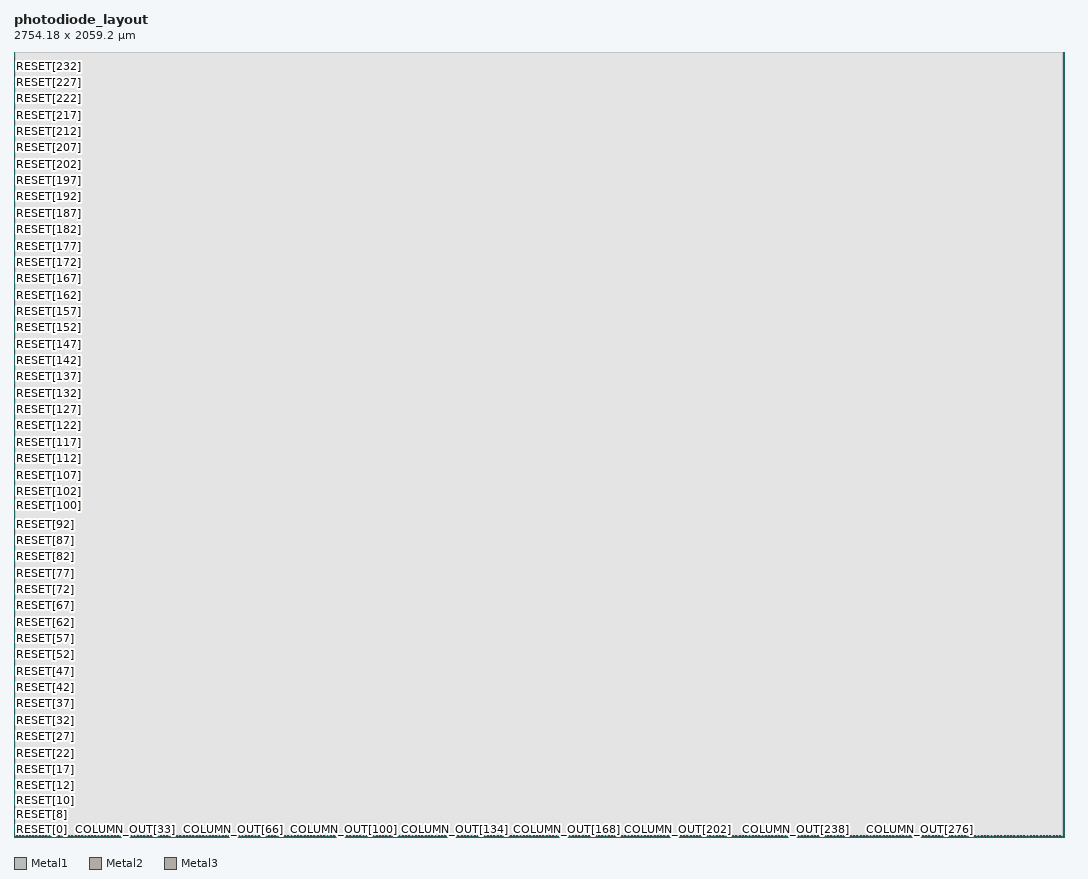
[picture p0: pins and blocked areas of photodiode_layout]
MACRO photodiode_layout
  CLASS BLOCK ;
  ORIGIN 0 0 ;
  FOREIGN photodiode_layout ;
  SIZE 2754.18 BY 2059.2 ;
  SYMMETRY X Y ;

  PIN ROW_SELECT[0]
    DIRECTION INPUT ;
    USE SIGNAL ;
    PORT
      LAYER Metal1 ;
        RECT 0.250 2.730 0.530 2.980 ;
    END
  END ROW_SELECT[0]

  PIN ROW_SELECT[1]
    DIRECTION INPUT ;
    USE SIGNAL ;
    PORT
      LAYER Metal1 ;
        RECT 0.250 11.310 0.530 11.560 ;
    END
  END ROW_SELECT[1]

  PIN ROW_SELECT[2]
    DIRECTION INPUT ;
    USE SIGNAL ;
    PORT
      LAYER Metal1 ;
        RECT 0.250 19.890 0.530 20.140 ;
    END
  END ROW_SELECT[2]

  PIN ROW_SELECT[3]
    DIRECTION INPUT ;
    USE SIGNAL ;
    PORT
      LAYER Metal1 ;
        RECT 0.250 28.470 0.530 28.720 ;
    END
  END ROW_SELECT[3]

  PIN ROW_SELECT[4]
    DIRECTION INPUT ;
    USE SIGNAL ;
    PORT
      LAYER Metal1 ;
        RECT 0.250 37.050 0.530 37.300 ;
    END
  END ROW_SELECT[4]

  PIN ROW_SELECT[5]
    DIRECTION INPUT ;
    USE SIGNAL ;
    PORT
      LAYER Metal1 ;
        RECT 0.250 45.630 0.530 45.880 ;
    END
  END ROW_SELECT[5]

  PIN ROW_SELECT[6]
    DIRECTION INPUT ;
    USE SIGNAL ;
    PORT
      LAYER Metal1 ;
        RECT 0.250 54.210 0.530 54.460 ;
    END
  END ROW_SELECT[6]

  PIN ROW_SELECT[7]
    DIRECTION INPUT ;
    USE SIGNAL ;
    PORT
      LAYER Metal1 ;
        RECT 0.250 62.790 0.530 63.040 ;
    END
  END ROW_SELECT[7]

  PIN ROW_SELECT[8]
    DIRECTION INPUT ;
    USE SIGNAL ;
    PORT
      LAYER Metal1 ;
        RECT 0.250 71.370 0.530 71.620 ;
    END
  END ROW_SELECT[8]

  PIN ROW_SELECT[9]
    DIRECTION INPUT ;
    USE SIGNAL ;
    PORT
      LAYER Metal1 ;
        RECT 0.250 79.950 0.530 80.200 ;
    END
  END ROW_SELECT[9]

  PIN ROW_SELECT[10]
    DIRECTION INPUT ;
    USE SIGNAL ;
    PORT
      LAYER Metal1 ;
        RECT 0.250 88.530 0.530 88.780 ;
    END
  END ROW_SELECT[10]

  PIN ROW_SELECT[11]
    DIRECTION INPUT ;
    USE SIGNAL ;
    PORT
      LAYER Metal1 ;
        RECT 0.250 97.110 0.530 97.360 ;
    END
  END ROW_SELECT[11]

  PIN ROW_SELECT[12]
    DIRECTION INPUT ;
    USE SIGNAL ;
    PORT
      LAYER Metal1 ;
        RECT 0.250 105.690 0.530 105.940 ;
    END
  END ROW_SELECT[12]

  PIN ROW_SELECT[13]
    DIRECTION INPUT ;
    USE SIGNAL ;
    PORT
      LAYER Metal1 ;
        RECT 0.250 114.270 0.530 114.520 ;
    END
  END ROW_SELECT[13]

  PIN ROW_SELECT[14]
    DIRECTION INPUT ;
    USE SIGNAL ;
    PORT
      LAYER Metal1 ;
        RECT 0.250 122.850 0.530 123.100 ;
    END
  END ROW_SELECT[14]

  PIN ROW_SELECT[15]
    DIRECTION INPUT ;
    USE SIGNAL ;
    PORT
      LAYER Metal1 ;
        RECT 0.250 131.430 0.530 131.680 ;
    END
  END ROW_SELECT[15]

  PIN ROW_SELECT[16]
    DIRECTION INPUT ;
    USE SIGNAL ;
    PORT
      LAYER Metal1 ;
        RECT 0.250 140.010 0.530 140.260 ;
    END
  END ROW_SELECT[16]

  PIN ROW_SELECT[17]
    DIRECTION INPUT ;
    USE SIGNAL ;
    PORT
      LAYER Metal1 ;
        RECT 0.250 148.590 0.530 148.840 ;
    END
  END ROW_SELECT[17]

  PIN ROW_SELECT[18]
    DIRECTION INPUT ;
    USE SIGNAL ;
    PORT
      LAYER Metal1 ;
        RECT 0.250 157.170 0.530 157.420 ;
    END
  END ROW_SELECT[18]

  PIN ROW_SELECT[19]
    DIRECTION INPUT ;
    USE SIGNAL ;
    PORT
      LAYER Metal1 ;
        RECT 0.250 165.750 0.530 166.000 ;
    END
  END ROW_SELECT[19]

  PIN ROW_SELECT[20]
    DIRECTION INPUT ;
    USE SIGNAL ;
    PORT
      LAYER Metal1 ;
        RECT 0.250 174.330 0.530 174.580 ;
    END
  END ROW_SELECT[20]

  PIN ROW_SELECT[21]
    DIRECTION INPUT ;
    USE SIGNAL ;
    PORT
      LAYER Metal1 ;
        RECT 0.250 182.910 0.530 183.160 ;
    END
  END ROW_SELECT[21]

  PIN ROW_SELECT[22]
    DIRECTION INPUT ;
    USE SIGNAL ;
    PORT
      LAYER Metal1 ;
        RECT 0.250 191.490 0.530 191.740 ;
    END
  END ROW_SELECT[22]

  PIN ROW_SELECT[23]
    DIRECTION INPUT ;
    USE SIGNAL ;
    PORT
      LAYER Metal1 ;
        RECT 0.250 200.070 0.530 200.320 ;
    END
  END ROW_SELECT[23]

  PIN ROW_SELECT[24]
    DIRECTION INPUT ;
    USE SIGNAL ;
    PORT
      LAYER Metal1 ;
        RECT 0.250 208.650 0.530 208.900 ;
    END
  END ROW_SELECT[24]

  PIN ROW_SELECT[25]
    DIRECTION INPUT ;
    USE SIGNAL ;
    PORT
      LAYER Metal1 ;
        RECT 0.250 217.230 0.530 217.480 ;
    END
  END ROW_SELECT[25]

  PIN ROW_SELECT[26]
    DIRECTION INPUT ;
    USE SIGNAL ;
    PORT
      LAYER Metal1 ;
        RECT 0.250 225.810 0.530 226.060 ;
    END
  END ROW_SELECT[26]

  PIN ROW_SELECT[27]
    DIRECTION INPUT ;
    USE SIGNAL ;
    PORT
      LAYER Metal1 ;
        RECT 0.250 234.390 0.530 234.640 ;
    END
  END ROW_SELECT[27]

  PIN ROW_SELECT[28]
    DIRECTION INPUT ;
    USE SIGNAL ;
    PORT
      LAYER Metal1 ;
        RECT 0.250 242.970 0.530 243.220 ;
    END
  END ROW_SELECT[28]

  PIN ROW_SELECT[29]
    DIRECTION INPUT ;
    USE SIGNAL ;
    PORT
      LAYER Metal1 ;
        RECT 0.250 251.550 0.530 251.800 ;
    END
  END ROW_SELECT[29]

  PIN ROW_SELECT[30]
    DIRECTION INPUT ;
    USE SIGNAL ;
    PORT
      LAYER Metal1 ;
        RECT 0.250 260.130 0.530 260.380 ;
    END
  END ROW_SELECT[30]

  PIN ROW_SELECT[31]
    DIRECTION INPUT ;
    USE SIGNAL ;
    PORT
      LAYER Metal1 ;
        RECT 0.250 268.710 0.530 268.960 ;
    END
  END ROW_SELECT[31]

  PIN ROW_SELECT[32]
    DIRECTION INPUT ;
    USE SIGNAL ;
    PORT
      LAYER Metal1 ;
        RECT 0.250 277.290 0.530 277.540 ;
    END
  END ROW_SELECT[32]

  PIN ROW_SELECT[33]
    DIRECTION INPUT ;
    USE SIGNAL ;
    PORT
      LAYER Metal1 ;
        RECT 0.250 285.870 0.530 286.120 ;
    END
  END ROW_SELECT[33]

  PIN ROW_SELECT[34]
    DIRECTION INPUT ;
    USE SIGNAL ;
    PORT
      LAYER Metal1 ;
        RECT 0.250 294.450 0.530 294.700 ;
    END
  END ROW_SELECT[34]

  PIN ROW_SELECT[35]
    DIRECTION INPUT ;
    USE SIGNAL ;
    PORT
      LAYER Metal1 ;
        RECT 0.250 303.030 0.530 303.280 ;
    END
  END ROW_SELECT[35]

  PIN ROW_SELECT[36]
    DIRECTION INPUT ;
    USE SIGNAL ;
    PORT
      LAYER Metal1 ;
        RECT 0.250 311.610 0.530 311.860 ;
    END
  END ROW_SELECT[36]

  PIN ROW_SELECT[37]
    DIRECTION INPUT ;
    USE SIGNAL ;
    PORT
      LAYER Metal1 ;
        RECT 0.250 320.190 0.530 320.440 ;
    END
  END ROW_SELECT[37]

  PIN ROW_SELECT[38]
    DIRECTION INPUT ;
    USE SIGNAL ;
    PORT
      LAYER Metal1 ;
        RECT 0.250 328.770 0.530 329.020 ;
    END
  END ROW_SELECT[38]

  PIN ROW_SELECT[39]
    DIRECTION INPUT ;
    USE SIGNAL ;
    PORT
      LAYER Metal1 ;
        RECT 0.250 337.350 0.530 337.600 ;
    END
  END ROW_SELECT[39]

  PIN ROW_SELECT[40]
    DIRECTION INPUT ;
    USE SIGNAL ;
    PORT
      LAYER Metal1 ;
        RECT 0.250 345.930 0.530 346.180 ;
    END
  END ROW_SELECT[40]

  PIN ROW_SELECT[41]
    DIRECTION INPUT ;
    USE SIGNAL ;
    PORT
      LAYER Metal1 ;
        RECT 0.250 354.510 0.530 354.760 ;
    END
  END ROW_SELECT[41]

  PIN ROW_SELECT[42]
    DIRECTION INPUT ;
    USE SIGNAL ;
    PORT
      LAYER Metal1 ;
        RECT 0.250 363.090 0.530 363.340 ;
    END
  END ROW_SELECT[42]

  PIN ROW_SELECT[43]
    DIRECTION INPUT ;
    USE SIGNAL ;
    PORT
      LAYER Metal1 ;
        RECT 0.250 371.670 0.530 371.920 ;
    END
  END ROW_SELECT[43]

  PIN ROW_SELECT[44]
    DIRECTION INPUT ;
    USE SIGNAL ;
    PORT
      LAYER Metal1 ;
        RECT 0.250 380.250 0.530 380.500 ;
    END
  END ROW_SELECT[44]

  PIN ROW_SELECT[45]
    DIRECTION INPUT ;
    USE SIGNAL ;
    PORT
      LAYER Metal1 ;
        RECT 0.250 388.830 0.530 389.080 ;
    END
  END ROW_SELECT[45]

  PIN ROW_SELECT[46]
    DIRECTION INPUT ;
    USE SIGNAL ;
    PORT
      LAYER Metal1 ;
        RECT 0.250 397.410 0.530 397.660 ;
    END
  END ROW_SELECT[46]

  PIN ROW_SELECT[47]
    DIRECTION INPUT ;
    USE SIGNAL ;
    PORT
      LAYER Metal1 ;
        RECT 0.250 405.990 0.530 406.240 ;
    END
  END ROW_SELECT[47]

  PIN ROW_SELECT[48]
    DIRECTION INPUT ;
    USE SIGNAL ;
    PORT
      LAYER Metal1 ;
        RECT 0.250 414.570 0.530 414.820 ;
    END
  END ROW_SELECT[48]

  PIN ROW_SELECT[49]
    DIRECTION INPUT ;
    USE SIGNAL ;
    PORT
      LAYER Metal1 ;
        RECT 0.250 423.150 0.530 423.400 ;
    END
  END ROW_SELECT[49]

  PIN ROW_SELECT[50]
    DIRECTION INPUT ;
    USE SIGNAL ;
    PORT
      LAYER Metal1 ;
        RECT 0.250 431.730 0.530 431.980 ;
    END
  END ROW_SELECT[50]

  PIN ROW_SELECT[51]
    DIRECTION INPUT ;
    USE SIGNAL ;
    PORT
      LAYER Metal1 ;
        RECT 0.250 440.310 0.530 440.560 ;
    END
  END ROW_SELECT[51]

  PIN ROW_SELECT[52]
    DIRECTION INPUT ;
    USE SIGNAL ;
    PORT
      LAYER Metal1 ;
        RECT 0.250 448.890 0.530 449.140 ;
    END
  END ROW_SELECT[52]

  PIN ROW_SELECT[53]
    DIRECTION INPUT ;
    USE SIGNAL ;
    PORT
      LAYER Metal1 ;
        RECT 0.250 457.470 0.530 457.720 ;
    END
  END ROW_SELECT[53]

  PIN ROW_SELECT[54]
    DIRECTION INPUT ;
    USE SIGNAL ;
    PORT
      LAYER Metal1 ;
        RECT 0.250 466.050 0.530 466.300 ;
    END
  END ROW_SELECT[54]

  PIN ROW_SELECT[55]
    DIRECTION INPUT ;
    USE SIGNAL ;
    PORT
      LAYER Metal1 ;
        RECT 0.250 474.630 0.530 474.880 ;
    END
  END ROW_SELECT[55]

  PIN ROW_SELECT[56]
    DIRECTION INPUT ;
    USE SIGNAL ;
    PORT
      LAYER Metal1 ;
        RECT 0.250 483.210 0.530 483.460 ;
    END
  END ROW_SELECT[56]

  PIN ROW_SELECT[57]
    DIRECTION INPUT ;
    USE SIGNAL ;
    PORT
      LAYER Metal1 ;
        RECT 0.250 491.790 0.530 492.040 ;
    END
  END ROW_SELECT[57]

  PIN ROW_SELECT[58]
    DIRECTION INPUT ;
    USE SIGNAL ;
    PORT
      LAYER Metal1 ;
        RECT 0.250 500.370 0.530 500.620 ;
    END
  END ROW_SELECT[58]

  PIN ROW_SELECT[59]
    DIRECTION INPUT ;
    USE SIGNAL ;
    PORT
      LAYER Metal1 ;
        RECT 0.250 508.950 0.530 509.200 ;
    END
  END ROW_SELECT[59]

  PIN ROW_SELECT[60]
    DIRECTION INPUT ;
    USE SIGNAL ;
    PORT
      LAYER Metal1 ;
        RECT 0.250 517.530 0.530 517.780 ;
    END
  END ROW_SELECT[60]

  PIN ROW_SELECT[61]
    DIRECTION INPUT ;
    USE SIGNAL ;
    PORT
      LAYER Metal1 ;
        RECT 0.250 526.110 0.530 526.360 ;
    END
  END ROW_SELECT[61]

  PIN ROW_SELECT[62]
    DIRECTION INPUT ;
    USE SIGNAL ;
    PORT
      LAYER Metal1 ;
        RECT 0.250 534.690 0.530 534.940 ;
    END
  END ROW_SELECT[62]

  PIN ROW_SELECT[63]
    DIRECTION INPUT ;
    USE SIGNAL ;
    PORT
      LAYER Metal1 ;
        RECT 0.250 543.270 0.530 543.520 ;
    END
  END ROW_SELECT[63]

  PIN ROW_SELECT[64]
    DIRECTION INPUT ;
    USE SIGNAL ;
    PORT
      LAYER Metal1 ;
        RECT 0.250 551.850 0.530 552.100 ;
    END
  END ROW_SELECT[64]

  PIN ROW_SELECT[65]
    DIRECTION INPUT ;
    USE SIGNAL ;
    PORT
      LAYER Metal1 ;
        RECT 0.250 560.430 0.530 560.680 ;
    END
  END ROW_SELECT[65]

  PIN ROW_SELECT[66]
    DIRECTION INPUT ;
    USE SIGNAL ;
    PORT
      LAYER Metal1 ;
        RECT 0.250 569.010 0.530 569.260 ;
    END
  END ROW_SELECT[66]

  PIN ROW_SELECT[67]
    DIRECTION INPUT ;
    USE SIGNAL ;
    PORT
      LAYER Metal1 ;
        RECT 0.250 577.590 0.530 577.840 ;
    END
  END ROW_SELECT[67]

  PIN ROW_SELECT[68]
    DIRECTION INPUT ;
    USE SIGNAL ;
    PORT
      LAYER Metal1 ;
        RECT 0.250 586.170 0.530 586.420 ;
    END
  END ROW_SELECT[68]

  PIN ROW_SELECT[69]
    DIRECTION INPUT ;
    USE SIGNAL ;
    PORT
      LAYER Metal1 ;
        RECT 0.250 594.750 0.530 595.000 ;
    END
  END ROW_SELECT[69]

  PIN ROW_SELECT[70]
    DIRECTION INPUT ;
    USE SIGNAL ;
    PORT
      LAYER Metal1 ;
        RECT 0.250 603.330 0.530 603.580 ;
    END
  END ROW_SELECT[70]

  PIN ROW_SELECT[71]
    DIRECTION INPUT ;
    USE SIGNAL ;
    PORT
      LAYER Metal1 ;
        RECT 0.250 611.910 0.530 612.160 ;
    END
  END ROW_SELECT[71]

  PIN ROW_SELECT[72]
    DIRECTION INPUT ;
    USE SIGNAL ;
    PORT
      LAYER Metal1 ;
        RECT 0.250 620.490 0.530 620.740 ;
    END
  END ROW_SELECT[72]

  PIN ROW_SELECT[73]
    DIRECTION INPUT ;
    USE SIGNAL ;
    PORT
      LAYER Metal1 ;
        RECT 0.250 629.070 0.530 629.320 ;
    END
  END ROW_SELECT[73]

  PIN ROW_SELECT[74]
    DIRECTION INPUT ;
    USE SIGNAL ;
    PORT
      LAYER Metal1 ;
        RECT 0.250 637.650 0.530 637.900 ;
    END
  END ROW_SELECT[74]

  PIN ROW_SELECT[75]
    DIRECTION INPUT ;
    USE SIGNAL ;
    PORT
      LAYER Metal1 ;
        RECT 0.250 646.230 0.530 646.480 ;
    END
  END ROW_SELECT[75]

  PIN ROW_SELECT[76]
    DIRECTION INPUT ;
    USE SIGNAL ;
    PORT
      LAYER Metal1 ;
        RECT 0.250 654.810 0.530 655.060 ;
    END
  END ROW_SELECT[76]

  PIN ROW_SELECT[77]
    DIRECTION INPUT ;
    USE SIGNAL ;
    PORT
      LAYER Metal1 ;
        RECT 0.250 663.390 0.530 663.640 ;
    END
  END ROW_SELECT[77]

  PIN ROW_SELECT[78]
    DIRECTION INPUT ;
    USE SIGNAL ;
    PORT
      LAYER Metal1 ;
        RECT 0.250 671.970 0.530 672.220 ;
    END
  END ROW_SELECT[78]

  PIN ROW_SELECT[79]
    DIRECTION INPUT ;
    USE SIGNAL ;
    PORT
      LAYER Metal1 ;
        RECT 0.250 680.550 0.530 680.800 ;
    END
  END ROW_SELECT[79]

  PIN ROW_SELECT[80]
    DIRECTION INPUT ;
    USE SIGNAL ;
    PORT
      LAYER Metal1 ;
        RECT 0.250 689.130 0.530 689.380 ;
    END
  END ROW_SELECT[80]

  PIN ROW_SELECT[81]
    DIRECTION INPUT ;
    USE SIGNAL ;
    PORT
      LAYER Metal1 ;
        RECT 0.250 697.710 0.530 697.960 ;
    END
  END ROW_SELECT[81]

  PIN ROW_SELECT[82]
    DIRECTION INPUT ;
    USE SIGNAL ;
    PORT
      LAYER Metal1 ;
        RECT 0.250 706.290 0.530 706.540 ;
    END
  END ROW_SELECT[82]

  PIN ROW_SELECT[83]
    DIRECTION INPUT ;
    USE SIGNAL ;
    PORT
      LAYER Metal1 ;
        RECT 0.250 714.870 0.530 715.120 ;
    END
  END ROW_SELECT[83]

  PIN ROW_SELECT[84]
    DIRECTION INPUT ;
    USE SIGNAL ;
    PORT
      LAYER Metal1 ;
        RECT 0.250 723.450 0.530 723.700 ;
    END
  END ROW_SELECT[84]

  PIN ROW_SELECT[85]
    DIRECTION INPUT ;
    USE SIGNAL ;
    PORT
      LAYER Metal1 ;
        RECT 0.250 732.030 0.530 732.280 ;
    END
  END ROW_SELECT[85]

  PIN ROW_SELECT[86]
    DIRECTION INPUT ;
    USE SIGNAL ;
    PORT
      LAYER Metal1 ;
        RECT 0.250 740.610 0.530 740.860 ;
    END
  END ROW_SELECT[86]

  PIN ROW_SELECT[87]
    DIRECTION INPUT ;
    USE SIGNAL ;
    PORT
      LAYER Metal1 ;
        RECT 0.250 749.190 0.530 749.440 ;
    END
  END ROW_SELECT[87]

  PIN ROW_SELECT[88]
    DIRECTION INPUT ;
    USE SIGNAL ;
    PORT
      LAYER Metal1 ;
        RECT 0.250 757.770 0.530 758.020 ;
    END
  END ROW_SELECT[88]

  PIN ROW_SELECT[89]
    DIRECTION INPUT ;
    USE SIGNAL ;
    PORT
      LAYER Metal1 ;
        RECT 0.250 766.350 0.530 766.600 ;
    END
  END ROW_SELECT[89]

  PIN ROW_SELECT[90]
    DIRECTION INPUT ;
    USE SIGNAL ;
    PORT
      LAYER Metal1 ;
        RECT 0.250 774.930 0.530 775.180 ;
    END
  END ROW_SELECT[90]

  PIN ROW_SELECT[91]
    DIRECTION INPUT ;
    USE SIGNAL ;
    PORT
      LAYER Metal1 ;
        RECT 0.250 783.510 0.530 783.760 ;
    END
  END ROW_SELECT[91]

  PIN ROW_SELECT[92]
    DIRECTION INPUT ;
    USE SIGNAL ;
    PORT
      LAYER Metal1 ;
        RECT 0.250 792.090 0.530 792.340 ;
    END
  END ROW_SELECT[92]

  PIN ROW_SELECT[93]
    DIRECTION INPUT ;
    USE SIGNAL ;
    PORT
      LAYER Metal1 ;
        RECT 0.250 800.670 0.530 800.920 ;
    END
  END ROW_SELECT[93]

  PIN ROW_SELECT[94]
    DIRECTION INPUT ;
    USE SIGNAL ;
    PORT
      LAYER Metal1 ;
        RECT 0.250 809.250 0.530 809.500 ;
    END
  END ROW_SELECT[94]

  PIN ROW_SELECT[95]
    DIRECTION INPUT ;
    USE SIGNAL ;
    PORT
      LAYER Metal1 ;
        RECT 0.250 817.830 0.530 818.080 ;
    END
  END ROW_SELECT[95]

  PIN ROW_SELECT[96]
    DIRECTION INPUT ;
    USE SIGNAL ;
    PORT
      LAYER Metal1 ;
        RECT 0.250 826.410 0.530 826.660 ;
    END
  END ROW_SELECT[96]

  PIN ROW_SELECT[97]
    DIRECTION INPUT ;
    USE SIGNAL ;
    PORT
      LAYER Metal1 ;
        RECT 0.250 834.990 0.530 835.240 ;
    END
  END ROW_SELECT[97]

  PIN ROW_SELECT[98]
    DIRECTION INPUT ;
    USE SIGNAL ;
    PORT
      LAYER Metal1 ;
        RECT 0.250 843.570 0.530 843.820 ;
    END
  END ROW_SELECT[98]

  PIN ROW_SELECT[99]
    DIRECTION INPUT ;
    USE SIGNAL ;
    PORT
      LAYER Metal1 ;
        RECT 0.250 852.150 0.530 852.400 ;
    END
  END ROW_SELECT[99]

  PIN ROW_SELECT[100]
    DIRECTION INPUT ;
    USE SIGNAL ;
    PORT
      LAYER Metal1 ;
        RECT 0.250 860.730 0.530 860.980 ;
    END
  END ROW_SELECT[100]

  PIN ROW_SELECT[101]
    DIRECTION INPUT ;
    USE SIGNAL ;
    PORT
      LAYER Metal1 ;
        RECT 0.250 869.310 0.530 869.560 ;
    END
  END ROW_SELECT[101]

  PIN ROW_SELECT[102]
    DIRECTION INPUT ;
    USE SIGNAL ;
    PORT
      LAYER Metal1 ;
        RECT 0.250 877.890 0.530 878.140 ;
    END
  END ROW_SELECT[102]

  PIN ROW_SELECT[103]
    DIRECTION INPUT ;
    USE SIGNAL ;
    PORT
      LAYER Metal1 ;
        RECT 0.250 886.470 0.530 886.720 ;
    END
  END ROW_SELECT[103]

  PIN ROW_SELECT[104]
    DIRECTION INPUT ;
    USE SIGNAL ;
    PORT
      LAYER Metal1 ;
        RECT 0.250 895.050 0.530 895.300 ;
    END
  END ROW_SELECT[104]

  PIN ROW_SELECT[105]
    DIRECTION INPUT ;
    USE SIGNAL ;
    PORT
      LAYER Metal1 ;
        RECT 0.250 903.630 0.530 903.880 ;
    END
  END ROW_SELECT[105]

  PIN ROW_SELECT[106]
    DIRECTION INPUT ;
    USE SIGNAL ;
    PORT
      LAYER Metal1 ;
        RECT 0.250 912.210 0.530 912.460 ;
    END
  END ROW_SELECT[106]

  PIN ROW_SELECT[107]
    DIRECTION INPUT ;
    USE SIGNAL ;
    PORT
      LAYER Metal1 ;
        RECT 0.250 920.790 0.530 921.040 ;
    END
  END ROW_SELECT[107]

  PIN ROW_SELECT[108]
    DIRECTION INPUT ;
    USE SIGNAL ;
    PORT
      LAYER Metal1 ;
        RECT 0.250 929.370 0.530 929.620 ;
    END
  END ROW_SELECT[108]

  PIN ROW_SELECT[109]
    DIRECTION INPUT ;
    USE SIGNAL ;
    PORT
      LAYER Metal1 ;
        RECT 0.250 937.950 0.530 938.200 ;
    END
  END ROW_SELECT[109]

  PIN ROW_SELECT[110]
    DIRECTION INPUT ;
    USE SIGNAL ;
    PORT
      LAYER Metal1 ;
        RECT 0.250 946.530 0.530 946.780 ;
    END
  END ROW_SELECT[110]

  PIN ROW_SELECT[111]
    DIRECTION INPUT ;
    USE SIGNAL ;
    PORT
      LAYER Metal1 ;
        RECT 0.250 955.110 0.530 955.360 ;
    END
  END ROW_SELECT[111]

  PIN ROW_SELECT[112]
    DIRECTION INPUT ;
    USE SIGNAL ;
    PORT
      LAYER Metal1 ;
        RECT 0.250 963.690 0.530 963.940 ;
    END
  END ROW_SELECT[112]

  PIN ROW_SELECT[113]
    DIRECTION INPUT ;
    USE SIGNAL ;
    PORT
      LAYER Metal1 ;
        RECT 0.250 972.270 0.530 972.520 ;
    END
  END ROW_SELECT[113]

  PIN ROW_SELECT[114]
    DIRECTION INPUT ;
    USE SIGNAL ;
    PORT
      LAYER Metal1 ;
        RECT 0.250 980.850 0.530 981.100 ;
    END
  END ROW_SELECT[114]

  PIN ROW_SELECT[115]
    DIRECTION INPUT ;
    USE SIGNAL ;
    PORT
      LAYER Metal1 ;
        RECT 0.250 989.430 0.530 989.680 ;
    END
  END ROW_SELECT[115]

  PIN ROW_SELECT[116]
    DIRECTION INPUT ;
    USE SIGNAL ;
    PORT
      LAYER Metal1 ;
        RECT 0.250 998.010 0.530 998.260 ;
    END
  END ROW_SELECT[116]

  PIN ROW_SELECT[117]
    DIRECTION INPUT ;
    USE SIGNAL ;
    PORT
      LAYER Metal1 ;
        RECT 0.250 1006.590 0.530 1006.840 ;
    END
  END ROW_SELECT[117]

  PIN ROW_SELECT[118]
    DIRECTION INPUT ;
    USE SIGNAL ;
    PORT
      LAYER Metal1 ;
        RECT 0.250 1015.170 0.530 1015.420 ;
    END
  END ROW_SELECT[118]

  PIN ROW_SELECT[119]
    DIRECTION INPUT ;
    USE SIGNAL ;
    PORT
      LAYER Metal1 ;
        RECT 0.250 1023.750 0.530 1024.000 ;
    END
  END ROW_SELECT[119]

  PIN ROW_SELECT[120]
    DIRECTION INPUT ;
    USE SIGNAL ;
    PORT
      LAYER Metal1 ;
        RECT 0.250 1032.330 0.530 1032.580 ;
    END
  END ROW_SELECT[120]

  PIN ROW_SELECT[121]
    DIRECTION INPUT ;
    USE SIGNAL ;
    PORT
      LAYER Metal1 ;
        RECT 0.250 1040.910 0.530 1041.160 ;
    END
  END ROW_SELECT[121]

  PIN ROW_SELECT[122]
    DIRECTION INPUT ;
    USE SIGNAL ;
    PORT
      LAYER Metal1 ;
        RECT 0.250 1049.490 0.530 1049.740 ;
    END
  END ROW_SELECT[122]

  PIN ROW_SELECT[123]
    DIRECTION INPUT ;
    USE SIGNAL ;
    PORT
      LAYER Metal1 ;
        RECT 0.250 1058.070 0.530 1058.320 ;
    END
  END ROW_SELECT[123]

  PIN ROW_SELECT[124]
    DIRECTION INPUT ;
    USE SIGNAL ;
    PORT
      LAYER Metal1 ;
        RECT 0.250 1066.650 0.530 1066.900 ;
    END
  END ROW_SELECT[124]

  PIN ROW_SELECT[125]
    DIRECTION INPUT ;
    USE SIGNAL ;
    PORT
      LAYER Metal1 ;
        RECT 0.250 1075.230 0.530 1075.480 ;
    END
  END ROW_SELECT[125]

  PIN ROW_SELECT[126]
    DIRECTION INPUT ;
    USE SIGNAL ;
    PORT
      LAYER Metal1 ;
        RECT 0.250 1083.810 0.530 1084.060 ;
    END
  END ROW_SELECT[126]

  PIN ROW_SELECT[127]
    DIRECTION INPUT ;
    USE SIGNAL ;
    PORT
      LAYER Metal1 ;
        RECT 0.250 1092.390 0.530 1092.640 ;
    END
  END ROW_SELECT[127]

  PIN ROW_SELECT[128]
    DIRECTION INPUT ;
    USE SIGNAL ;
    PORT
      LAYER Metal1 ;
        RECT 0.250 1100.970 0.530 1101.220 ;
    END
  END ROW_SELECT[128]

  PIN ROW_SELECT[129]
    DIRECTION INPUT ;
    USE SIGNAL ;
    PORT
      LAYER Metal1 ;
        RECT 0.250 1109.550 0.530 1109.800 ;
    END
  END ROW_SELECT[129]

  PIN ROW_SELECT[130]
    DIRECTION INPUT ;
    USE SIGNAL ;
    PORT
      LAYER Metal1 ;
        RECT 0.250 1118.130 0.530 1118.380 ;
    END
  END ROW_SELECT[130]

  PIN ROW_SELECT[131]
    DIRECTION INPUT ;
    USE SIGNAL ;
    PORT
      LAYER Metal1 ;
        RECT 0.250 1126.710 0.530 1126.960 ;
    END
  END ROW_SELECT[131]

  PIN ROW_SELECT[132]
    DIRECTION INPUT ;
    USE SIGNAL ;
    PORT
      LAYER Metal1 ;
        RECT 0.250 1135.290 0.530 1135.540 ;
    END
  END ROW_SELECT[132]

  PIN ROW_SELECT[133]
    DIRECTION INPUT ;
    USE SIGNAL ;
    PORT
      LAYER Metal1 ;
        RECT 0.250 1143.870 0.530 1144.120 ;
    END
  END ROW_SELECT[133]

  PIN ROW_SELECT[134]
    DIRECTION INPUT ;
    USE SIGNAL ;
    PORT
      LAYER Metal1 ;
        RECT 0.250 1152.450 0.530 1152.700 ;
    END
  END ROW_SELECT[134]

  PIN ROW_SELECT[135]
    DIRECTION INPUT ;
    USE SIGNAL ;
    PORT
      LAYER Metal1 ;
        RECT 0.250 1161.030 0.530 1161.280 ;
    END
  END ROW_SELECT[135]

  PIN ROW_SELECT[136]
    DIRECTION INPUT ;
    USE SIGNAL ;
    PORT
      LAYER Metal1 ;
        RECT 0.250 1169.610 0.530 1169.860 ;
    END
  END ROW_SELECT[136]

  PIN ROW_SELECT[137]
    DIRECTION INPUT ;
    USE SIGNAL ;
    PORT
      LAYER Metal1 ;
        RECT 0.250 1178.190 0.530 1178.440 ;
    END
  END ROW_SELECT[137]

  PIN ROW_SELECT[138]
    DIRECTION INPUT ;
    USE SIGNAL ;
    PORT
      LAYER Metal1 ;
        RECT 0.250 1186.770 0.530 1187.020 ;
    END
  END ROW_SELECT[138]

  PIN ROW_SELECT[139]
    DIRECTION INPUT ;
    USE SIGNAL ;
    PORT
      LAYER Metal1 ;
        RECT 0.250 1195.350 0.530 1195.600 ;
    END
  END ROW_SELECT[139]

  PIN ROW_SELECT[140]
    DIRECTION INPUT ;
    USE SIGNAL ;
    PORT
      LAYER Metal1 ;
        RECT 0.250 1203.930 0.530 1204.180 ;
    END
  END ROW_SELECT[140]

  PIN ROW_SELECT[141]
    DIRECTION INPUT ;
    USE SIGNAL ;
    PORT
      LAYER Metal1 ;
        RECT 0.250 1212.510 0.530 1212.760 ;
    END
  END ROW_SELECT[141]

  PIN ROW_SELECT[142]
    DIRECTION INPUT ;
    USE SIGNAL ;
    PORT
      LAYER Metal1 ;
        RECT 0.250 1221.090 0.530 1221.340 ;
    END
  END ROW_SELECT[142]

  PIN ROW_SELECT[143]
    DIRECTION INPUT ;
    USE SIGNAL ;
    PORT
      LAYER Metal1 ;
        RECT 0.250 1229.670 0.530 1229.920 ;
    END
  END ROW_SELECT[143]

  PIN ROW_SELECT[144]
    DIRECTION INPUT ;
    USE SIGNAL ;
    PORT
      LAYER Metal1 ;
        RECT 0.250 1238.250 0.530 1238.500 ;
    END
  END ROW_SELECT[144]

  PIN ROW_SELECT[145]
    DIRECTION INPUT ;
    USE SIGNAL ;
    PORT
      LAYER Metal1 ;
        RECT 0.250 1246.830 0.530 1247.080 ;
    END
  END ROW_SELECT[145]

  PIN ROW_SELECT[146]
    DIRECTION INPUT ;
    USE SIGNAL ;
    PORT
      LAYER Metal1 ;
        RECT 0.250 1255.410 0.530 1255.660 ;
    END
  END ROW_SELECT[146]

  PIN ROW_SELECT[147]
    DIRECTION INPUT ;
    USE SIGNAL ;
    PORT
      LAYER Metal1 ;
        RECT 0.250 1263.990 0.530 1264.240 ;
    END
  END ROW_SELECT[147]

  PIN ROW_SELECT[148]
    DIRECTION INPUT ;
    USE SIGNAL ;
    PORT
      LAYER Metal1 ;
        RECT 0.250 1272.570 0.530 1272.820 ;
    END
  END ROW_SELECT[148]

  PIN ROW_SELECT[149]
    DIRECTION INPUT ;
    USE SIGNAL ;
    PORT
      LAYER Metal1 ;
        RECT 0.250 1281.150 0.530 1281.400 ;
    END
  END ROW_SELECT[149]

  PIN ROW_SELECT[150]
    DIRECTION INPUT ;
    USE SIGNAL ;
    PORT
      LAYER Metal1 ;
        RECT 0.250 1289.730 0.530 1289.980 ;
    END
  END ROW_SELECT[150]

  PIN ROW_SELECT[151]
    DIRECTION INPUT ;
    USE SIGNAL ;
    PORT
      LAYER Metal1 ;
        RECT 0.250 1298.310 0.530 1298.560 ;
    END
  END ROW_SELECT[151]

  PIN ROW_SELECT[152]
    DIRECTION INPUT ;
    USE SIGNAL ;
    PORT
      LAYER Metal1 ;
        RECT 0.250 1306.890 0.530 1307.140 ;
    END
  END ROW_SELECT[152]

  PIN ROW_SELECT[153]
    DIRECTION INPUT ;
    USE SIGNAL ;
    PORT
      LAYER Metal1 ;
        RECT 0.250 1315.470 0.530 1315.720 ;
    END
  END ROW_SELECT[153]

  PIN ROW_SELECT[154]
    DIRECTION INPUT ;
    USE SIGNAL ;
    PORT
      LAYER Metal1 ;
        RECT 0.250 1324.050 0.530 1324.300 ;
    END
  END ROW_SELECT[154]

  PIN ROW_SELECT[155]
    DIRECTION INPUT ;
    USE SIGNAL ;
    PORT
      LAYER Metal1 ;
        RECT 0.250 1332.630 0.530 1332.880 ;
    END
  END ROW_SELECT[155]

  PIN ROW_SELECT[156]
    DIRECTION INPUT ;
    USE SIGNAL ;
    PORT
      LAYER Metal1 ;
        RECT 0.250 1341.210 0.530 1341.460 ;
    END
  END ROW_SELECT[156]

  PIN ROW_SELECT[157]
    DIRECTION INPUT ;
    USE SIGNAL ;
    PORT
      LAYER Metal1 ;
        RECT 0.250 1349.790 0.530 1350.040 ;
    END
  END ROW_SELECT[157]

  PIN ROW_SELECT[158]
    DIRECTION INPUT ;
    USE SIGNAL ;
    PORT
      LAYER Metal1 ;
        RECT 0.250 1358.370 0.530 1358.620 ;
    END
  END ROW_SELECT[158]

  PIN ROW_SELECT[159]
    DIRECTION INPUT ;
    USE SIGNAL ;
    PORT
      LAYER Metal1 ;
        RECT 0.250 1366.950 0.530 1367.200 ;
    END
  END ROW_SELECT[159]

  PIN ROW_SELECT[160]
    DIRECTION INPUT ;
    USE SIGNAL ;
    PORT
      LAYER Metal1 ;
        RECT 0.250 1375.530 0.530 1375.780 ;
    END
  END ROW_SELECT[160]

  PIN ROW_SELECT[161]
    DIRECTION INPUT ;
    USE SIGNAL ;
    PORT
      LAYER Metal1 ;
        RECT 0.250 1384.110 0.530 1384.360 ;
    END
  END ROW_SELECT[161]

  PIN ROW_SELECT[162]
    DIRECTION INPUT ;
    USE SIGNAL ;
    PORT
      LAYER Metal1 ;
        RECT 0.250 1392.690 0.530 1392.940 ;
    END
  END ROW_SELECT[162]

  PIN ROW_SELECT[163]
    DIRECTION INPUT ;
    USE SIGNAL ;
    PORT
      LAYER Metal1 ;
        RECT 0.250 1401.270 0.530 1401.520 ;
    END
  END ROW_SELECT[163]

  PIN ROW_SELECT[164]
    DIRECTION INPUT ;
    USE SIGNAL ;
    PORT
      LAYER Metal1 ;
        RECT 0.250 1409.850 0.530 1410.100 ;
    END
  END ROW_SELECT[164]

  PIN ROW_SELECT[165]
    DIRECTION INPUT ;
    USE SIGNAL ;
    PORT
      LAYER Metal1 ;
        RECT 0.250 1418.430 0.530 1418.680 ;
    END
  END ROW_SELECT[165]

  PIN ROW_SELECT[166]
    DIRECTION INPUT ;
    USE SIGNAL ;
    PORT
      LAYER Metal1 ;
        RECT 0.250 1427.010 0.530 1427.260 ;
    END
  END ROW_SELECT[166]

  PIN ROW_SELECT[167]
    DIRECTION INPUT ;
    USE SIGNAL ;
    PORT
      LAYER Metal1 ;
        RECT 0.250 1435.590 0.530 1435.840 ;
    END
  END ROW_SELECT[167]

  PIN ROW_SELECT[168]
    DIRECTION INPUT ;
    USE SIGNAL ;
    PORT
      LAYER Metal1 ;
        RECT 0.250 1444.170 0.530 1444.420 ;
    END
  END ROW_SELECT[168]

  PIN ROW_SELECT[169]
    DIRECTION INPUT ;
    USE SIGNAL ;
    PORT
      LAYER Metal1 ;
        RECT 0.250 1452.750 0.530 1453.000 ;
    END
  END ROW_SELECT[169]

  PIN ROW_SELECT[170]
    DIRECTION INPUT ;
    USE SIGNAL ;
    PORT
      LAYER Metal1 ;
        RECT 0.250 1461.330 0.530 1461.580 ;
    END
  END ROW_SELECT[170]

  PIN ROW_SELECT[171]
    DIRECTION INPUT ;
    USE SIGNAL ;
    PORT
      LAYER Metal1 ;
        RECT 0.250 1469.910 0.530 1470.160 ;
    END
  END ROW_SELECT[171]

  PIN ROW_SELECT[172]
    DIRECTION INPUT ;
    USE SIGNAL ;
    PORT
      LAYER Metal1 ;
        RECT 0.250 1478.490 0.530 1478.740 ;
    END
  END ROW_SELECT[172]

  PIN ROW_SELECT[173]
    DIRECTION INPUT ;
    USE SIGNAL ;
    PORT
      LAYER Metal1 ;
        RECT 0.250 1487.070 0.530 1487.320 ;
    END
  END ROW_SELECT[173]

  PIN ROW_SELECT[174]
    DIRECTION INPUT ;
    USE SIGNAL ;
    PORT
      LAYER Metal1 ;
        RECT 0.250 1495.650 0.530 1495.900 ;
    END
  END ROW_SELECT[174]

  PIN ROW_SELECT[175]
    DIRECTION INPUT ;
    USE SIGNAL ;
    PORT
      LAYER Metal1 ;
        RECT 0.250 1504.230 0.530 1504.480 ;
    END
  END ROW_SELECT[175]

  PIN ROW_SELECT[176]
    DIRECTION INPUT ;
    USE SIGNAL ;
    PORT
      LAYER Metal1 ;
        RECT 0.250 1512.810 0.530 1513.060 ;
    END
  END ROW_SELECT[176]

  PIN ROW_SELECT[177]
    DIRECTION INPUT ;
    USE SIGNAL ;
    PORT
      LAYER Metal1 ;
        RECT 0.250 1521.390 0.530 1521.640 ;
    END
  END ROW_SELECT[177]

  PIN ROW_SELECT[178]
    DIRECTION INPUT ;
    USE SIGNAL ;
    PORT
      LAYER Metal1 ;
        RECT 0.250 1529.970 0.530 1530.220 ;
    END
  END ROW_SELECT[178]

  PIN ROW_SELECT[179]
    DIRECTION INPUT ;
    USE SIGNAL ;
    PORT
      LAYER Metal1 ;
        RECT 0.250 1538.550 0.530 1538.800 ;
    END
  END ROW_SELECT[179]

  PIN ROW_SELECT[180]
    DIRECTION INPUT ;
    USE SIGNAL ;
    PORT
      LAYER Metal1 ;
        RECT 0.250 1547.130 0.530 1547.380 ;
    END
  END ROW_SELECT[180]

  PIN ROW_SELECT[181]
    DIRECTION INPUT ;
    USE SIGNAL ;
    PORT
      LAYER Metal1 ;
        RECT 0.250 1555.710 0.530 1555.960 ;
    END
  END ROW_SELECT[181]

  PIN ROW_SELECT[182]
    DIRECTION INPUT ;
    USE SIGNAL ;
    PORT
      LAYER Metal1 ;
        RECT 0.250 1564.290 0.530 1564.540 ;
    END
  END ROW_SELECT[182]

  PIN ROW_SELECT[183]
    DIRECTION INPUT ;
    USE SIGNAL ;
    PORT
      LAYER Metal1 ;
        RECT 0.250 1572.870 0.530 1573.120 ;
    END
  END ROW_SELECT[183]

  PIN ROW_SELECT[184]
    DIRECTION INPUT ;
    USE SIGNAL ;
    PORT
      LAYER Metal1 ;
        RECT 0.250 1581.450 0.530 1581.700 ;
    END
  END ROW_SELECT[184]

  PIN ROW_SELECT[185]
    DIRECTION INPUT ;
    USE SIGNAL ;
    PORT
      LAYER Metal1 ;
        RECT 0.250 1590.030 0.530 1590.280 ;
    END
  END ROW_SELECT[185]

  PIN ROW_SELECT[186]
    DIRECTION INPUT ;
    USE SIGNAL ;
    PORT
      LAYER Metal1 ;
        RECT 0.250 1598.610 0.530 1598.860 ;
    END
  END ROW_SELECT[186]

  PIN ROW_SELECT[187]
    DIRECTION INPUT ;
    USE SIGNAL ;
    PORT
      LAYER Metal1 ;
        RECT 0.250 1607.190 0.530 1607.440 ;
    END
  END ROW_SELECT[187]

  PIN ROW_SELECT[188]
    DIRECTION INPUT ;
    USE SIGNAL ;
    PORT
      LAYER Metal1 ;
        RECT 0.250 1615.770 0.530 1616.020 ;
    END
  END ROW_SELECT[188]

  PIN ROW_SELECT[189]
    DIRECTION INPUT ;
    USE SIGNAL ;
    PORT
      LAYER Metal1 ;
        RECT 0.250 1624.350 0.530 1624.600 ;
    END
  END ROW_SELECT[189]

  PIN ROW_SELECT[190]
    DIRECTION INPUT ;
    USE SIGNAL ;
    PORT
      LAYER Metal1 ;
        RECT 0.250 1632.930 0.530 1633.180 ;
    END
  END ROW_SELECT[190]

  PIN ROW_SELECT[191]
    DIRECTION INPUT ;
    USE SIGNAL ;
    PORT
      LAYER Metal1 ;
        RECT 0.250 1641.510 0.530 1641.760 ;
    END
  END ROW_SELECT[191]

  PIN ROW_SELECT[192]
    DIRECTION INPUT ;
    USE SIGNAL ;
    PORT
      LAYER Metal1 ;
        RECT 0.250 1650.090 0.530 1650.340 ;
    END
  END ROW_SELECT[192]

  PIN ROW_SELECT[193]
    DIRECTION INPUT ;
    USE SIGNAL ;
    PORT
      LAYER Metal1 ;
        RECT 0.250 1658.670 0.530 1658.920 ;
    END
  END ROW_SELECT[193]

  PIN ROW_SELECT[194]
    DIRECTION INPUT ;
    USE SIGNAL ;
    PORT
      LAYER Metal1 ;
        RECT 0.250 1667.250 0.530 1667.500 ;
    END
  END ROW_SELECT[194]

  PIN ROW_SELECT[195]
    DIRECTION INPUT ;
    USE SIGNAL ;
    PORT
      LAYER Metal1 ;
        RECT 0.250 1675.830 0.530 1676.080 ;
    END
  END ROW_SELECT[195]

  PIN ROW_SELECT[196]
    DIRECTION INPUT ;
    USE SIGNAL ;
    PORT
      LAYER Metal1 ;
        RECT 0.250 1684.410 0.530 1684.660 ;
    END
  END ROW_SELECT[196]

  PIN ROW_SELECT[197]
    DIRECTION INPUT ;
    USE SIGNAL ;
    PORT
      LAYER Metal1 ;
        RECT 0.250 1692.990 0.530 1693.240 ;
    END
  END ROW_SELECT[197]

  PIN ROW_SELECT[198]
    DIRECTION INPUT ;
    USE SIGNAL ;
    PORT
      LAYER Metal1 ;
        RECT 0.250 1701.570 0.530 1701.820 ;
    END
  END ROW_SELECT[198]

  PIN ROW_SELECT[199]
    DIRECTION INPUT ;
    USE SIGNAL ;
    PORT
      LAYER Metal1 ;
        RECT 0.250 1710.150 0.530 1710.400 ;
    END
  END ROW_SELECT[199]

  PIN ROW_SELECT[200]
    DIRECTION INPUT ;
    USE SIGNAL ;
    PORT
      LAYER Metal1 ;
        RECT 0.250 1718.730 0.530 1718.980 ;
    END
  END ROW_SELECT[200]

  PIN ROW_SELECT[201]
    DIRECTION INPUT ;
    USE SIGNAL ;
    PORT
      LAYER Metal1 ;
        RECT 0.250 1727.310 0.530 1727.560 ;
    END
  END ROW_SELECT[201]

  PIN ROW_SELECT[202]
    DIRECTION INPUT ;
    USE SIGNAL ;
    PORT
      LAYER Metal1 ;
        RECT 0.250 1735.890 0.530 1736.140 ;
    END
  END ROW_SELECT[202]

  PIN ROW_SELECT[203]
    DIRECTION INPUT ;
    USE SIGNAL ;
    PORT
      LAYER Metal1 ;
        RECT 0.250 1744.470 0.530 1744.720 ;
    END
  END ROW_SELECT[203]

  PIN ROW_SELECT[204]
    DIRECTION INPUT ;
    USE SIGNAL ;
    PORT
      LAYER Metal1 ;
        RECT 0.250 1753.050 0.530 1753.300 ;
    END
  END ROW_SELECT[204]

  PIN ROW_SELECT[205]
    DIRECTION INPUT ;
    USE SIGNAL ;
    PORT
      LAYER Metal1 ;
        RECT 0.250 1761.630 0.530 1761.880 ;
    END
  END ROW_SELECT[205]

  PIN ROW_SELECT[206]
    DIRECTION INPUT ;
    USE SIGNAL ;
    PORT
      LAYER Metal1 ;
        RECT 0.250 1770.210 0.530 1770.460 ;
    END
  END ROW_SELECT[206]

  PIN ROW_SELECT[207]
    DIRECTION INPUT ;
    USE SIGNAL ;
    PORT
      LAYER Metal1 ;
        RECT 0.250 1778.790 0.530 1779.040 ;
    END
  END ROW_SELECT[207]

  PIN ROW_SELECT[208]
    DIRECTION INPUT ;
    USE SIGNAL ;
    PORT
      LAYER Metal1 ;
        RECT 0.250 1787.370 0.530 1787.620 ;
    END
  END ROW_SELECT[208]

  PIN ROW_SELECT[209]
    DIRECTION INPUT ;
    USE SIGNAL ;
    PORT
      LAYER Metal1 ;
        RECT 0.250 1795.950 0.530 1796.200 ;
    END
  END ROW_SELECT[209]

  PIN ROW_SELECT[210]
    DIRECTION INPUT ;
    USE SIGNAL ;
    PORT
      LAYER Metal1 ;
        RECT 0.250 1804.530 0.530 1804.780 ;
    END
  END ROW_SELECT[210]

  PIN ROW_SELECT[211]
    DIRECTION INPUT ;
    USE SIGNAL ;
    PORT
      LAYER Metal1 ;
        RECT 0.250 1813.110 0.530 1813.360 ;
    END
  END ROW_SELECT[211]

  PIN ROW_SELECT[212]
    DIRECTION INPUT ;
    USE SIGNAL ;
    PORT
      LAYER Metal1 ;
        RECT 0.250 1821.690 0.530 1821.940 ;
    END
  END ROW_SELECT[212]

  PIN ROW_SELECT[213]
    DIRECTION INPUT ;
    USE SIGNAL ;
    PORT
      LAYER Metal1 ;
        RECT 0.250 1830.270 0.530 1830.520 ;
    END
  END ROW_SELECT[213]

  PIN ROW_SELECT[214]
    DIRECTION INPUT ;
    USE SIGNAL ;
    PORT
      LAYER Metal1 ;
        RECT 0.250 1838.850 0.530 1839.100 ;
    END
  END ROW_SELECT[214]

  PIN ROW_SELECT[215]
    DIRECTION INPUT ;
    USE SIGNAL ;
    PORT
      LAYER Metal1 ;
        RECT 0.250 1847.430 0.530 1847.680 ;
    END
  END ROW_SELECT[215]

  PIN ROW_SELECT[216]
    DIRECTION INPUT ;
    USE SIGNAL ;
    PORT
      LAYER Metal1 ;
        RECT 0.250 1856.010 0.530 1856.260 ;
    END
  END ROW_SELECT[216]

  PIN ROW_SELECT[217]
    DIRECTION INPUT ;
    USE SIGNAL ;
    PORT
      LAYER Metal1 ;
        RECT 0.250 1864.590 0.530 1864.840 ;
    END
  END ROW_SELECT[217]

  PIN ROW_SELECT[218]
    DIRECTION INPUT ;
    USE SIGNAL ;
    PORT
      LAYER Metal1 ;
        RECT 0.250 1873.170 0.530 1873.420 ;
    END
  END ROW_SELECT[218]

  PIN ROW_SELECT[219]
    DIRECTION INPUT ;
    USE SIGNAL ;
    PORT
      LAYER Metal1 ;
        RECT 0.250 1881.750 0.530 1882.000 ;
    END
  END ROW_SELECT[219]

  PIN ROW_SELECT[220]
    DIRECTION INPUT ;
    USE SIGNAL ;
    PORT
      LAYER Metal1 ;
        RECT 0.250 1890.330 0.530 1890.580 ;
    END
  END ROW_SELECT[220]

  PIN ROW_SELECT[221]
    DIRECTION INPUT ;
    USE SIGNAL ;
    PORT
      LAYER Metal1 ;
        RECT 0.250 1898.910 0.530 1899.160 ;
    END
  END ROW_SELECT[221]

  PIN ROW_SELECT[222]
    DIRECTION INPUT ;
    USE SIGNAL ;
    PORT
      LAYER Metal1 ;
        RECT 0.250 1907.490 0.530 1907.740 ;
    END
  END ROW_SELECT[222]

  PIN ROW_SELECT[223]
    DIRECTION INPUT ;
    USE SIGNAL ;
    PORT
      LAYER Metal1 ;
        RECT 0.250 1916.070 0.530 1916.320 ;
    END
  END ROW_SELECT[223]

  PIN ROW_SELECT[224]
    DIRECTION INPUT ;
    USE SIGNAL ;
    PORT
      LAYER Metal1 ;
        RECT 0.250 1924.650 0.530 1924.900 ;
    END
  END ROW_SELECT[224]

  PIN ROW_SELECT[225]
    DIRECTION INPUT ;
    USE SIGNAL ;
    PORT
      LAYER Metal1 ;
        RECT 0.250 1933.230 0.530 1933.480 ;
    END
  END ROW_SELECT[225]

  PIN ROW_SELECT[226]
    DIRECTION INPUT ;
    USE SIGNAL ;
    PORT
      LAYER Metal1 ;
        RECT 0.250 1941.810 0.530 1942.060 ;
    END
  END ROW_SELECT[226]

  PIN ROW_SELECT[227]
    DIRECTION INPUT ;
    USE SIGNAL ;
    PORT
      LAYER Metal1 ;
        RECT 0.250 1950.390 0.530 1950.640 ;
    END
  END ROW_SELECT[227]

  PIN ROW_SELECT[228]
    DIRECTION INPUT ;
    USE SIGNAL ;
    PORT
      LAYER Metal1 ;
        RECT 0.250 1958.970 0.530 1959.220 ;
    END
  END ROW_SELECT[228]

  PIN ROW_SELECT[229]
    DIRECTION INPUT ;
    USE SIGNAL ;
    PORT
      LAYER Metal1 ;
        RECT 0.250 1967.550 0.530 1967.800 ;
    END
  END ROW_SELECT[229]

  PIN ROW_SELECT[230]
    DIRECTION INPUT ;
    USE SIGNAL ;
    PORT
      LAYER Metal1 ;
        RECT 0.250 1976.130 0.530 1976.380 ;
    END
  END ROW_SELECT[230]

  PIN ROW_SELECT[231]
    DIRECTION INPUT ;
    USE SIGNAL ;
    PORT
      LAYER Metal1 ;
        RECT 0.250 1984.710 0.530 1984.960 ;
    END
  END ROW_SELECT[231]

  PIN ROW_SELECT[232]
    DIRECTION INPUT ;
    USE SIGNAL ;
    PORT
      LAYER Metal1 ;
        RECT 0.250 1993.290 0.530 1993.540 ;
    END
  END ROW_SELECT[232]

  PIN ROW_SELECT[233]
    DIRECTION INPUT ;
    USE SIGNAL ;
    PORT
      LAYER Metal1 ;
        RECT 0.250 2001.870 0.530 2002.120 ;
    END
  END ROW_SELECT[233]

  PIN ROW_SELECT[234]
    DIRECTION INPUT ;
    USE SIGNAL ;
    PORT
      LAYER Metal1 ;
        RECT 0.250 2010.450 0.530 2010.700 ;
    END
  END ROW_SELECT[234]

  PIN ROW_SELECT[235]
    DIRECTION INPUT ;
    USE SIGNAL ;
    PORT
      LAYER Metal1 ;
        RECT 0.250 2019.030 0.530 2019.280 ;
    END
  END ROW_SELECT[235]

  PIN ROW_SELECT[236]
    DIRECTION INPUT ;
    USE SIGNAL ;
    PORT
      LAYER Metal1 ;
        RECT 0.250 2027.610 0.530 2027.860 ;
    END
  END ROW_SELECT[236]

  PIN ROW_SELECT[237]
    DIRECTION INPUT ;
    USE SIGNAL ;
    PORT
      LAYER Metal1 ;
        RECT 0.250 2036.190 0.530 2036.440 ;
    END
  END ROW_SELECT[237]

  PIN ROW_SELECT[238]
    DIRECTION INPUT ;
    USE SIGNAL ;
    PORT
      LAYER Metal1 ;
        RECT 0.250 2044.770 0.530 2045.020 ;
    END
  END ROW_SELECT[238]

  PIN ROW_SELECT[239]
    DIRECTION INPUT ;
    USE SIGNAL ;
    PORT
      LAYER Metal1 ;
        RECT 0.250 2053.350 0.530 2053.600 ;
    END
  END ROW_SELECT[239]

  PIN RESET[0]
    DIRECTION INPUT ;
    USE SIGNAL ;
    PORT
      LAYER Metal1 ;
        RECT 0.250 10.450 0.530 10.700 ;
    END
  END RESET[0]

  PIN RESET[1]
    DIRECTION INPUT ;
    USE SIGNAL ;
    PORT
      LAYER Metal1 ;
        RECT 0.250 19.030 0.530 19.280 ;
    END
  END RESET[1]

  PIN RESET[2]
    DIRECTION INPUT ;
    USE SIGNAL ;
    PORT
      LAYER Metal1 ;
        RECT 0.250 27.610 0.530 27.860 ;
    END
  END RESET[2]

  PIN RESET[3]
    DIRECTION INPUT ;
    USE SIGNAL ;
    PORT
      LAYER Metal1 ;
        RECT 0.250 36.190 0.530 36.440 ;
    END
  END RESET[3]

  PIN RESET[4]
    DIRECTION INPUT ;
    USE SIGNAL ;
    PORT
      LAYER Metal1 ;
        RECT 0.250 44.770 0.530 45.020 ;
    END
  END RESET[4]

  PIN RESET[5]
    DIRECTION INPUT ;
    USE SIGNAL ;
    PORT
      LAYER Metal1 ;
        RECT 0.250 53.350 0.530 53.600 ;
    END
  END RESET[5]

  PIN RESET[6]
    DIRECTION INPUT ;
    USE SIGNAL ;
    PORT
      LAYER Metal1 ;
        RECT 0.250 61.930 0.530 62.180 ;
    END
  END RESET[6]

  PIN RESET[7]
    DIRECTION INPUT ;
    USE SIGNAL ;
    PORT
      LAYER Metal1 ;
        RECT 0.250 70.510 0.530 70.760 ;
    END
  END RESET[7]

  PIN RESET[8]
    DIRECTION INPUT ;
    USE SIGNAL ;
    PORT
      LAYER Metal1 ;
        RECT 0.250 79.090 0.530 79.340 ;
    END
  END RESET[8]

  PIN RESET[9]
    DIRECTION INPUT ;
    USE SIGNAL ;
    PORT
      LAYER Metal1 ;
        RECT 0.250 87.670 0.530 87.920 ;
    END
  END RESET[9]

  PIN RESET[10]
    DIRECTION INPUT ;
    USE SIGNAL ;
    PORT
      LAYER Metal1 ;
        RECT 0.250 96.250 0.530 96.500 ;
    END
  END RESET[10]

  PIN RESET[11]
    DIRECTION INPUT ;
    USE SIGNAL ;
    PORT
      LAYER Metal1 ;
        RECT 0.250 104.830 0.530 105.080 ;
    END
  END RESET[11]

  PIN RESET[12]
    DIRECTION INPUT ;
    USE SIGNAL ;
    PORT
      LAYER Metal1 ;
        RECT 0.250 113.410 0.530 113.660 ;
    END
  END RESET[12]

  PIN RESET[13]
    DIRECTION INPUT ;
    USE SIGNAL ;
    PORT
      LAYER Metal1 ;
        RECT 0.250 121.990 0.530 122.240 ;
    END
  END RESET[13]

  PIN RESET[14]
    DIRECTION INPUT ;
    USE SIGNAL ;
    PORT
      LAYER Metal1 ;
        RECT 0.250 130.570 0.530 130.820 ;
    END
  END RESET[14]

  PIN RESET[15]
    DIRECTION INPUT ;
    USE SIGNAL ;
    PORT
      LAYER Metal1 ;
        RECT 0.250 139.150 0.530 139.400 ;
    END
  END RESET[15]

  PIN RESET[16]
    DIRECTION INPUT ;
    USE SIGNAL ;
    PORT
      LAYER Metal1 ;
        RECT 0.250 147.730 0.530 147.980 ;
    END
  END RESET[16]

  PIN RESET[17]
    DIRECTION INPUT ;
    USE SIGNAL ;
    PORT
      LAYER Metal1 ;
        RECT 0.250 156.310 0.530 156.560 ;
    END
  END RESET[17]

  PIN RESET[18]
    DIRECTION INPUT ;
    USE SIGNAL ;
    PORT
      LAYER Metal1 ;
        RECT 0.250 164.890 0.530 165.140 ;
    END
  END RESET[18]

  PIN RESET[19]
    DIRECTION INPUT ;
    USE SIGNAL ;
    PORT
      LAYER Metal1 ;
        RECT 0.250 173.470 0.530 173.720 ;
    END
  END RESET[19]

  PIN RESET[20]
    DIRECTION INPUT ;
    USE SIGNAL ;
    PORT
      LAYER Metal1 ;
        RECT 0.250 182.050 0.530 182.300 ;
    END
  END RESET[20]

  PIN RESET[21]
    DIRECTION INPUT ;
    USE SIGNAL ;
    PORT
      LAYER Metal1 ;
        RECT 0.250 190.630 0.530 190.880 ;
    END
  END RESET[21]

  PIN RESET[22]
    DIRECTION INPUT ;
    USE SIGNAL ;
    PORT
      LAYER Metal1 ;
        RECT 0.250 199.210 0.530 199.460 ;
    END
  END RESET[22]

  PIN RESET[23]
    DIRECTION INPUT ;
    USE SIGNAL ;
    PORT
      LAYER Metal1 ;
        RECT 0.250 207.790 0.530 208.040 ;
    END
  END RESET[23]

  PIN RESET[24]
    DIRECTION INPUT ;
    USE SIGNAL ;
    PORT
      LAYER Metal1 ;
        RECT 0.250 216.370 0.530 216.620 ;
    END
  END RESET[24]

  PIN RESET[25]
    DIRECTION INPUT ;
    USE SIGNAL ;
    PORT
      LAYER Metal1 ;
        RECT 0.250 224.950 0.530 225.200 ;
    END
  END RESET[25]

  PIN RESET[26]
    DIRECTION INPUT ;
    USE SIGNAL ;
    PORT
      LAYER Metal1 ;
        RECT 0.250 233.530 0.530 233.780 ;
    END
  END RESET[26]

  PIN RESET[27]
    DIRECTION INPUT ;
    USE SIGNAL ;
    PORT
      LAYER Metal1 ;
        RECT 0.250 242.110 0.530 242.360 ;
    END
  END RESET[27]

  PIN RESET[28]
    DIRECTION INPUT ;
    USE SIGNAL ;
    PORT
      LAYER Metal1 ;
        RECT 0.250 250.690 0.530 250.940 ;
    END
  END RESET[28]

  PIN RESET[29]
    DIRECTION INPUT ;
    USE SIGNAL ;
    PORT
      LAYER Metal1 ;
        RECT 0.250 259.270 0.530 259.520 ;
    END
  END RESET[29]

  PIN RESET[30]
    DIRECTION INPUT ;
    USE SIGNAL ;
    PORT
      LAYER Metal1 ;
        RECT 0.250 267.850 0.530 268.100 ;
    END
  END RESET[30]

  PIN RESET[31]
    DIRECTION INPUT ;
    USE SIGNAL ;
    PORT
      LAYER Metal1 ;
        RECT 0.250 276.430 0.530 276.680 ;
    END
  END RESET[31]

  PIN RESET[32]
    DIRECTION INPUT ;
    USE SIGNAL ;
    PORT
      LAYER Metal1 ;
        RECT 0.250 285.010 0.530 285.260 ;
    END
  END RESET[32]

  PIN RESET[33]
    DIRECTION INPUT ;
    USE SIGNAL ;
    PORT
      LAYER Metal1 ;
        RECT 0.250 293.590 0.530 293.840 ;
    END
  END RESET[33]

  PIN RESET[34]
    DIRECTION INPUT ;
    USE SIGNAL ;
    PORT
      LAYER Metal1 ;
        RECT 0.250 302.170 0.530 302.420 ;
    END
  END RESET[34]

  PIN RESET[35]
    DIRECTION INPUT ;
    USE SIGNAL ;
    PORT
      LAYER Metal1 ;
        RECT 0.250 310.750 0.530 311.000 ;
    END
  END RESET[35]

  PIN RESET[36]
    DIRECTION INPUT ;
    USE SIGNAL ;
    PORT
      LAYER Metal1 ;
        RECT 0.250 319.330 0.530 319.580 ;
    END
  END RESET[36]

  PIN RESET[37]
    DIRECTION INPUT ;
    USE SIGNAL ;
    PORT
      LAYER Metal1 ;
        RECT 0.250 327.910 0.530 328.160 ;
    END
  END RESET[37]

  PIN RESET[38]
    DIRECTION INPUT ;
    USE SIGNAL ;
    PORT
      LAYER Metal1 ;
        RECT 0.250 336.490 0.530 336.740 ;
    END
  END RESET[38]

  PIN RESET[39]
    DIRECTION INPUT ;
    USE SIGNAL ;
    PORT
      LAYER Metal1 ;
        RECT 0.250 345.070 0.530 345.320 ;
    END
  END RESET[39]

  PIN RESET[40]
    DIRECTION INPUT ;
    USE SIGNAL ;
    PORT
      LAYER Metal1 ;
        RECT 0.250 353.650 0.530 353.900 ;
    END
  END RESET[40]

  PIN RESET[41]
    DIRECTION INPUT ;
    USE SIGNAL ;
    PORT
      LAYER Metal1 ;
        RECT 0.250 362.230 0.530 362.480 ;
    END
  END RESET[41]

  PIN RESET[42]
    DIRECTION INPUT ;
    USE SIGNAL ;
    PORT
      LAYER Metal1 ;
        RECT 0.250 370.810 0.530 371.060 ;
    END
  END RESET[42]

  PIN RESET[43]
    DIRECTION INPUT ;
    USE SIGNAL ;
    PORT
      LAYER Metal1 ;
        RECT 0.250 379.390 0.530 379.640 ;
    END
  END RESET[43]

  PIN RESET[44]
    DIRECTION INPUT ;
    USE SIGNAL ;
    PORT
      LAYER Metal1 ;
        RECT 0.250 387.970 0.530 388.220 ;
    END
  END RESET[44]

  PIN RESET[45]
    DIRECTION INPUT ;
    USE SIGNAL ;
    PORT
      LAYER Metal1 ;
        RECT 0.250 396.550 0.530 396.800 ;
    END
  END RESET[45]

  PIN RESET[46]
    DIRECTION INPUT ;
    USE SIGNAL ;
    PORT
      LAYER Metal1 ;
        RECT 0.250 405.130 0.530 405.380 ;
    END
  END RESET[46]

  PIN RESET[47]
    DIRECTION INPUT ;
    USE SIGNAL ;
    PORT
      LAYER Metal1 ;
        RECT 0.250 413.710 0.530 413.960 ;
    END
  END RESET[47]

  PIN RESET[48]
    DIRECTION INPUT ;
    USE SIGNAL ;
    PORT
      LAYER Metal1 ;
        RECT 0.250 422.290 0.530 422.540 ;
    END
  END RESET[48]

  PIN RESET[49]
    DIRECTION INPUT ;
    USE SIGNAL ;
    PORT
      LAYER Metal1 ;
        RECT 0.250 430.870 0.530 431.120 ;
    END
  END RESET[49]

  PIN RESET[50]
    DIRECTION INPUT ;
    USE SIGNAL ;
    PORT
      LAYER Metal1 ;
        RECT 0.250 439.450 0.530 439.700 ;
    END
  END RESET[50]

  PIN RESET[51]
    DIRECTION INPUT ;
    USE SIGNAL ;
    PORT
      LAYER Metal1 ;
        RECT 0.250 448.030 0.530 448.280 ;
    END
  END RESET[51]

  PIN RESET[52]
    DIRECTION INPUT ;
    USE SIGNAL ;
    PORT
      LAYER Metal1 ;
        RECT 0.250 456.610 0.530 456.860 ;
    END
  END RESET[52]

  PIN RESET[53]
    DIRECTION INPUT ;
    USE SIGNAL ;
    PORT
      LAYER Metal1 ;
        RECT 0.250 465.190 0.530 465.440 ;
    END
  END RESET[53]

  PIN RESET[54]
    DIRECTION INPUT ;
    USE SIGNAL ;
    PORT
      LAYER Metal1 ;
        RECT 0.250 473.770 0.530 474.020 ;
    END
  END RESET[54]

  PIN RESET[55]
    DIRECTION INPUT ;
    USE SIGNAL ;
    PORT
      LAYER Metal1 ;
        RECT 0.250 482.350 0.530 482.600 ;
    END
  END RESET[55]

  PIN RESET[56]
    DIRECTION INPUT ;
    USE SIGNAL ;
    PORT
      LAYER Metal1 ;
        RECT 0.250 490.930 0.530 491.180 ;
    END
  END RESET[56]

  PIN RESET[57]
    DIRECTION INPUT ;
    USE SIGNAL ;
    PORT
      LAYER Metal1 ;
        RECT 0.250 499.510 0.530 499.760 ;
    END
  END RESET[57]

  PIN RESET[58]
    DIRECTION INPUT ;
    USE SIGNAL ;
    PORT
      LAYER Metal1 ;
        RECT 0.250 508.090 0.530 508.340 ;
    END
  END RESET[58]

  PIN RESET[59]
    DIRECTION INPUT ;
    USE SIGNAL ;
    PORT
      LAYER Metal1 ;
        RECT 0.250 516.670 0.530 516.920 ;
    END
  END RESET[59]

  PIN RESET[60]
    DIRECTION INPUT ;
    USE SIGNAL ;
    PORT
      LAYER Metal1 ;
        RECT 0.250 525.250 0.530 525.500 ;
    END
  END RESET[60]

  PIN RESET[61]
    DIRECTION INPUT ;
    USE SIGNAL ;
    PORT
      LAYER Metal1 ;
        RECT 0.250 533.830 0.530 534.080 ;
    END
  END RESET[61]

  PIN RESET[62]
    DIRECTION INPUT ;
    USE SIGNAL ;
    PORT
      LAYER Metal1 ;
        RECT 0.250 542.410 0.530 542.660 ;
    END
  END RESET[62]

  PIN RESET[63]
    DIRECTION INPUT ;
    USE SIGNAL ;
    PORT
      LAYER Metal1 ;
        RECT 0.250 550.990 0.530 551.240 ;
    END
  END RESET[63]

  PIN RESET[64]
    DIRECTION INPUT ;
    USE SIGNAL ;
    PORT
      LAYER Metal1 ;
        RECT 0.250 559.570 0.530 559.820 ;
    END
  END RESET[64]

  PIN RESET[65]
    DIRECTION INPUT ;
    USE SIGNAL ;
    PORT
      LAYER Metal1 ;
        RECT 0.250 568.150 0.530 568.400 ;
    END
  END RESET[65]

  PIN RESET[66]
    DIRECTION INPUT ;
    USE SIGNAL ;
    PORT
      LAYER Metal1 ;
        RECT 0.250 576.730 0.530 576.980 ;
    END
  END RESET[66]

  PIN RESET[67]
    DIRECTION INPUT ;
    USE SIGNAL ;
    PORT
      LAYER Metal1 ;
        RECT 0.250 585.310 0.530 585.560 ;
    END
  END RESET[67]

  PIN RESET[68]
    DIRECTION INPUT ;
    USE SIGNAL ;
    PORT
      LAYER Metal1 ;
        RECT 0.250 593.890 0.530 594.140 ;
    END
  END RESET[68]

  PIN RESET[69]
    DIRECTION INPUT ;
    USE SIGNAL ;
    PORT
      LAYER Metal1 ;
        RECT 0.250 602.470 0.530 602.720 ;
    END
  END RESET[69]

  PIN RESET[70]
    DIRECTION INPUT ;
    USE SIGNAL ;
    PORT
      LAYER Metal1 ;
        RECT 0.250 611.050 0.530 611.300 ;
    END
  END RESET[70]

  PIN RESET[71]
    DIRECTION INPUT ;
    USE SIGNAL ;
    PORT
      LAYER Metal1 ;
        RECT 0.250 619.630 0.530 619.880 ;
    END
  END RESET[71]

  PIN RESET[72]
    DIRECTION INPUT ;
    USE SIGNAL ;
    PORT
      LAYER Metal1 ;
        RECT 0.250 628.210 0.530 628.460 ;
    END
  END RESET[72]

  PIN RESET[73]
    DIRECTION INPUT ;
    USE SIGNAL ;
    PORT
      LAYER Metal1 ;
        RECT 0.250 636.790 0.530 637.040 ;
    END
  END RESET[73]

  PIN RESET[74]
    DIRECTION INPUT ;
    USE SIGNAL ;
    PORT
      LAYER Metal1 ;
        RECT 0.250 645.370 0.530 645.620 ;
    END
  END RESET[74]

  PIN RESET[75]
    DIRECTION INPUT ;
    USE SIGNAL ;
    PORT
      LAYER Metal1 ;
        RECT 0.250 653.950 0.530 654.200 ;
    END
  END RESET[75]

  PIN RESET[76]
    DIRECTION INPUT ;
    USE SIGNAL ;
    PORT
      LAYER Metal1 ;
        RECT 0.250 662.530 0.530 662.780 ;
    END
  END RESET[76]

  PIN RESET[77]
    DIRECTION INPUT ;
    USE SIGNAL ;
    PORT
      LAYER Metal1 ;
        RECT 0.250 671.110 0.530 671.360 ;
    END
  END RESET[77]

  PIN RESET[78]
    DIRECTION INPUT ;
    USE SIGNAL ;
    PORT
      LAYER Metal1 ;
        RECT 0.250 679.690 0.530 679.940 ;
    END
  END RESET[78]

  PIN RESET[79]
    DIRECTION INPUT ;
    USE SIGNAL ;
    PORT
      LAYER Metal1 ;
        RECT 0.250 688.270 0.530 688.520 ;
    END
  END RESET[79]

  PIN RESET[80]
    DIRECTION INPUT ;
    USE SIGNAL ;
    PORT
      LAYER Metal1 ;
        RECT 0.250 696.850 0.530 697.100 ;
    END
  END RESET[80]

  PIN RESET[81]
    DIRECTION INPUT ;
    USE SIGNAL ;
    PORT
      LAYER Metal1 ;
        RECT 0.250 705.430 0.530 705.680 ;
    END
  END RESET[81]

  PIN RESET[82]
    DIRECTION INPUT ;
    USE SIGNAL ;
    PORT
      LAYER Metal1 ;
        RECT 0.250 714.010 0.530 714.260 ;
    END
  END RESET[82]

  PIN RESET[83]
    DIRECTION INPUT ;
    USE SIGNAL ;
    PORT
      LAYER Metal1 ;
        RECT 0.250 722.590 0.530 722.840 ;
    END
  END RESET[83]

  PIN RESET[84]
    DIRECTION INPUT ;
    USE SIGNAL ;
    PORT
      LAYER Metal1 ;
        RECT 0.250 731.170 0.530 731.420 ;
    END
  END RESET[84]

  PIN RESET[85]
    DIRECTION INPUT ;
    USE SIGNAL ;
    PORT
      LAYER Metal1 ;
        RECT 0.250 739.750 0.530 740.000 ;
    END
  END RESET[85]

  PIN RESET[86]
    DIRECTION INPUT ;
    USE SIGNAL ;
    PORT
      LAYER Metal1 ;
        RECT 0.250 748.330 0.530 748.580 ;
    END
  END RESET[86]

  PIN RESET[87]
    DIRECTION INPUT ;
    USE SIGNAL ;
    PORT
      LAYER Metal1 ;
        RECT 0.250 756.910 0.530 757.160 ;
    END
  END RESET[87]

  PIN RESET[88]
    DIRECTION INPUT ;
    USE SIGNAL ;
    PORT
      LAYER Metal1 ;
        RECT 0.250 765.490 0.530 765.740 ;
    END
  END RESET[88]

  PIN RESET[89]
    DIRECTION INPUT ;
    USE SIGNAL ;
    PORT
      LAYER Metal1 ;
        RECT 0.250 774.070 0.530 774.320 ;
    END
  END RESET[89]

  PIN RESET[90]
    DIRECTION INPUT ;
    USE SIGNAL ;
    PORT
      LAYER Metal1 ;
        RECT 0.250 782.650 0.530 782.900 ;
    END
  END RESET[90]

  PIN RESET[91]
    DIRECTION INPUT ;
    USE SIGNAL ;
    PORT
      LAYER Metal1 ;
        RECT 0.250 791.230 0.530 791.480 ;
    END
  END RESET[91]

  PIN RESET[92]
    DIRECTION INPUT ;
    USE SIGNAL ;
    PORT
      LAYER Metal1 ;
        RECT 0.250 799.810 0.530 800.060 ;
    END
  END RESET[92]

  PIN RESET[93]
    DIRECTION INPUT ;
    USE SIGNAL ;
    PORT
      LAYER Metal1 ;
        RECT 0.250 808.390 0.530 808.640 ;
    END
  END RESET[93]

  PIN RESET[94]
    DIRECTION INPUT ;
    USE SIGNAL ;
    PORT
      LAYER Metal1 ;
        RECT 0.250 816.970 0.530 817.220 ;
    END
  END RESET[94]

  PIN RESET[95]
    DIRECTION INPUT ;
    USE SIGNAL ;
    PORT
      LAYER Metal1 ;
        RECT 0.250 825.550 0.530 825.800 ;
    END
  END RESET[95]

  PIN RESET[96]
    DIRECTION INPUT ;
    USE SIGNAL ;
    PORT
      LAYER Metal1 ;
        RECT 0.250 834.130 0.530 834.380 ;
    END
  END RESET[96]

  PIN RESET[97]
    DIRECTION INPUT ;
    USE SIGNAL ;
    PORT
      LAYER Metal1 ;
        RECT 0.250 842.710 0.530 842.960 ;
    END
  END RESET[97]

  PIN RESET[98]
    DIRECTION INPUT ;
    USE SIGNAL ;
    PORT
      LAYER Metal1 ;
        RECT 0.250 851.290 0.530 851.540 ;
    END
  END RESET[98]

  PIN RESET[99]
    DIRECTION INPUT ;
    USE SIGNAL ;
    PORT
      LAYER Metal1 ;
        RECT 0.250 859.870 0.530 860.120 ;
    END
  END RESET[99]

  PIN RESET[100]
    DIRECTION INPUT ;
    USE SIGNAL ;
    PORT
      LAYER Metal1 ;
        RECT 0.250 868.450 0.530 868.700 ;
    END
  END RESET[100]

  PIN RESET[101]
    DIRECTION INPUT ;
    USE SIGNAL ;
    PORT
      LAYER Metal1 ;
        RECT 0.250 877.030 0.530 877.280 ;
    END
  END RESET[101]

  PIN RESET[102]
    DIRECTION INPUT ;
    USE SIGNAL ;
    PORT
      LAYER Metal1 ;
        RECT 0.250 885.610 0.530 885.860 ;
    END
  END RESET[102]

  PIN RESET[103]
    DIRECTION INPUT ;
    USE SIGNAL ;
    PORT
      LAYER Metal1 ;
        RECT 0.250 894.190 0.530 894.440 ;
    END
  END RESET[103]

  PIN RESET[104]
    DIRECTION INPUT ;
    USE SIGNAL ;
    PORT
      LAYER Metal1 ;
        RECT 0.250 902.770 0.530 903.020 ;
    END
  END RESET[104]

  PIN RESET[105]
    DIRECTION INPUT ;
    USE SIGNAL ;
    PORT
      LAYER Metal1 ;
        RECT 0.250 911.350 0.530 911.600 ;
    END
  END RESET[105]

  PIN RESET[106]
    DIRECTION INPUT ;
    USE SIGNAL ;
    PORT
      LAYER Metal1 ;
        RECT 0.250 919.930 0.530 920.180 ;
    END
  END RESET[106]

  PIN RESET[107]
    DIRECTION INPUT ;
    USE SIGNAL ;
    PORT
      LAYER Metal1 ;
        RECT 0.250 928.510 0.530 928.760 ;
    END
  END RESET[107]

  PIN RESET[108]
    DIRECTION INPUT ;
    USE SIGNAL ;
    PORT
      LAYER Metal1 ;
        RECT 0.250 937.090 0.530 937.340 ;
    END
  END RESET[108]

  PIN RESET[109]
    DIRECTION INPUT ;
    USE SIGNAL ;
    PORT
      LAYER Metal1 ;
        RECT 0.250 945.670 0.530 945.920 ;
    END
  END RESET[109]

  PIN RESET[110]
    DIRECTION INPUT ;
    USE SIGNAL ;
    PORT
      LAYER Metal1 ;
        RECT 0.250 954.250 0.530 954.500 ;
    END
  END RESET[110]

  PIN RESET[111]
    DIRECTION INPUT ;
    USE SIGNAL ;
    PORT
      LAYER Metal1 ;
        RECT 0.250 962.830 0.530 963.080 ;
    END
  END RESET[111]

  PIN RESET[112]
    DIRECTION INPUT ;
    USE SIGNAL ;
    PORT
      LAYER Metal1 ;
        RECT 0.250 971.410 0.530 971.660 ;
    END
  END RESET[112]

  PIN RESET[113]
    DIRECTION INPUT ;
    USE SIGNAL ;
    PORT
      LAYER Metal1 ;
        RECT 0.250 979.990 0.530 980.240 ;
    END
  END RESET[113]

  PIN RESET[114]
    DIRECTION INPUT ;
    USE SIGNAL ;
    PORT
      LAYER Metal1 ;
        RECT 0.250 988.570 0.530 988.820 ;
    END
  END RESET[114]

  PIN RESET[115]
    DIRECTION INPUT ;
    USE SIGNAL ;
    PORT
      LAYER Metal1 ;
        RECT 0.250 997.150 0.530 997.400 ;
    END
  END RESET[115]

  PIN RESET[116]
    DIRECTION INPUT ;
    USE SIGNAL ;
    PORT
      LAYER Metal1 ;
        RECT 0.250 1005.730 0.530 1005.980 ;
    END
  END RESET[116]

  PIN RESET[117]
    DIRECTION INPUT ;
    USE SIGNAL ;
    PORT
      LAYER Metal1 ;
        RECT 0.250 1014.310 0.530 1014.560 ;
    END
  END RESET[117]

  PIN RESET[118]
    DIRECTION INPUT ;
    USE SIGNAL ;
    PORT
      LAYER Metal1 ;
        RECT 0.250 1022.890 0.530 1023.140 ;
    END
  END RESET[118]

  PIN RESET[119]
    DIRECTION INPUT ;
    USE SIGNAL ;
    PORT
      LAYER Metal1 ;
        RECT 0.250 1031.470 0.530 1031.720 ;
    END
  END RESET[119]

  PIN RESET[120]
    DIRECTION INPUT ;
    USE SIGNAL ;
    PORT
      LAYER Metal1 ;
        RECT 0.250 1040.050 0.530 1040.300 ;
    END
  END RESET[120]

  PIN RESET[121]
    DIRECTION INPUT ;
    USE SIGNAL ;
    PORT
      LAYER Metal1 ;
        RECT 0.250 1048.630 0.530 1048.880 ;
    END
  END RESET[121]

  PIN RESET[122]
    DIRECTION INPUT ;
    USE SIGNAL ;
    PORT
      LAYER Metal1 ;
        RECT 0.250 1057.210 0.530 1057.460 ;
    END
  END RESET[122]

  PIN RESET[123]
    DIRECTION INPUT ;
    USE SIGNAL ;
    PORT
      LAYER Metal1 ;
        RECT 0.250 1065.790 0.530 1066.040 ;
    END
  END RESET[123]

  PIN RESET[124]
    DIRECTION INPUT ;
    USE SIGNAL ;
    PORT
      LAYER Metal1 ;
        RECT 0.250 1074.370 0.530 1074.620 ;
    END
  END RESET[124]

  PIN RESET[125]
    DIRECTION INPUT ;
    USE SIGNAL ;
    PORT
      LAYER Metal1 ;
        RECT 0.250 1082.950 0.530 1083.200 ;
    END
  END RESET[125]

  PIN RESET[126]
    DIRECTION INPUT ;
    USE SIGNAL ;
    PORT
      LAYER Metal1 ;
        RECT 0.250 1091.530 0.530 1091.780 ;
    END
  END RESET[126]

  PIN RESET[127]
    DIRECTION INPUT ;
    USE SIGNAL ;
    PORT
      LAYER Metal1 ;
        RECT 0.250 1100.110 0.530 1100.360 ;
    END
  END RESET[127]

  PIN RESET[128]
    DIRECTION INPUT ;
    USE SIGNAL ;
    PORT
      LAYER Metal1 ;
        RECT 0.250 1108.690 0.530 1108.940 ;
    END
  END RESET[128]

  PIN RESET[129]
    DIRECTION INPUT ;
    USE SIGNAL ;
    PORT
      LAYER Metal1 ;
        RECT 0.250 1117.270 0.530 1117.520 ;
    END
  END RESET[129]

  PIN RESET[130]
    DIRECTION INPUT ;
    USE SIGNAL ;
    PORT
      LAYER Metal1 ;
        RECT 0.250 1125.850 0.530 1126.100 ;
    END
  END RESET[130]

  PIN RESET[131]
    DIRECTION INPUT ;
    USE SIGNAL ;
    PORT
      LAYER Metal1 ;
        RECT 0.250 1134.430 0.530 1134.680 ;
    END
  END RESET[131]

  PIN RESET[132]
    DIRECTION INPUT ;
    USE SIGNAL ;
    PORT
      LAYER Metal1 ;
        RECT 0.250 1143.010 0.530 1143.260 ;
    END
  END RESET[132]

  PIN RESET[133]
    DIRECTION INPUT ;
    USE SIGNAL ;
    PORT
      LAYER Metal1 ;
        RECT 0.250 1151.590 0.530 1151.840 ;
    END
  END RESET[133]

  PIN RESET[134]
    DIRECTION INPUT ;
    USE SIGNAL ;
    PORT
      LAYER Metal1 ;
        RECT 0.250 1160.170 0.530 1160.420 ;
    END
  END RESET[134]

  PIN RESET[135]
    DIRECTION INPUT ;
    USE SIGNAL ;
    PORT
      LAYER Metal1 ;
        RECT 0.250 1168.750 0.530 1169.000 ;
    END
  END RESET[135]

  PIN RESET[136]
    DIRECTION INPUT ;
    USE SIGNAL ;
    PORT
      LAYER Metal1 ;
        RECT 0.250 1177.330 0.530 1177.580 ;
    END
  END RESET[136]

  PIN RESET[137]
    DIRECTION INPUT ;
    USE SIGNAL ;
    PORT
      LAYER Metal1 ;
        RECT 0.250 1185.910 0.530 1186.160 ;
    END
  END RESET[137]

  PIN RESET[138]
    DIRECTION INPUT ;
    USE SIGNAL ;
    PORT
      LAYER Metal1 ;
        RECT 0.250 1194.490 0.530 1194.740 ;
    END
  END RESET[138]

  PIN RESET[139]
    DIRECTION INPUT ;
    USE SIGNAL ;
    PORT
      LAYER Metal1 ;
        RECT 0.250 1203.070 0.530 1203.320 ;
    END
  END RESET[139]

  PIN RESET[140]
    DIRECTION INPUT ;
    USE SIGNAL ;
    PORT
      LAYER Metal1 ;
        RECT 0.250 1211.650 0.530 1211.900 ;
    END
  END RESET[140]

  PIN RESET[141]
    DIRECTION INPUT ;
    USE SIGNAL ;
    PORT
      LAYER Metal1 ;
        RECT 0.250 1220.230 0.530 1220.480 ;
    END
  END RESET[141]

  PIN RESET[142]
    DIRECTION INPUT ;
    USE SIGNAL ;
    PORT
      LAYER Metal1 ;
        RECT 0.250 1228.810 0.530 1229.060 ;
    END
  END RESET[142]

  PIN RESET[143]
    DIRECTION INPUT ;
    USE SIGNAL ;
    PORT
      LAYER Metal1 ;
        RECT 0.250 1237.390 0.530 1237.640 ;
    END
  END RESET[143]

  PIN RESET[144]
    DIRECTION INPUT ;
    USE SIGNAL ;
    PORT
      LAYER Metal1 ;
        RECT 0.250 1245.970 0.530 1246.220 ;
    END
  END RESET[144]

  PIN RESET[145]
    DIRECTION INPUT ;
    USE SIGNAL ;
    PORT
      LAYER Metal1 ;
        RECT 0.250 1254.550 0.530 1254.800 ;
    END
  END RESET[145]

  PIN RESET[146]
    DIRECTION INPUT ;
    USE SIGNAL ;
    PORT
      LAYER Metal1 ;
        RECT 0.250 1263.130 0.530 1263.380 ;
    END
  END RESET[146]

  PIN RESET[147]
    DIRECTION INPUT ;
    USE SIGNAL ;
    PORT
      LAYER Metal1 ;
        RECT 0.250 1271.710 0.530 1271.960 ;
    END
  END RESET[147]

  PIN RESET[148]
    DIRECTION INPUT ;
    USE SIGNAL ;
    PORT
      LAYER Metal1 ;
        RECT 0.250 1280.290 0.530 1280.540 ;
    END
  END RESET[148]

  PIN RESET[149]
    DIRECTION INPUT ;
    USE SIGNAL ;
    PORT
      LAYER Metal1 ;
        RECT 0.250 1288.870 0.530 1289.120 ;
    END
  END RESET[149]

  PIN RESET[150]
    DIRECTION INPUT ;
    USE SIGNAL ;
    PORT
      LAYER Metal1 ;
        RECT 0.250 1297.450 0.530 1297.700 ;
    END
  END RESET[150]

  PIN RESET[151]
    DIRECTION INPUT ;
    USE SIGNAL ;
    PORT
      LAYER Metal1 ;
        RECT 0.250 1306.030 0.530 1306.280 ;
    END
  END RESET[151]

  PIN RESET[152]
    DIRECTION INPUT ;
    USE SIGNAL ;
    PORT
      LAYER Metal1 ;
        RECT 0.250 1314.610 0.530 1314.860 ;
    END
  END RESET[152]

  PIN RESET[153]
    DIRECTION INPUT ;
    USE SIGNAL ;
    PORT
      LAYER Metal1 ;
        RECT 0.250 1323.190 0.530 1323.440 ;
    END
  END RESET[153]

  PIN RESET[154]
    DIRECTION INPUT ;
    USE SIGNAL ;
    PORT
      LAYER Metal1 ;
        RECT 0.250 1331.770 0.530 1332.020 ;
    END
  END RESET[154]

  PIN RESET[155]
    DIRECTION INPUT ;
    USE SIGNAL ;
    PORT
      LAYER Metal1 ;
        RECT 0.250 1340.350 0.530 1340.600 ;
    END
  END RESET[155]

  PIN RESET[156]
    DIRECTION INPUT ;
    USE SIGNAL ;
    PORT
      LAYER Metal1 ;
        RECT 0.250 1348.930 0.530 1349.180 ;
    END
  END RESET[156]

  PIN RESET[157]
    DIRECTION INPUT ;
    USE SIGNAL ;
    PORT
      LAYER Metal1 ;
        RECT 0.250 1357.510 0.530 1357.760 ;
    END
  END RESET[157]

  PIN RESET[158]
    DIRECTION INPUT ;
    USE SIGNAL ;
    PORT
      LAYER Metal1 ;
        RECT 0.250 1366.090 0.530 1366.340 ;
    END
  END RESET[158]

  PIN RESET[159]
    DIRECTION INPUT ;
    USE SIGNAL ;
    PORT
      LAYER Metal1 ;
        RECT 0.250 1374.670 0.530 1374.920 ;
    END
  END RESET[159]

  PIN RESET[160]
    DIRECTION INPUT ;
    USE SIGNAL ;
    PORT
      LAYER Metal1 ;
        RECT 0.250 1383.250 0.530 1383.500 ;
    END
  END RESET[160]

  PIN RESET[161]
    DIRECTION INPUT ;
    USE SIGNAL ;
    PORT
      LAYER Metal1 ;
        RECT 0.250 1391.830 0.530 1392.080 ;
    END
  END RESET[161]

  PIN RESET[162]
    DIRECTION INPUT ;
    USE SIGNAL ;
    PORT
      LAYER Metal1 ;
        RECT 0.250 1400.410 0.530 1400.660 ;
    END
  END RESET[162]

  PIN RESET[163]
    DIRECTION INPUT ;
    USE SIGNAL ;
    PORT
      LAYER Metal1 ;
        RECT 0.250 1408.990 0.530 1409.240 ;
    END
  END RESET[163]

  PIN RESET[164]
    DIRECTION INPUT ;
    USE SIGNAL ;
    PORT
      LAYER Metal1 ;
        RECT 0.250 1417.570 0.530 1417.820 ;
    END
  END RESET[164]

  PIN RESET[165]
    DIRECTION INPUT ;
    USE SIGNAL ;
    PORT
      LAYER Metal1 ;
        RECT 0.250 1426.150 0.530 1426.400 ;
    END
  END RESET[165]

  PIN RESET[166]
    DIRECTION INPUT ;
    USE SIGNAL ;
    PORT
      LAYER Metal1 ;
        RECT 0.250 1434.730 0.530 1434.980 ;
    END
  END RESET[166]

  PIN RESET[167]
    DIRECTION INPUT ;
    USE SIGNAL ;
    PORT
      LAYER Metal1 ;
        RECT 0.250 1443.310 0.530 1443.560 ;
    END
  END RESET[167]

  PIN RESET[168]
    DIRECTION INPUT ;
    USE SIGNAL ;
    PORT
      LAYER Metal1 ;
        RECT 0.250 1451.890 0.530 1452.140 ;
    END
  END RESET[168]

  PIN RESET[169]
    DIRECTION INPUT ;
    USE SIGNAL ;
    PORT
      LAYER Metal1 ;
        RECT 0.250 1460.470 0.530 1460.720 ;
    END
  END RESET[169]

  PIN RESET[170]
    DIRECTION INPUT ;
    USE SIGNAL ;
    PORT
      LAYER Metal1 ;
        RECT 0.250 1469.050 0.530 1469.300 ;
    END
  END RESET[170]

  PIN RESET[171]
    DIRECTION INPUT ;
    USE SIGNAL ;
    PORT
      LAYER Metal1 ;
        RECT 0.250 1477.630 0.530 1477.880 ;
    END
  END RESET[171]

  PIN RESET[172]
    DIRECTION INPUT ;
    USE SIGNAL ;
    PORT
      LAYER Metal1 ;
        RECT 0.250 1486.210 0.530 1486.460 ;
    END
  END RESET[172]

  PIN RESET[173]
    DIRECTION INPUT ;
    USE SIGNAL ;
    PORT
      LAYER Metal1 ;
        RECT 0.250 1494.790 0.530 1495.040 ;
    END
  END RESET[173]

  PIN RESET[174]
    DIRECTION INPUT ;
    USE SIGNAL ;
    PORT
      LAYER Metal1 ;
        RECT 0.250 1503.370 0.530 1503.620 ;
    END
  END RESET[174]

  PIN RESET[175]
    DIRECTION INPUT ;
    USE SIGNAL ;
    PORT
      LAYER Metal1 ;
        RECT 0.250 1511.950 0.530 1512.200 ;
    END
  END RESET[175]

  PIN RESET[176]
    DIRECTION INPUT ;
    USE SIGNAL ;
    PORT
      LAYER Metal1 ;
        RECT 0.250 1520.530 0.530 1520.780 ;
    END
  END RESET[176]

  PIN RESET[177]
    DIRECTION INPUT ;
    USE SIGNAL ;
    PORT
      LAYER Metal1 ;
        RECT 0.250 1529.110 0.530 1529.360 ;
    END
  END RESET[177]

  PIN RESET[178]
    DIRECTION INPUT ;
    USE SIGNAL ;
    PORT
      LAYER Metal1 ;
        RECT 0.250 1537.690 0.530 1537.940 ;
    END
  END RESET[178]

  PIN RESET[179]
    DIRECTION INPUT ;
    USE SIGNAL ;
    PORT
      LAYER Metal1 ;
        RECT 0.250 1546.270 0.530 1546.520 ;
    END
  END RESET[179]

  PIN RESET[180]
    DIRECTION INPUT ;
    USE SIGNAL ;
    PORT
      LAYER Metal1 ;
        RECT 0.250 1554.850 0.530 1555.100 ;
    END
  END RESET[180]

  PIN RESET[181]
    DIRECTION INPUT ;
    USE SIGNAL ;
    PORT
      LAYER Metal1 ;
        RECT 0.250 1563.430 0.530 1563.680 ;
    END
  END RESET[181]

  PIN RESET[182]
    DIRECTION INPUT ;
    USE SIGNAL ;
    PORT
      LAYER Metal1 ;
        RECT 0.250 1572.010 0.530 1572.260 ;
    END
  END RESET[182]

  PIN RESET[183]
    DIRECTION INPUT ;
    USE SIGNAL ;
    PORT
      LAYER Metal1 ;
        RECT 0.250 1580.590 0.530 1580.840 ;
    END
  END RESET[183]

  PIN RESET[184]
    DIRECTION INPUT ;
    USE SIGNAL ;
    PORT
      LAYER Metal1 ;
        RECT 0.250 1589.170 0.530 1589.420 ;
    END
  END RESET[184]

  PIN RESET[185]
    DIRECTION INPUT ;
    USE SIGNAL ;
    PORT
      LAYER Metal1 ;
        RECT 0.250 1597.750 0.530 1598.000 ;
    END
  END RESET[185]

  PIN RESET[186]
    DIRECTION INPUT ;
    USE SIGNAL ;
    PORT
      LAYER Metal1 ;
        RECT 0.250 1606.330 0.530 1606.580 ;
    END
  END RESET[186]

  PIN RESET[187]
    DIRECTION INPUT ;
    USE SIGNAL ;
    PORT
      LAYER Metal1 ;
        RECT 0.250 1614.910 0.530 1615.160 ;
    END
  END RESET[187]

  PIN RESET[188]
    DIRECTION INPUT ;
    USE SIGNAL ;
    PORT
      LAYER Metal1 ;
        RECT 0.250 1623.490 0.530 1623.740 ;
    END
  END RESET[188]

  PIN RESET[189]
    DIRECTION INPUT ;
    USE SIGNAL ;
    PORT
      LAYER Metal1 ;
        RECT 0.250 1632.070 0.530 1632.320 ;
    END
  END RESET[189]

  PIN RESET[190]
    DIRECTION INPUT ;
    USE SIGNAL ;
    PORT
      LAYER Metal1 ;
        RECT 0.250 1640.650 0.530 1640.900 ;
    END
  END RESET[190]

  PIN RESET[191]
    DIRECTION INPUT ;
    USE SIGNAL ;
    PORT
      LAYER Metal1 ;
        RECT 0.250 1649.230 0.530 1649.480 ;
    END
  END RESET[191]

  PIN RESET[192]
    DIRECTION INPUT ;
    USE SIGNAL ;
    PORT
      LAYER Metal1 ;
        RECT 0.250 1657.810 0.530 1658.060 ;
    END
  END RESET[192]

  PIN RESET[193]
    DIRECTION INPUT ;
    USE SIGNAL ;
    PORT
      LAYER Metal1 ;
        RECT 0.250 1666.390 0.530 1666.640 ;
    END
  END RESET[193]

  PIN RESET[194]
    DIRECTION INPUT ;
    USE SIGNAL ;
    PORT
      LAYER Metal1 ;
        RECT 0.250 1674.970 0.530 1675.220 ;
    END
  END RESET[194]

  PIN RESET[195]
    DIRECTION INPUT ;
    USE SIGNAL ;
    PORT
      LAYER Metal1 ;
        RECT 0.250 1683.550 0.530 1683.800 ;
    END
  END RESET[195]

  PIN RESET[196]
    DIRECTION INPUT ;
    USE SIGNAL ;
    PORT
      LAYER Metal1 ;
        RECT 0.250 1692.130 0.530 1692.380 ;
    END
  END RESET[196]

  PIN RESET[197]
    DIRECTION INPUT ;
    USE SIGNAL ;
    PORT
      LAYER Metal1 ;
        RECT 0.250 1700.710 0.530 1700.960 ;
    END
  END RESET[197]

  PIN RESET[198]
    DIRECTION INPUT ;
    USE SIGNAL ;
    PORT
      LAYER Metal1 ;
        RECT 0.250 1709.290 0.530 1709.540 ;
    END
  END RESET[198]

  PIN RESET[199]
    DIRECTION INPUT ;
    USE SIGNAL ;
    PORT
      LAYER Metal1 ;
        RECT 0.250 1717.870 0.530 1718.120 ;
    END
  END RESET[199]

  PIN RESET[200]
    DIRECTION INPUT ;
    USE SIGNAL ;
    PORT
      LAYER Metal1 ;
        RECT 0.250 1726.450 0.530 1726.700 ;
    END
  END RESET[200]

  PIN RESET[201]
    DIRECTION INPUT ;
    USE SIGNAL ;
    PORT
      LAYER Metal1 ;
        RECT 0.250 1735.030 0.530 1735.280 ;
    END
  END RESET[201]

  PIN RESET[202]
    DIRECTION INPUT ;
    USE SIGNAL ;
    PORT
      LAYER Metal1 ;
        RECT 0.250 1743.610 0.530 1743.860 ;
    END
  END RESET[202]

  PIN RESET[203]
    DIRECTION INPUT ;
    USE SIGNAL ;
    PORT
      LAYER Metal1 ;
        RECT 0.250 1752.190 0.530 1752.440 ;
    END
  END RESET[203]

  PIN RESET[204]
    DIRECTION INPUT ;
    USE SIGNAL ;
    PORT
      LAYER Metal1 ;
        RECT 0.250 1760.770 0.530 1761.020 ;
    END
  END RESET[204]

  PIN RESET[205]
    DIRECTION INPUT ;
    USE SIGNAL ;
    PORT
      LAYER Metal1 ;
        RECT 0.250 1769.350 0.530 1769.600 ;
    END
  END RESET[205]

  PIN RESET[206]
    DIRECTION INPUT ;
    USE SIGNAL ;
    PORT
      LAYER Metal1 ;
        RECT 0.250 1777.930 0.530 1778.180 ;
    END
  END RESET[206]

  PIN RESET[207]
    DIRECTION INPUT ;
    USE SIGNAL ;
    PORT
      LAYER Metal1 ;
        RECT 0.250 1786.510 0.530 1786.760 ;
    END
  END RESET[207]

  PIN RESET[208]
    DIRECTION INPUT ;
    USE SIGNAL ;
    PORT
      LAYER Metal1 ;
        RECT 0.250 1795.090 0.530 1795.340 ;
    END
  END RESET[208]

  PIN RESET[209]
    DIRECTION INPUT ;
    USE SIGNAL ;
    PORT
      LAYER Metal1 ;
        RECT 0.250 1803.670 0.530 1803.920 ;
    END
  END RESET[209]

  PIN RESET[210]
    DIRECTION INPUT ;
    USE SIGNAL ;
    PORT
      LAYER Metal1 ;
        RECT 0.250 1812.250 0.530 1812.500 ;
    END
  END RESET[210]

  PIN RESET[211]
    DIRECTION INPUT ;
    USE SIGNAL ;
    PORT
      LAYER Metal1 ;
        RECT 0.250 1820.830 0.530 1821.080 ;
    END
  END RESET[211]

  PIN RESET[212]
    DIRECTION INPUT ;
    USE SIGNAL ;
    PORT
      LAYER Metal1 ;
        RECT 0.250 1829.410 0.530 1829.660 ;
    END
  END RESET[212]

  PIN RESET[213]
    DIRECTION INPUT ;
    USE SIGNAL ;
    PORT
      LAYER Metal1 ;
        RECT 0.250 1837.990 0.530 1838.240 ;
    END
  END RESET[213]

  PIN RESET[214]
    DIRECTION INPUT ;
    USE SIGNAL ;
    PORT
      LAYER Metal1 ;
        RECT 0.250 1846.570 0.530 1846.820 ;
    END
  END RESET[214]

  PIN RESET[215]
    DIRECTION INPUT ;
    USE SIGNAL ;
    PORT
      LAYER Metal1 ;
        RECT 0.250 1855.150 0.530 1855.400 ;
    END
  END RESET[215]

  PIN RESET[216]
    DIRECTION INPUT ;
    USE SIGNAL ;
    PORT
      LAYER Metal1 ;
        RECT 0.250 1863.730 0.530 1863.980 ;
    END
  END RESET[216]

  PIN RESET[217]
    DIRECTION INPUT ;
    USE SIGNAL ;
    PORT
      LAYER Metal1 ;
        RECT 0.250 1872.310 0.530 1872.560 ;
    END
  END RESET[217]

  PIN RESET[218]
    DIRECTION INPUT ;
    USE SIGNAL ;
    PORT
      LAYER Metal1 ;
        RECT 0.250 1880.890 0.530 1881.140 ;
    END
  END RESET[218]

  PIN RESET[219]
    DIRECTION INPUT ;
    USE SIGNAL ;
    PORT
      LAYER Metal1 ;
        RECT 0.250 1889.470 0.530 1889.720 ;
    END
  END RESET[219]

  PIN RESET[220]
    DIRECTION INPUT ;
    USE SIGNAL ;
    PORT
      LAYER Metal1 ;
        RECT 0.250 1898.050 0.530 1898.300 ;
    END
  END RESET[220]

  PIN RESET[221]
    DIRECTION INPUT ;
    USE SIGNAL ;
    PORT
      LAYER Metal1 ;
        RECT 0.250 1906.630 0.530 1906.880 ;
    END
  END RESET[221]

  PIN RESET[222]
    DIRECTION INPUT ;
    USE SIGNAL ;
    PORT
      LAYER Metal1 ;
        RECT 0.250 1915.210 0.530 1915.460 ;
    END
  END RESET[222]

  PIN RESET[223]
    DIRECTION INPUT ;
    USE SIGNAL ;
    PORT
      LAYER Metal1 ;
        RECT 0.250 1923.790 0.530 1924.040 ;
    END
  END RESET[223]

  PIN RESET[224]
    DIRECTION INPUT ;
    USE SIGNAL ;
    PORT
      LAYER Metal1 ;
        RECT 0.250 1932.370 0.530 1932.620 ;
    END
  END RESET[224]

  PIN RESET[225]
    DIRECTION INPUT ;
    USE SIGNAL ;
    PORT
      LAYER Metal1 ;
        RECT 0.250 1940.950 0.530 1941.200 ;
    END
  END RESET[225]

  PIN RESET[226]
    DIRECTION INPUT ;
    USE SIGNAL ;
    PORT
      LAYER Metal1 ;
        RECT 0.250 1949.530 0.530 1949.780 ;
    END
  END RESET[226]

  PIN RESET[227]
    DIRECTION INPUT ;
    USE SIGNAL ;
    PORT
      LAYER Metal1 ;
        RECT 0.250 1958.110 0.530 1958.360 ;
    END
  END RESET[227]

  PIN RESET[228]
    DIRECTION INPUT ;
    USE SIGNAL ;
    PORT
      LAYER Metal1 ;
        RECT 0.250 1966.690 0.530 1966.940 ;
    END
  END RESET[228]

  PIN RESET[229]
    DIRECTION INPUT ;
    USE SIGNAL ;
    PORT
      LAYER Metal1 ;
        RECT 0.250 1975.270 0.530 1975.520 ;
    END
  END RESET[229]

  PIN RESET[230]
    DIRECTION INPUT ;
    USE SIGNAL ;
    PORT
      LAYER Metal1 ;
        RECT 0.250 1983.850 0.530 1984.100 ;
    END
  END RESET[230]

  PIN RESET[231]
    DIRECTION INPUT ;
    USE SIGNAL ;
    PORT
      LAYER Metal1 ;
        RECT 0.250 1992.430 0.530 1992.680 ;
    END
  END RESET[231]

  PIN RESET[232]
    DIRECTION INPUT ;
    USE SIGNAL ;
    PORT
      LAYER Metal1 ;
        RECT 0.250 2001.010 0.530 2001.260 ;
    END
  END RESET[232]

  PIN RESET[233]
    DIRECTION INPUT ;
    USE SIGNAL ;
    PORT
      LAYER Metal1 ;
        RECT 0.250 2009.590 0.530 2009.840 ;
    END
  END RESET[233]

  PIN RESET[234]
    DIRECTION INPUT ;
    USE SIGNAL ;
    PORT
      LAYER Metal1 ;
        RECT 0.250 2018.170 0.530 2018.420 ;
    END
  END RESET[234]

  PIN RESET[235]
    DIRECTION INPUT ;
    USE SIGNAL ;
    PORT
      LAYER Metal1 ;
        RECT 0.250 2026.750 0.530 2027.000 ;
    END
  END RESET[235]

  PIN RESET[236]
    DIRECTION INPUT ;
    USE SIGNAL ;
    PORT
      LAYER Metal1 ;
        RECT 0.250 2035.330 0.530 2035.580 ;
    END
  END RESET[236]

  PIN RESET[237]
    DIRECTION INPUT ;
    USE SIGNAL ;
    PORT
      LAYER Metal1 ;
        RECT 0.250 2043.910 0.530 2044.160 ;
    END
  END RESET[237]

  PIN RESET[238]
    DIRECTION INPUT ;
    USE SIGNAL ;
    PORT
      LAYER Metal1 ;
        RECT 0.250 2052.490 0.530 2052.740 ;
    END
  END RESET[238]

  PIN RESET[239]
    DIRECTION INPUT ;
    USE SIGNAL ;
    PORT
      LAYER Metal1 ;
        RECT 0.250 2061.070 0.530 2061.320 ;
    END
  END RESET[239]

  PIN COLUMN_OUT[0]
    DIRECTION OUTPUT ;
    USE SIGNAL ;
    PORT
      LAYER Metal2 ;
        RECT 8.095 2.425 8.375 2.705 ;
    END
  END COLUMN_OUT[0]

  PIN COLUMN_OUT[1]
    DIRECTION OUTPUT ;
    USE SIGNAL ;
    PORT
      LAYER Metal2 ;
        RECT 16.675 2.425 16.955 2.705 ;
    END
  END COLUMN_OUT[1]

  PIN COLUMN_OUT[2]
    DIRECTION OUTPUT ;
    USE SIGNAL ;
    PORT
      LAYER Metal2 ;
        RECT 25.255 2.425 25.535 2.705 ;
    END
  END COLUMN_OUT[2]

  PIN COLUMN_OUT[3]
    DIRECTION OUTPUT ;
    USE SIGNAL ;
    PORT
      LAYER Metal2 ;
        RECT 33.835 2.425 34.115 2.705 ;
    END
  END COLUMN_OUT[3]

  PIN COLUMN_OUT[4]
    DIRECTION OUTPUT ;
    USE SIGNAL ;
    PORT
      LAYER Metal2 ;
        RECT 42.415 2.425 42.695 2.705 ;
    END
  END COLUMN_OUT[4]

  PIN COLUMN_OUT[5]
    DIRECTION OUTPUT ;
    USE SIGNAL ;
    PORT
      LAYER Metal2 ;
        RECT 50.995 2.425 51.275 2.705 ;
    END
  END COLUMN_OUT[5]

  PIN COLUMN_OUT[6]
    DIRECTION OUTPUT ;
    USE SIGNAL ;
    PORT
      LAYER Metal2 ;
        RECT 59.575 2.425 59.855 2.705 ;
    END
  END COLUMN_OUT[6]

  PIN COLUMN_OUT[7]
    DIRECTION OUTPUT ;
    USE SIGNAL ;
    PORT
      LAYER Metal2 ;
        RECT 68.155 2.425 68.435 2.705 ;
    END
  END COLUMN_OUT[7]

  PIN COLUMN_OUT[8]
    DIRECTION OUTPUT ;
    USE SIGNAL ;
    PORT
      LAYER Metal2 ;
        RECT 76.735 2.425 77.015 2.705 ;
    END
  END COLUMN_OUT[8]

  PIN COLUMN_OUT[9]
    DIRECTION OUTPUT ;
    USE SIGNAL ;
    PORT
      LAYER Metal2 ;
        RECT 85.315 2.425 85.595 2.705 ;
    END
  END COLUMN_OUT[9]

  PIN COLUMN_OUT[10]
    DIRECTION OUTPUT ;
    USE SIGNAL ;
    PORT
      LAYER Metal2 ;
        RECT 93.895 2.425 94.175 2.705 ;
    END
  END COLUMN_OUT[10]

  PIN COLUMN_OUT[11]
    DIRECTION OUTPUT ;
    USE SIGNAL ;
    PORT
      LAYER Metal2 ;
        RECT 102.475 2.425 102.755 2.705 ;
    END
  END COLUMN_OUT[11]

  PIN COLUMN_OUT[12]
    DIRECTION OUTPUT ;
    USE SIGNAL ;
    PORT
      LAYER Metal2 ;
        RECT 111.055 2.425 111.335 2.705 ;
    END
  END COLUMN_OUT[12]

  PIN COLUMN_OUT[13]
    DIRECTION OUTPUT ;
    USE SIGNAL ;
    PORT
      LAYER Metal2 ;
        RECT 119.635 2.425 119.915 2.705 ;
    END
  END COLUMN_OUT[13]

  PIN COLUMN_OUT[14]
    DIRECTION OUTPUT ;
    USE SIGNAL ;
    PORT
      LAYER Metal2 ;
        RECT 128.215 2.425 128.495 2.705 ;
    END
  END COLUMN_OUT[14]

  PIN COLUMN_OUT[15]
    DIRECTION OUTPUT ;
    USE SIGNAL ;
    PORT
      LAYER Metal2 ;
        RECT 136.795 2.425 137.075 2.705 ;
    END
  END COLUMN_OUT[15]

  PIN COLUMN_OUT[16]
    DIRECTION OUTPUT ;
    USE SIGNAL ;
    PORT
      LAYER Metal2 ;
        RECT 145.375 2.425 145.655 2.705 ;
    END
  END COLUMN_OUT[16]

  PIN COLUMN_OUT[17]
    DIRECTION OUTPUT ;
    USE SIGNAL ;
    PORT
      LAYER Metal2 ;
        RECT 153.955 2.425 154.235 2.705 ;
    END
  END COLUMN_OUT[17]

  PIN COLUMN_OUT[18]
    DIRECTION OUTPUT ;
    USE SIGNAL ;
    PORT
      LAYER Metal2 ;
        RECT 162.535 2.425 162.815 2.705 ;
    END
  END COLUMN_OUT[18]

  PIN COLUMN_OUT[19]
    DIRECTION OUTPUT ;
    USE SIGNAL ;
    PORT
      LAYER Metal2 ;
        RECT 171.115 2.425 171.395 2.705 ;
    END
  END COLUMN_OUT[19]

  PIN COLUMN_OUT[20]
    DIRECTION OUTPUT ;
    USE SIGNAL ;
    PORT
      LAYER Metal2 ;
        RECT 179.695 2.425 179.975 2.705 ;
    END
  END COLUMN_OUT[20]

  PIN COLUMN_OUT[21]
    DIRECTION OUTPUT ;
    USE SIGNAL ;
    PORT
      LAYER Metal2 ;
        RECT 188.275 2.425 188.555 2.705 ;
    END
  END COLUMN_OUT[21]

  PIN COLUMN_OUT[22]
    DIRECTION OUTPUT ;
    USE SIGNAL ;
    PORT
      LAYER Metal2 ;
        RECT 196.855 2.425 197.135 2.705 ;
    END
  END COLUMN_OUT[22]

  PIN COLUMN_OUT[23]
    DIRECTION OUTPUT ;
    USE SIGNAL ;
    PORT
      LAYER Metal2 ;
        RECT 205.435 2.425 205.715 2.705 ;
    END
  END COLUMN_OUT[23]

  PIN COLUMN_OUT[24]
    DIRECTION OUTPUT ;
    USE SIGNAL ;
    PORT
      LAYER Metal2 ;
        RECT 214.015 2.425 214.295 2.705 ;
    END
  END COLUMN_OUT[24]

  PIN COLUMN_OUT[25]
    DIRECTION OUTPUT ;
    USE SIGNAL ;
    PORT
      LAYER Metal2 ;
        RECT 222.595 2.425 222.875 2.705 ;
    END
  END COLUMN_OUT[25]

  PIN COLUMN_OUT[26]
    DIRECTION OUTPUT ;
    USE SIGNAL ;
    PORT
      LAYER Metal2 ;
        RECT 231.175 2.425 231.455 2.705 ;
    END
  END COLUMN_OUT[26]

  PIN COLUMN_OUT[27]
    DIRECTION OUTPUT ;
    USE SIGNAL ;
    PORT
      LAYER Metal2 ;
        RECT 239.755 2.425 240.035 2.705 ;
    END
  END COLUMN_OUT[27]

  PIN COLUMN_OUT[28]
    DIRECTION OUTPUT ;
    USE SIGNAL ;
    PORT
      LAYER Metal2 ;
        RECT 248.335 2.425 248.615 2.705 ;
    END
  END COLUMN_OUT[28]

  PIN COLUMN_OUT[29]
    DIRECTION OUTPUT ;
    USE SIGNAL ;
    PORT
      LAYER Metal2 ;
        RECT 256.915 2.425 257.195 2.705 ;
    END
  END COLUMN_OUT[29]

  PIN COLUMN_OUT[30]
    DIRECTION OUTPUT ;
    USE SIGNAL ;
    PORT
      LAYER Metal2 ;
        RECT 265.495 2.425 265.775 2.705 ;
    END
  END COLUMN_OUT[30]

  PIN COLUMN_OUT[31]
    DIRECTION OUTPUT ;
    USE SIGNAL ;
    PORT
      LAYER Metal2 ;
        RECT 274.075 2.425 274.355 2.705 ;
    END
  END COLUMN_OUT[31]

  PIN COLUMN_OUT[32]
    DIRECTION OUTPUT ;
    USE SIGNAL ;
    PORT
      LAYER Metal2 ;
        RECT 282.655 2.425 282.935 2.705 ;
    END
  END COLUMN_OUT[32]

  PIN COLUMN_OUT[33]
    DIRECTION OUTPUT ;
    USE SIGNAL ;
    PORT
      LAYER Metal2 ;
        RECT 291.235 2.425 291.515 2.705 ;
    END
  END COLUMN_OUT[33]

  PIN COLUMN_OUT[34]
    DIRECTION OUTPUT ;
    USE SIGNAL ;
    PORT
      LAYER Metal2 ;
        RECT 299.815 2.425 300.095 2.705 ;
    END
  END COLUMN_OUT[34]

  PIN COLUMN_OUT[35]
    DIRECTION OUTPUT ;
    USE SIGNAL ;
    PORT
      LAYER Metal2 ;
        RECT 308.395 2.425 308.675 2.705 ;
    END
  END COLUMN_OUT[35]

  PIN COLUMN_OUT[36]
    DIRECTION OUTPUT ;
    USE SIGNAL ;
    PORT
      LAYER Metal2 ;
        RECT 316.975 2.425 317.255 2.705 ;
    END
  END COLUMN_OUT[36]

  PIN COLUMN_OUT[37]
    DIRECTION OUTPUT ;
    USE SIGNAL ;
    PORT
      LAYER Metal2 ;
        RECT 325.555 2.425 325.835 2.705 ;
    END
  END COLUMN_OUT[37]

  PIN COLUMN_OUT[38]
    DIRECTION OUTPUT ;
    USE SIGNAL ;
    PORT
      LAYER Metal2 ;
        RECT 334.135 2.425 334.415 2.705 ;
    END
  END COLUMN_OUT[38]

  PIN COLUMN_OUT[39]
    DIRECTION OUTPUT ;
    USE SIGNAL ;
    PORT
      LAYER Metal2 ;
        RECT 342.715 2.425 342.995 2.705 ;
    END
  END COLUMN_OUT[39]

  PIN COLUMN_OUT[40]
    DIRECTION OUTPUT ;
    USE SIGNAL ;
    PORT
      LAYER Metal2 ;
        RECT 351.295 2.425 351.575 2.705 ;
    END
  END COLUMN_OUT[40]

  PIN COLUMN_OUT[41]
    DIRECTION OUTPUT ;
    USE SIGNAL ;
    PORT
      LAYER Metal2 ;
        RECT 359.875 2.425 360.155 2.705 ;
    END
  END COLUMN_OUT[41]

  PIN COLUMN_OUT[42]
    DIRECTION OUTPUT ;
    USE SIGNAL ;
    PORT
      LAYER Metal2 ;
        RECT 368.455 2.425 368.735 2.705 ;
    END
  END COLUMN_OUT[42]

  PIN COLUMN_OUT[43]
    DIRECTION OUTPUT ;
    USE SIGNAL ;
    PORT
      LAYER Metal2 ;
        RECT 377.035 2.425 377.315 2.705 ;
    END
  END COLUMN_OUT[43]

  PIN COLUMN_OUT[44]
    DIRECTION OUTPUT ;
    USE SIGNAL ;
    PORT
      LAYER Metal2 ;
        RECT 385.615 2.425 385.895 2.705 ;
    END
  END COLUMN_OUT[44]

  PIN COLUMN_OUT[45]
    DIRECTION OUTPUT ;
    USE SIGNAL ;
    PORT
      LAYER Metal2 ;
        RECT 394.195 2.425 394.475 2.705 ;
    END
  END COLUMN_OUT[45]

  PIN COLUMN_OUT[46]
    DIRECTION OUTPUT ;
    USE SIGNAL ;
    PORT
      LAYER Metal2 ;
        RECT 402.775 2.425 403.055 2.705 ;
    END
  END COLUMN_OUT[46]

  PIN COLUMN_OUT[47]
    DIRECTION OUTPUT ;
    USE SIGNAL ;
    PORT
      LAYER Metal2 ;
        RECT 411.355 2.425 411.635 2.705 ;
    END
  END COLUMN_OUT[47]

  PIN COLUMN_OUT[48]
    DIRECTION OUTPUT ;
    USE SIGNAL ;
    PORT
      LAYER Metal2 ;
        RECT 419.935 2.425 420.215 2.705 ;
    END
  END COLUMN_OUT[48]

  PIN COLUMN_OUT[49]
    DIRECTION OUTPUT ;
    USE SIGNAL ;
    PORT
      LAYER Metal2 ;
        RECT 428.515 2.425 428.795 2.705 ;
    END
  END COLUMN_OUT[49]

  PIN COLUMN_OUT[50]
    DIRECTION OUTPUT ;
    USE SIGNAL ;
    PORT
      LAYER Metal2 ;
        RECT 437.095 2.425 437.375 2.705 ;
    END
  END COLUMN_OUT[50]

  PIN COLUMN_OUT[51]
    DIRECTION OUTPUT ;
    USE SIGNAL ;
    PORT
      LAYER Metal2 ;
        RECT 445.675 2.425 445.955 2.705 ;
    END
  END COLUMN_OUT[51]

  PIN COLUMN_OUT[52]
    DIRECTION OUTPUT ;
    USE SIGNAL ;
    PORT
      LAYER Metal2 ;
        RECT 454.255 2.425 454.535 2.705 ;
    END
  END COLUMN_OUT[52]

  PIN COLUMN_OUT[53]
    DIRECTION OUTPUT ;
    USE SIGNAL ;
    PORT
      LAYER Metal2 ;
        RECT 462.835 2.425 463.115 2.705 ;
    END
  END COLUMN_OUT[53]

  PIN COLUMN_OUT[54]
    DIRECTION OUTPUT ;
    USE SIGNAL ;
    PORT
      LAYER Metal2 ;
        RECT 471.415 2.425 471.695 2.705 ;
    END
  END COLUMN_OUT[54]

  PIN COLUMN_OUT[55]
    DIRECTION OUTPUT ;
    USE SIGNAL ;
    PORT
      LAYER Metal2 ;
        RECT 479.995 2.425 480.275 2.705 ;
    END
  END COLUMN_OUT[55]

  PIN COLUMN_OUT[56]
    DIRECTION OUTPUT ;
    USE SIGNAL ;
    PORT
      LAYER Metal2 ;
        RECT 488.575 2.425 488.855 2.705 ;
    END
  END COLUMN_OUT[56]

  PIN COLUMN_OUT[57]
    DIRECTION OUTPUT ;
    USE SIGNAL ;
    PORT
      LAYER Metal2 ;
        RECT 497.155 2.425 497.435 2.705 ;
    END
  END COLUMN_OUT[57]

  PIN COLUMN_OUT[58]
    DIRECTION OUTPUT ;
    USE SIGNAL ;
    PORT
      LAYER Metal2 ;
        RECT 505.735 2.425 506.015 2.705 ;
    END
  END COLUMN_OUT[58]

  PIN COLUMN_OUT[59]
    DIRECTION OUTPUT ;
    USE SIGNAL ;
    PORT
      LAYER Metal2 ;
        RECT 514.315 2.425 514.595 2.705 ;
    END
  END COLUMN_OUT[59]

  PIN COLUMN_OUT[60]
    DIRECTION OUTPUT ;
    USE SIGNAL ;
    PORT
      LAYER Metal2 ;
        RECT 522.895 2.425 523.175 2.705 ;
    END
  END COLUMN_OUT[60]

  PIN COLUMN_OUT[61]
    DIRECTION OUTPUT ;
    USE SIGNAL ;
    PORT
      LAYER Metal2 ;
        RECT 531.475 2.425 531.755 2.705 ;
    END
  END COLUMN_OUT[61]

  PIN COLUMN_OUT[62]
    DIRECTION OUTPUT ;
    USE SIGNAL ;
    PORT
      LAYER Metal2 ;
        RECT 540.055 2.425 540.335 2.705 ;
    END
  END COLUMN_OUT[62]

  PIN COLUMN_OUT[63]
    DIRECTION OUTPUT ;
    USE SIGNAL ;
    PORT
      LAYER Metal2 ;
        RECT 548.635 2.425 548.915 2.705 ;
    END
  END COLUMN_OUT[63]

  PIN COLUMN_OUT[64]
    DIRECTION OUTPUT ;
    USE SIGNAL ;
    PORT
      LAYER Metal2 ;
        RECT 557.215 2.425 557.495 2.705 ;
    END
  END COLUMN_OUT[64]

  PIN COLUMN_OUT[65]
    DIRECTION OUTPUT ;
    USE SIGNAL ;
    PORT
      LAYER Metal2 ;
        RECT 565.795 2.425 566.075 2.705 ;
    END
  END COLUMN_OUT[65]

  PIN COLUMN_OUT[66]
    DIRECTION OUTPUT ;
    USE SIGNAL ;
    PORT
      LAYER Metal2 ;
        RECT 574.375 2.425 574.655 2.705 ;
    END
  END COLUMN_OUT[66]

  PIN COLUMN_OUT[67]
    DIRECTION OUTPUT ;
    USE SIGNAL ;
    PORT
      LAYER Metal2 ;
        RECT 582.955 2.425 583.235 2.705 ;
    END
  END COLUMN_OUT[67]

  PIN COLUMN_OUT[68]
    DIRECTION OUTPUT ;
    USE SIGNAL ;
    PORT
      LAYER Metal2 ;
        RECT 591.535 2.425 591.815 2.705 ;
    END
  END COLUMN_OUT[68]

  PIN COLUMN_OUT[69]
    DIRECTION OUTPUT ;
    USE SIGNAL ;
    PORT
      LAYER Metal2 ;
        RECT 600.115 2.425 600.395 2.705 ;
    END
  END COLUMN_OUT[69]

  PIN COLUMN_OUT[70]
    DIRECTION OUTPUT ;
    USE SIGNAL ;
    PORT
      LAYER Metal2 ;
        RECT 608.695 2.425 608.975 2.705 ;
    END
  END COLUMN_OUT[70]

  PIN COLUMN_OUT[71]
    DIRECTION OUTPUT ;
    USE SIGNAL ;
    PORT
      LAYER Metal2 ;
        RECT 617.275 2.425 617.555 2.705 ;
    END
  END COLUMN_OUT[71]

  PIN COLUMN_OUT[72]
    DIRECTION OUTPUT ;
    USE SIGNAL ;
    PORT
      LAYER Metal2 ;
        RECT 625.855 2.425 626.135 2.705 ;
    END
  END COLUMN_OUT[72]

  PIN COLUMN_OUT[73]
    DIRECTION OUTPUT ;
    USE SIGNAL ;
    PORT
      LAYER Metal2 ;
        RECT 634.435 2.425 634.715 2.705 ;
    END
  END COLUMN_OUT[73]

  PIN COLUMN_OUT[74]
    DIRECTION OUTPUT ;
    USE SIGNAL ;
    PORT
      LAYER Metal2 ;
        RECT 643.015 2.425 643.295 2.705 ;
    END
  END COLUMN_OUT[74]

  PIN COLUMN_OUT[75]
    DIRECTION OUTPUT ;
    USE SIGNAL ;
    PORT
      LAYER Metal2 ;
        RECT 651.595 2.425 651.875 2.705 ;
    END
  END COLUMN_OUT[75]

  PIN COLUMN_OUT[76]
    DIRECTION OUTPUT ;
    USE SIGNAL ;
    PORT
      LAYER Metal2 ;
        RECT 660.175 2.425 660.455 2.705 ;
    END
  END COLUMN_OUT[76]

  PIN COLUMN_OUT[77]
    DIRECTION OUTPUT ;
    USE SIGNAL ;
    PORT
      LAYER Metal2 ;
        RECT 668.755 2.425 669.035 2.705 ;
    END
  END COLUMN_OUT[77]

  PIN COLUMN_OUT[78]
    DIRECTION OUTPUT ;
    USE SIGNAL ;
    PORT
      LAYER Metal2 ;
        RECT 677.335 2.425 677.615 2.705 ;
    END
  END COLUMN_OUT[78]

  PIN COLUMN_OUT[79]
    DIRECTION OUTPUT ;
    USE SIGNAL ;
    PORT
      LAYER Metal2 ;
        RECT 685.915 2.425 686.195 2.705 ;
    END
  END COLUMN_OUT[79]

  PIN COLUMN_OUT[80]
    DIRECTION OUTPUT ;
    USE SIGNAL ;
    PORT
      LAYER Metal2 ;
        RECT 694.495 2.425 694.775 2.705 ;
    END
  END COLUMN_OUT[80]

  PIN COLUMN_OUT[81]
    DIRECTION OUTPUT ;
    USE SIGNAL ;
    PORT
      LAYER Metal2 ;
        RECT 703.075 2.425 703.355 2.705 ;
    END
  END COLUMN_OUT[81]

  PIN COLUMN_OUT[82]
    DIRECTION OUTPUT ;
    USE SIGNAL ;
    PORT
      LAYER Metal2 ;
        RECT 711.655 2.425 711.935 2.705 ;
    END
  END COLUMN_OUT[82]

  PIN COLUMN_OUT[83]
    DIRECTION OUTPUT ;
    USE SIGNAL ;
    PORT
      LAYER Metal2 ;
        RECT 720.235 2.425 720.515 2.705 ;
    END
  END COLUMN_OUT[83]

  PIN COLUMN_OUT[84]
    DIRECTION OUTPUT ;
    USE SIGNAL ;
    PORT
      LAYER Metal2 ;
        RECT 728.815 2.425 729.095 2.705 ;
    END
  END COLUMN_OUT[84]

  PIN COLUMN_OUT[85]
    DIRECTION OUTPUT ;
    USE SIGNAL ;
    PORT
      LAYER Metal2 ;
        RECT 737.395 2.425 737.675 2.705 ;
    END
  END COLUMN_OUT[85]

  PIN COLUMN_OUT[86]
    DIRECTION OUTPUT ;
    USE SIGNAL ;
    PORT
      LAYER Metal2 ;
        RECT 745.975 2.425 746.255 2.705 ;
    END
  END COLUMN_OUT[86]

  PIN COLUMN_OUT[87]
    DIRECTION OUTPUT ;
    USE SIGNAL ;
    PORT
      LAYER Metal2 ;
        RECT 754.555 2.425 754.835 2.705 ;
    END
  END COLUMN_OUT[87]

  PIN COLUMN_OUT[88]
    DIRECTION OUTPUT ;
    USE SIGNAL ;
    PORT
      LAYER Metal2 ;
        RECT 763.135 2.425 763.415 2.705 ;
    END
  END COLUMN_OUT[88]

  PIN COLUMN_OUT[89]
    DIRECTION OUTPUT ;
    USE SIGNAL ;
    PORT
      LAYER Metal2 ;
        RECT 771.715 2.425 771.995 2.705 ;
    END
  END COLUMN_OUT[89]

  PIN COLUMN_OUT[90]
    DIRECTION OUTPUT ;
    USE SIGNAL ;
    PORT
      LAYER Metal2 ;
        RECT 780.295 2.425 780.575 2.705 ;
    END
  END COLUMN_OUT[90]

  PIN COLUMN_OUT[91]
    DIRECTION OUTPUT ;
    USE SIGNAL ;
    PORT
      LAYER Metal2 ;
        RECT 788.875 2.425 789.155 2.705 ;
    END
  END COLUMN_OUT[91]

  PIN COLUMN_OUT[92]
    DIRECTION OUTPUT ;
    USE SIGNAL ;
    PORT
      LAYER Metal2 ;
        RECT 797.455 2.425 797.735 2.705 ;
    END
  END COLUMN_OUT[92]

  PIN COLUMN_OUT[93]
    DIRECTION OUTPUT ;
    USE SIGNAL ;
    PORT
      LAYER Metal2 ;
        RECT 806.035 2.425 806.315 2.705 ;
    END
  END COLUMN_OUT[93]

  PIN COLUMN_OUT[94]
    DIRECTION OUTPUT ;
    USE SIGNAL ;
    PORT
      LAYER Metal2 ;
        RECT 814.615 2.425 814.895 2.705 ;
    END
  END COLUMN_OUT[94]

  PIN COLUMN_OUT[95]
    DIRECTION OUTPUT ;
    USE SIGNAL ;
    PORT
      LAYER Metal2 ;
        RECT 823.195 2.425 823.475 2.705 ;
    END
  END COLUMN_OUT[95]

  PIN COLUMN_OUT[96]
    DIRECTION OUTPUT ;
    USE SIGNAL ;
    PORT
      LAYER Metal2 ;
        RECT 831.775 2.425 832.055 2.705 ;
    END
  END COLUMN_OUT[96]

  PIN COLUMN_OUT[97]
    DIRECTION OUTPUT ;
    USE SIGNAL ;
    PORT
      LAYER Metal2 ;
        RECT 840.355 2.425 840.635 2.705 ;
    END
  END COLUMN_OUT[97]

  PIN COLUMN_OUT[98]
    DIRECTION OUTPUT ;
    USE SIGNAL ;
    PORT
      LAYER Metal2 ;
        RECT 848.935 2.425 849.215 2.705 ;
    END
  END COLUMN_OUT[98]

  PIN COLUMN_OUT[99]
    DIRECTION OUTPUT ;
    USE SIGNAL ;
    PORT
      LAYER Metal2 ;
        RECT 857.515 2.425 857.795 2.705 ;
    END
  END COLUMN_OUT[99]

  PIN COLUMN_OUT[100]
    DIRECTION OUTPUT ;
    USE SIGNAL ;
    PORT
      LAYER Metal2 ;
        RECT 866.095 2.425 866.375 2.705 ;
    END
  END COLUMN_OUT[100]

  PIN COLUMN_OUT[101]
    DIRECTION OUTPUT ;
    USE SIGNAL ;
    PORT
      LAYER Metal2 ;
        RECT 874.675 2.425 874.955 2.705 ;
    END
  END COLUMN_OUT[101]

  PIN COLUMN_OUT[102]
    DIRECTION OUTPUT ;
    USE SIGNAL ;
    PORT
      LAYER Metal2 ;
        RECT 883.255 2.425 883.535 2.705 ;
    END
  END COLUMN_OUT[102]

  PIN COLUMN_OUT[103]
    DIRECTION OUTPUT ;
    USE SIGNAL ;
    PORT
      LAYER Metal2 ;
        RECT 891.835 2.425 892.115 2.705 ;
    END
  END COLUMN_OUT[103]

  PIN COLUMN_OUT[104]
    DIRECTION OUTPUT ;
    USE SIGNAL ;
    PORT
      LAYER Metal2 ;
        RECT 900.415 2.425 900.695 2.705 ;
    END
  END COLUMN_OUT[104]

  PIN COLUMN_OUT[105]
    DIRECTION OUTPUT ;
    USE SIGNAL ;
    PORT
      LAYER Metal2 ;
        RECT 908.995 2.425 909.275 2.705 ;
    END
  END COLUMN_OUT[105]

  PIN COLUMN_OUT[106]
    DIRECTION OUTPUT ;
    USE SIGNAL ;
    PORT
      LAYER Metal2 ;
        RECT 917.575 2.425 917.855 2.705 ;
    END
  END COLUMN_OUT[106]

  PIN COLUMN_OUT[107]
    DIRECTION OUTPUT ;
    USE SIGNAL ;
    PORT
      LAYER Metal2 ;
        RECT 926.155 2.425 926.435 2.705 ;
    END
  END COLUMN_OUT[107]

  PIN COLUMN_OUT[108]
    DIRECTION OUTPUT ;
    USE SIGNAL ;
    PORT
      LAYER Metal2 ;
        RECT 934.735 2.425 935.015 2.705 ;
    END
  END COLUMN_OUT[108]

  PIN COLUMN_OUT[109]
    DIRECTION OUTPUT ;
    USE SIGNAL ;
    PORT
      LAYER Metal2 ;
        RECT 943.315 2.425 943.595 2.705 ;
    END
  END COLUMN_OUT[109]

  PIN COLUMN_OUT[110]
    DIRECTION OUTPUT ;
    USE SIGNAL ;
    PORT
      LAYER Metal2 ;
        RECT 951.895 2.425 952.175 2.705 ;
    END
  END COLUMN_OUT[110]

  PIN COLUMN_OUT[111]
    DIRECTION OUTPUT ;
    USE SIGNAL ;
    PORT
      LAYER Metal2 ;
        RECT 960.475 2.425 960.755 2.705 ;
    END
  END COLUMN_OUT[111]

  PIN COLUMN_OUT[112]
    DIRECTION OUTPUT ;
    USE SIGNAL ;
    PORT
      LAYER Metal2 ;
        RECT 969.055 2.425 969.335 2.705 ;
    END
  END COLUMN_OUT[112]

  PIN COLUMN_OUT[113]
    DIRECTION OUTPUT ;
    USE SIGNAL ;
    PORT
      LAYER Metal2 ;
        RECT 977.635 2.425 977.915 2.705 ;
    END
  END COLUMN_OUT[113]

  PIN COLUMN_OUT[114]
    DIRECTION OUTPUT ;
    USE SIGNAL ;
    PORT
      LAYER Metal2 ;
        RECT 986.215 2.425 986.495 2.705 ;
    END
  END COLUMN_OUT[114]

  PIN COLUMN_OUT[115]
    DIRECTION OUTPUT ;
    USE SIGNAL ;
    PORT
      LAYER Metal2 ;
        RECT 994.795 2.425 995.075 2.705 ;
    END
  END COLUMN_OUT[115]

  PIN COLUMN_OUT[116]
    DIRECTION OUTPUT ;
    USE SIGNAL ;
    PORT
      LAYER Metal2 ;
        RECT 1003.375 2.425 1003.655 2.705 ;
    END
  END COLUMN_OUT[116]

  PIN COLUMN_OUT[117]
    DIRECTION OUTPUT ;
    USE SIGNAL ;
    PORT
      LAYER Metal2 ;
        RECT 1011.955 2.425 1012.235 2.705 ;
    END
  END COLUMN_OUT[117]

  PIN COLUMN_OUT[118]
    DIRECTION OUTPUT ;
    USE SIGNAL ;
    PORT
      LAYER Metal2 ;
        RECT 1020.535 2.425 1020.815 2.705 ;
    END
  END COLUMN_OUT[118]

  PIN COLUMN_OUT[119]
    DIRECTION OUTPUT ;
    USE SIGNAL ;
    PORT
      LAYER Metal2 ;
        RECT 1029.115 2.425 1029.395 2.705 ;
    END
  END COLUMN_OUT[119]

  PIN COLUMN_OUT[120]
    DIRECTION OUTPUT ;
    USE SIGNAL ;
    PORT
      LAYER Metal2 ;
        RECT 1037.695 2.425 1037.975 2.705 ;
    END
  END COLUMN_OUT[120]

  PIN COLUMN_OUT[121]
    DIRECTION OUTPUT ;
    USE SIGNAL ;
    PORT
      LAYER Metal2 ;
        RECT 1046.275 2.425 1046.555 2.705 ;
    END
  END COLUMN_OUT[121]

  PIN COLUMN_OUT[122]
    DIRECTION OUTPUT ;
    USE SIGNAL ;
    PORT
      LAYER Metal2 ;
        RECT 1054.855 2.425 1055.135 2.705 ;
    END
  END COLUMN_OUT[122]

  PIN COLUMN_OUT[123]
    DIRECTION OUTPUT ;
    USE SIGNAL ;
    PORT
      LAYER Metal2 ;
        RECT 1063.435 2.425 1063.715 2.705 ;
    END
  END COLUMN_OUT[123]

  PIN COLUMN_OUT[124]
    DIRECTION OUTPUT ;
    USE SIGNAL ;
    PORT
      LAYER Metal2 ;
        RECT 1072.015 2.425 1072.295 2.705 ;
    END
  END COLUMN_OUT[124]

  PIN COLUMN_OUT[125]
    DIRECTION OUTPUT ;
    USE SIGNAL ;
    PORT
      LAYER Metal2 ;
        RECT 1080.595 2.425 1080.875 2.705 ;
    END
  END COLUMN_OUT[125]

  PIN COLUMN_OUT[126]
    DIRECTION OUTPUT ;
    USE SIGNAL ;
    PORT
      LAYER Metal2 ;
        RECT 1089.175 2.425 1089.455 2.705 ;
    END
  END COLUMN_OUT[126]

  PIN COLUMN_OUT[127]
    DIRECTION OUTPUT ;
    USE SIGNAL ;
    PORT
      LAYER Metal2 ;
        RECT 1097.755 2.425 1098.035 2.705 ;
    END
  END COLUMN_OUT[127]

  PIN COLUMN_OUT[128]
    DIRECTION OUTPUT ;
    USE SIGNAL ;
    PORT
      LAYER Metal2 ;
        RECT 1106.335 2.425 1106.615 2.705 ;
    END
  END COLUMN_OUT[128]

  PIN COLUMN_OUT[129]
    DIRECTION OUTPUT ;
    USE SIGNAL ;
    PORT
      LAYER Metal2 ;
        RECT 1114.915 2.425 1115.195 2.705 ;
    END
  END COLUMN_OUT[129]

  PIN COLUMN_OUT[130]
    DIRECTION OUTPUT ;
    USE SIGNAL ;
    PORT
      LAYER Metal2 ;
        RECT 1123.495 2.425 1123.775 2.705 ;
    END
  END COLUMN_OUT[130]

  PIN COLUMN_OUT[131]
    DIRECTION OUTPUT ;
    USE SIGNAL ;
    PORT
      LAYER Metal2 ;
        RECT 1132.075 2.425 1132.355 2.705 ;
    END
  END COLUMN_OUT[131]

  PIN COLUMN_OUT[132]
    DIRECTION OUTPUT ;
    USE SIGNAL ;
    PORT
      LAYER Metal2 ;
        RECT 1140.655 2.425 1140.935 2.705 ;
    END
  END COLUMN_OUT[132]

  PIN COLUMN_OUT[133]
    DIRECTION OUTPUT ;
    USE SIGNAL ;
    PORT
      LAYER Metal2 ;
        RECT 1149.235 2.425 1149.515 2.705 ;
    END
  END COLUMN_OUT[133]

  PIN COLUMN_OUT[134]
    DIRECTION OUTPUT ;
    USE SIGNAL ;
    PORT
      LAYER Metal2 ;
        RECT 1157.815 2.425 1158.095 2.705 ;
    END
  END COLUMN_OUT[134]

  PIN COLUMN_OUT[135]
    DIRECTION OUTPUT ;
    USE SIGNAL ;
    PORT
      LAYER Metal2 ;
        RECT 1166.395 2.425 1166.675 2.705 ;
    END
  END COLUMN_OUT[135]

  PIN COLUMN_OUT[136]
    DIRECTION OUTPUT ;
    USE SIGNAL ;
    PORT
      LAYER Metal2 ;
        RECT 1174.975 2.425 1175.255 2.705 ;
    END
  END COLUMN_OUT[136]

  PIN COLUMN_OUT[137]
    DIRECTION OUTPUT ;
    USE SIGNAL ;
    PORT
      LAYER Metal2 ;
        RECT 1183.555 2.425 1183.835 2.705 ;
    END
  END COLUMN_OUT[137]

  PIN COLUMN_OUT[138]
    DIRECTION OUTPUT ;
    USE SIGNAL ;
    PORT
      LAYER Metal2 ;
        RECT 1192.135 2.425 1192.415 2.705 ;
    END
  END COLUMN_OUT[138]

  PIN COLUMN_OUT[139]
    DIRECTION OUTPUT ;
    USE SIGNAL ;
    PORT
      LAYER Metal2 ;
        RECT 1200.715 2.425 1200.995 2.705 ;
    END
  END COLUMN_OUT[139]

  PIN COLUMN_OUT[140]
    DIRECTION OUTPUT ;
    USE SIGNAL ;
    PORT
      LAYER Metal2 ;
        RECT 1209.295 2.425 1209.575 2.705 ;
    END
  END COLUMN_OUT[140]

  PIN COLUMN_OUT[141]
    DIRECTION OUTPUT ;
    USE SIGNAL ;
    PORT
      LAYER Metal2 ;
        RECT 1217.875 2.425 1218.155 2.705 ;
    END
  END COLUMN_OUT[141]

  PIN COLUMN_OUT[142]
    DIRECTION OUTPUT ;
    USE SIGNAL ;
    PORT
      LAYER Metal2 ;
        RECT 1226.455 2.425 1226.735 2.705 ;
    END
  END COLUMN_OUT[142]

  PIN COLUMN_OUT[143]
    DIRECTION OUTPUT ;
    USE SIGNAL ;
    PORT
      LAYER Metal2 ;
        RECT 1235.035 2.425 1235.315 2.705 ;
    END
  END COLUMN_OUT[143]

  PIN COLUMN_OUT[144]
    DIRECTION OUTPUT ;
    USE SIGNAL ;
    PORT
      LAYER Metal2 ;
        RECT 1243.615 2.425 1243.895 2.705 ;
    END
  END COLUMN_OUT[144]

  PIN COLUMN_OUT[145]
    DIRECTION OUTPUT ;
    USE SIGNAL ;
    PORT
      LAYER Metal2 ;
        RECT 1252.195 2.425 1252.475 2.705 ;
    END
  END COLUMN_OUT[145]

  PIN COLUMN_OUT[146]
    DIRECTION OUTPUT ;
    USE SIGNAL ;
    PORT
      LAYER Metal2 ;
        RECT 1260.775 2.425 1261.055 2.705 ;
    END
  END COLUMN_OUT[146]

  PIN COLUMN_OUT[147]
    DIRECTION OUTPUT ;
    USE SIGNAL ;
    PORT
      LAYER Metal2 ;
        RECT 1269.355 2.425 1269.635 2.705 ;
    END
  END COLUMN_OUT[147]

  PIN COLUMN_OUT[148]
    DIRECTION OUTPUT ;
    USE SIGNAL ;
    PORT
      LAYER Metal2 ;
        RECT 1277.935 2.425 1278.215 2.705 ;
    END
  END COLUMN_OUT[148]

  PIN COLUMN_OUT[149]
    DIRECTION OUTPUT ;
    USE SIGNAL ;
    PORT
      LAYER Metal2 ;
        RECT 1286.515 2.425 1286.795 2.705 ;
    END
  END COLUMN_OUT[149]

  PIN COLUMN_OUT[150]
    DIRECTION OUTPUT ;
    USE SIGNAL ;
    PORT
      LAYER Metal2 ;
        RECT 1295.095 2.425 1295.375 2.705 ;
    END
  END COLUMN_OUT[150]

  PIN COLUMN_OUT[151]
    DIRECTION OUTPUT ;
    USE SIGNAL ;
    PORT
      LAYER Metal2 ;
        RECT 1303.675 2.425 1303.955 2.705 ;
    END
  END COLUMN_OUT[151]

  PIN COLUMN_OUT[152]
    DIRECTION OUTPUT ;
    USE SIGNAL ;
    PORT
      LAYER Metal2 ;
        RECT 1312.255 2.425 1312.535 2.705 ;
    END
  END COLUMN_OUT[152]

  PIN COLUMN_OUT[153]
    DIRECTION OUTPUT ;
    USE SIGNAL ;
    PORT
      LAYER Metal2 ;
        RECT 1320.835 2.425 1321.115 2.705 ;
    END
  END COLUMN_OUT[153]

  PIN COLUMN_OUT[154]
    DIRECTION OUTPUT ;
    USE SIGNAL ;
    PORT
      LAYER Metal2 ;
        RECT 1329.415 2.425 1329.695 2.705 ;
    END
  END COLUMN_OUT[154]

  PIN COLUMN_OUT[155]
    DIRECTION OUTPUT ;
    USE SIGNAL ;
    PORT
      LAYER Metal2 ;
        RECT 1337.995 2.425 1338.275 2.705 ;
    END
  END COLUMN_OUT[155]

  PIN COLUMN_OUT[156]
    DIRECTION OUTPUT ;
    USE SIGNAL ;
    PORT
      LAYER Metal2 ;
        RECT 1346.575 2.425 1346.855 2.705 ;
    END
  END COLUMN_OUT[156]

  PIN COLUMN_OUT[157]
    DIRECTION OUTPUT ;
    USE SIGNAL ;
    PORT
      LAYER Metal2 ;
        RECT 1355.155 2.425 1355.435 2.705 ;
    END
  END COLUMN_OUT[157]

  PIN COLUMN_OUT[158]
    DIRECTION OUTPUT ;
    USE SIGNAL ;
    PORT
      LAYER Metal2 ;
        RECT 1363.735 2.425 1364.015 2.705 ;
    END
  END COLUMN_OUT[158]

  PIN COLUMN_OUT[159]
    DIRECTION OUTPUT ;
    USE SIGNAL ;
    PORT
      LAYER Metal2 ;
        RECT 1372.315 2.425 1372.595 2.705 ;
    END
  END COLUMN_OUT[159]

  PIN COLUMN_OUT[160]
    DIRECTION OUTPUT ;
    USE SIGNAL ;
    PORT
      LAYER Metal2 ;
        RECT 1380.895 2.425 1381.175 2.705 ;
    END
  END COLUMN_OUT[160]

  PIN COLUMN_OUT[161]
    DIRECTION OUTPUT ;
    USE SIGNAL ;
    PORT
      LAYER Metal2 ;
        RECT 1389.475 2.425 1389.755 2.705 ;
    END
  END COLUMN_OUT[161]

  PIN COLUMN_OUT[162]
    DIRECTION OUTPUT ;
    USE SIGNAL ;
    PORT
      LAYER Metal2 ;
        RECT 1398.055 2.425 1398.335 2.705 ;
    END
  END COLUMN_OUT[162]

  PIN COLUMN_OUT[163]
    DIRECTION OUTPUT ;
    USE SIGNAL ;
    PORT
      LAYER Metal2 ;
        RECT 1406.635 2.425 1406.915 2.705 ;
    END
  END COLUMN_OUT[163]

  PIN COLUMN_OUT[164]
    DIRECTION OUTPUT ;
    USE SIGNAL ;
    PORT
      LAYER Metal2 ;
        RECT 1415.215 2.425 1415.495 2.705 ;
    END
  END COLUMN_OUT[164]

  PIN COLUMN_OUT[165]
    DIRECTION OUTPUT ;
    USE SIGNAL ;
    PORT
      LAYER Metal2 ;
        RECT 1423.795 2.425 1424.075 2.705 ;
    END
  END COLUMN_OUT[165]

  PIN COLUMN_OUT[166]
    DIRECTION OUTPUT ;
    USE SIGNAL ;
    PORT
      LAYER Metal2 ;
        RECT 1432.375 2.425 1432.655 2.705 ;
    END
  END COLUMN_OUT[166]

  PIN COLUMN_OUT[167]
    DIRECTION OUTPUT ;
    USE SIGNAL ;
    PORT
      LAYER Metal2 ;
        RECT 1440.955 2.425 1441.235 2.705 ;
    END
  END COLUMN_OUT[167]

  PIN COLUMN_OUT[168]
    DIRECTION OUTPUT ;
    USE SIGNAL ;
    PORT
      LAYER Metal2 ;
        RECT 1449.535 2.425 1449.815 2.705 ;
    END
  END COLUMN_OUT[168]

  PIN COLUMN_OUT[169]
    DIRECTION OUTPUT ;
    USE SIGNAL ;
    PORT
      LAYER Metal2 ;
        RECT 1458.115 2.425 1458.395 2.705 ;
    END
  END COLUMN_OUT[169]

  PIN COLUMN_OUT[170]
    DIRECTION OUTPUT ;
    USE SIGNAL ;
    PORT
      LAYER Metal2 ;
        RECT 1466.695 2.425 1466.975 2.705 ;
    END
  END COLUMN_OUT[170]

  PIN COLUMN_OUT[171]
    DIRECTION OUTPUT ;
    USE SIGNAL ;
    PORT
      LAYER Metal2 ;
        RECT 1475.275 2.425 1475.555 2.705 ;
    END
  END COLUMN_OUT[171]

  PIN COLUMN_OUT[172]
    DIRECTION OUTPUT ;
    USE SIGNAL ;
    PORT
      LAYER Metal2 ;
        RECT 1483.855 2.425 1484.135 2.705 ;
    END
  END COLUMN_OUT[172]

  PIN COLUMN_OUT[173]
    DIRECTION OUTPUT ;
    USE SIGNAL ;
    PORT
      LAYER Metal2 ;
        RECT 1492.435 2.425 1492.715 2.705 ;
    END
  END COLUMN_OUT[173]

  PIN COLUMN_OUT[174]
    DIRECTION OUTPUT ;
    USE SIGNAL ;
    PORT
      LAYER Metal2 ;
        RECT 1501.015 2.425 1501.295 2.705 ;
    END
  END COLUMN_OUT[174]

  PIN COLUMN_OUT[175]
    DIRECTION OUTPUT ;
    USE SIGNAL ;
    PORT
      LAYER Metal2 ;
        RECT 1509.595 2.425 1509.875 2.705 ;
    END
  END COLUMN_OUT[175]

  PIN COLUMN_OUT[176]
    DIRECTION OUTPUT ;
    USE SIGNAL ;
    PORT
      LAYER Metal2 ;
        RECT 1518.175 2.425 1518.455 2.705 ;
    END
  END COLUMN_OUT[176]

  PIN COLUMN_OUT[177]
    DIRECTION OUTPUT ;
    USE SIGNAL ;
    PORT
      LAYER Metal2 ;
        RECT 1526.755 2.425 1527.035 2.705 ;
    END
  END COLUMN_OUT[177]

  PIN COLUMN_OUT[178]
    DIRECTION OUTPUT ;
    USE SIGNAL ;
    PORT
      LAYER Metal2 ;
        RECT 1535.335 2.425 1535.615 2.705 ;
    END
  END COLUMN_OUT[178]

  PIN COLUMN_OUT[179]
    DIRECTION OUTPUT ;
    USE SIGNAL ;
    PORT
      LAYER Metal2 ;
        RECT 1543.915 2.425 1544.195 2.705 ;
    END
  END COLUMN_OUT[179]

  PIN COLUMN_OUT[180]
    DIRECTION OUTPUT ;
    USE SIGNAL ;
    PORT
      LAYER Metal2 ;
        RECT 1552.495 2.425 1552.775 2.705 ;
    END
  END COLUMN_OUT[180]

  PIN COLUMN_OUT[181]
    DIRECTION OUTPUT ;
    USE SIGNAL ;
    PORT
      LAYER Metal2 ;
        RECT 1561.075 2.425 1561.355 2.705 ;
    END
  END COLUMN_OUT[181]

  PIN COLUMN_OUT[182]
    DIRECTION OUTPUT ;
    USE SIGNAL ;
    PORT
      LAYER Metal2 ;
        RECT 1569.655 2.425 1569.935 2.705 ;
    END
  END COLUMN_OUT[182]

  PIN COLUMN_OUT[183]
    DIRECTION OUTPUT ;
    USE SIGNAL ;
    PORT
      LAYER Metal2 ;
        RECT 1578.235 2.425 1578.515 2.705 ;
    END
  END COLUMN_OUT[183]

  PIN COLUMN_OUT[184]
    DIRECTION OUTPUT ;
    USE SIGNAL ;
    PORT
      LAYER Metal2 ;
        RECT 1586.815 2.425 1587.095 2.705 ;
    END
  END COLUMN_OUT[184]

  PIN COLUMN_OUT[185]
    DIRECTION OUTPUT ;
    USE SIGNAL ;
    PORT
      LAYER Metal2 ;
        RECT 1595.395 2.425 1595.675 2.705 ;
    END
  END COLUMN_OUT[185]

  PIN COLUMN_OUT[186]
    DIRECTION OUTPUT ;
    USE SIGNAL ;
    PORT
      LAYER Metal2 ;
        RECT 1603.975 2.425 1604.255 2.705 ;
    END
  END COLUMN_OUT[186]

  PIN COLUMN_OUT[187]
    DIRECTION OUTPUT ;
    USE SIGNAL ;
    PORT
      LAYER Metal2 ;
        RECT 1612.555 2.425 1612.835 2.705 ;
    END
  END COLUMN_OUT[187]

  PIN COLUMN_OUT[188]
    DIRECTION OUTPUT ;
    USE SIGNAL ;
    PORT
      LAYER Metal2 ;
        RECT 1621.135 2.425 1621.415 2.705 ;
    END
  END COLUMN_OUT[188]

  PIN COLUMN_OUT[189]
    DIRECTION OUTPUT ;
    USE SIGNAL ;
    PORT
      LAYER Metal2 ;
        RECT 1629.715 2.425 1629.995 2.705 ;
    END
  END COLUMN_OUT[189]

  PIN COLUMN_OUT[190]
    DIRECTION OUTPUT ;
    USE SIGNAL ;
    PORT
      LAYER Metal2 ;
        RECT 1638.295 2.425 1638.575 2.705 ;
    END
  END COLUMN_OUT[190]

  PIN COLUMN_OUT[191]
    DIRECTION OUTPUT ;
    USE SIGNAL ;
    PORT
      LAYER Metal2 ;
        RECT 1646.875 2.425 1647.155 2.705 ;
    END
  END COLUMN_OUT[191]

  PIN COLUMN_OUT[192]
    DIRECTION OUTPUT ;
    USE SIGNAL ;
    PORT
      LAYER Metal2 ;
        RECT 1655.455 2.425 1655.735 2.705 ;
    END
  END COLUMN_OUT[192]

  PIN COLUMN_OUT[193]
    DIRECTION OUTPUT ;
    USE SIGNAL ;
    PORT
      LAYER Metal2 ;
        RECT 1664.035 2.425 1664.315 2.705 ;
    END
  END COLUMN_OUT[193]

  PIN COLUMN_OUT[194]
    DIRECTION OUTPUT ;
    USE SIGNAL ;
    PORT
      LAYER Metal2 ;
        RECT 1672.615 2.425 1672.895 2.705 ;
    END
  END COLUMN_OUT[194]

  PIN COLUMN_OUT[195]
    DIRECTION OUTPUT ;
    USE SIGNAL ;
    PORT
      LAYER Metal2 ;
        RECT 1681.195 2.425 1681.475 2.705 ;
    END
  END COLUMN_OUT[195]

  PIN COLUMN_OUT[196]
    DIRECTION OUTPUT ;
    USE SIGNAL ;
    PORT
      LAYER Metal2 ;
        RECT 1689.775 2.425 1690.055 2.705 ;
    END
  END COLUMN_OUT[196]

  PIN COLUMN_OUT[197]
    DIRECTION OUTPUT ;
    USE SIGNAL ;
    PORT
      LAYER Metal2 ;
        RECT 1698.355 2.425 1698.635 2.705 ;
    END
  END COLUMN_OUT[197]

  PIN COLUMN_OUT[198]
    DIRECTION OUTPUT ;
    USE SIGNAL ;
    PORT
      LAYER Metal2 ;
        RECT 1706.935 2.425 1707.215 2.705 ;
    END
  END COLUMN_OUT[198]

  PIN COLUMN_OUT[199]
    DIRECTION OUTPUT ;
    USE SIGNAL ;
    PORT
      LAYER Metal2 ;
        RECT 1715.515 2.425 1715.795 2.705 ;
    END
  END COLUMN_OUT[199]

  PIN COLUMN_OUT[200]
    DIRECTION OUTPUT ;
    USE SIGNAL ;
    PORT
      LAYER Metal2 ;
        RECT 1724.095 2.425 1724.375 2.705 ;
    END
  END COLUMN_OUT[200]

  PIN COLUMN_OUT[201]
    DIRECTION OUTPUT ;
    USE SIGNAL ;
    PORT
      LAYER Metal2 ;
        RECT 1732.675 2.425 1732.955 2.705 ;
    END
  END COLUMN_OUT[201]

  PIN COLUMN_OUT[202]
    DIRECTION OUTPUT ;
    USE SIGNAL ;
    PORT
      LAYER Metal2 ;
        RECT 1741.255 2.425 1741.535 2.705 ;
    END
  END COLUMN_OUT[202]

  PIN COLUMN_OUT[203]
    DIRECTION OUTPUT ;
    USE SIGNAL ;
    PORT
      LAYER Metal2 ;
        RECT 1749.835 2.425 1750.115 2.705 ;
    END
  END COLUMN_OUT[203]

  PIN COLUMN_OUT[204]
    DIRECTION OUTPUT ;
    USE SIGNAL ;
    PORT
      LAYER Metal2 ;
        RECT 1758.415 2.425 1758.695 2.705 ;
    END
  END COLUMN_OUT[204]

  PIN COLUMN_OUT[205]
    DIRECTION OUTPUT ;
    USE SIGNAL ;
    PORT
      LAYER Metal2 ;
        RECT 1766.995 2.425 1767.275 2.705 ;
    END
  END COLUMN_OUT[205]

  PIN COLUMN_OUT[206]
    DIRECTION OUTPUT ;
    USE SIGNAL ;
    PORT
      LAYER Metal2 ;
        RECT 1775.575 2.425 1775.855 2.705 ;
    END
  END COLUMN_OUT[206]

  PIN COLUMN_OUT[207]
    DIRECTION OUTPUT ;
    USE SIGNAL ;
    PORT
      LAYER Metal2 ;
        RECT 1784.155 2.425 1784.435 2.705 ;
    END
  END COLUMN_OUT[207]

  PIN COLUMN_OUT[208]
    DIRECTION OUTPUT ;
    USE SIGNAL ;
    PORT
      LAYER Metal2 ;
        RECT 1792.735 2.425 1793.015 2.705 ;
    END
  END COLUMN_OUT[208]

  PIN COLUMN_OUT[209]
    DIRECTION OUTPUT ;
    USE SIGNAL ;
    PORT
      LAYER Metal2 ;
        RECT 1801.315 2.425 1801.595 2.705 ;
    END
  END COLUMN_OUT[209]

  PIN COLUMN_OUT[210]
    DIRECTION OUTPUT ;
    USE SIGNAL ;
    PORT
      LAYER Metal2 ;
        RECT 1809.895 2.425 1810.175 2.705 ;
    END
  END COLUMN_OUT[210]

  PIN COLUMN_OUT[211]
    DIRECTION OUTPUT ;
    USE SIGNAL ;
    PORT
      LAYER Metal2 ;
        RECT 1818.475 2.425 1818.755 2.705 ;
    END
  END COLUMN_OUT[211]

  PIN COLUMN_OUT[212]
    DIRECTION OUTPUT ;
    USE SIGNAL ;
    PORT
      LAYER Metal2 ;
        RECT 1827.055 2.425 1827.335 2.705 ;
    END
  END COLUMN_OUT[212]

  PIN COLUMN_OUT[213]
    DIRECTION OUTPUT ;
    USE SIGNAL ;
    PORT
      LAYER Metal2 ;
        RECT 1835.635 2.425 1835.915 2.705 ;
    END
  END COLUMN_OUT[213]

  PIN COLUMN_OUT[214]
    DIRECTION OUTPUT ;
    USE SIGNAL ;
    PORT
      LAYER Metal2 ;
        RECT 1844.215 2.425 1844.495 2.705 ;
    END
  END COLUMN_OUT[214]

  PIN COLUMN_OUT[215]
    DIRECTION OUTPUT ;
    USE SIGNAL ;
    PORT
      LAYER Metal2 ;
        RECT 1852.795 2.425 1853.075 2.705 ;
    END
  END COLUMN_OUT[215]

  PIN COLUMN_OUT[216]
    DIRECTION OUTPUT ;
    USE SIGNAL ;
    PORT
      LAYER Metal2 ;
        RECT 1861.375 2.425 1861.655 2.705 ;
    END
  END COLUMN_OUT[216]

  PIN COLUMN_OUT[217]
    DIRECTION OUTPUT ;
    USE SIGNAL ;
    PORT
      LAYER Metal2 ;
        RECT 1869.955 2.425 1870.235 2.705 ;
    END
  END COLUMN_OUT[217]

  PIN COLUMN_OUT[218]
    DIRECTION OUTPUT ;
    USE SIGNAL ;
    PORT
      LAYER Metal2 ;
        RECT 1878.535 2.425 1878.815 2.705 ;
    END
  END COLUMN_OUT[218]

  PIN COLUMN_OUT[219]
    DIRECTION OUTPUT ;
    USE SIGNAL ;
    PORT
      LAYER Metal2 ;
        RECT 1887.115 2.425 1887.395 2.705 ;
    END
  END COLUMN_OUT[219]

  PIN COLUMN_OUT[220]
    DIRECTION OUTPUT ;
    USE SIGNAL ;
    PORT
      LAYER Metal2 ;
        RECT 1895.695 2.425 1895.975 2.705 ;
    END
  END COLUMN_OUT[220]

  PIN COLUMN_OUT[221]
    DIRECTION OUTPUT ;
    USE SIGNAL ;
    PORT
      LAYER Metal2 ;
        RECT 1904.275 2.425 1904.555 2.705 ;
    END
  END COLUMN_OUT[221]

  PIN COLUMN_OUT[222]
    DIRECTION OUTPUT ;
    USE SIGNAL ;
    PORT
      LAYER Metal2 ;
        RECT 1912.855 2.425 1913.135 2.705 ;
    END
  END COLUMN_OUT[222]

  PIN COLUMN_OUT[223]
    DIRECTION OUTPUT ;
    USE SIGNAL ;
    PORT
      LAYER Metal2 ;
        RECT 1921.435 2.425 1921.715 2.705 ;
    END
  END COLUMN_OUT[223]

  PIN COLUMN_OUT[224]
    DIRECTION OUTPUT ;
    USE SIGNAL ;
    PORT
      LAYER Metal2 ;
        RECT 1930.015 2.425 1930.295 2.705 ;
    END
  END COLUMN_OUT[224]

  PIN COLUMN_OUT[225]
    DIRECTION OUTPUT ;
    USE SIGNAL ;
    PORT
      LAYER Metal2 ;
        RECT 1938.595 2.425 1938.875 2.705 ;
    END
  END COLUMN_OUT[225]

  PIN COLUMN_OUT[226]
    DIRECTION OUTPUT ;
    USE SIGNAL ;
    PORT
      LAYER Metal2 ;
        RECT 1947.175 2.425 1947.455 2.705 ;
    END
  END COLUMN_OUT[226]

  PIN COLUMN_OUT[227]
    DIRECTION OUTPUT ;
    USE SIGNAL ;
    PORT
      LAYER Metal2 ;
        RECT 1955.755 2.425 1956.035 2.705 ;
    END
  END COLUMN_OUT[227]

  PIN COLUMN_OUT[228]
    DIRECTION OUTPUT ;
    USE SIGNAL ;
    PORT
      LAYER Metal2 ;
        RECT 1964.335 2.425 1964.615 2.705 ;
    END
  END COLUMN_OUT[228]

  PIN COLUMN_OUT[229]
    DIRECTION OUTPUT ;
    USE SIGNAL ;
    PORT
      LAYER Metal2 ;
        RECT 1972.915 2.425 1973.195 2.705 ;
    END
  END COLUMN_OUT[229]

  PIN COLUMN_OUT[230]
    DIRECTION OUTPUT ;
    USE SIGNAL ;
    PORT
      LAYER Metal2 ;
        RECT 1981.495 2.425 1981.775 2.705 ;
    END
  END COLUMN_OUT[230]

  PIN COLUMN_OUT[231]
    DIRECTION OUTPUT ;
    USE SIGNAL ;
    PORT
      LAYER Metal2 ;
        RECT 1990.075 2.425 1990.355 2.705 ;
    END
  END COLUMN_OUT[231]

  PIN COLUMN_OUT[232]
    DIRECTION OUTPUT ;
    USE SIGNAL ;
    PORT
      LAYER Metal2 ;
        RECT 1998.655 2.425 1998.935 2.705 ;
    END
  END COLUMN_OUT[232]

  PIN COLUMN_OUT[233]
    DIRECTION OUTPUT ;
    USE SIGNAL ;
    PORT
      LAYER Metal2 ;
        RECT 2007.235 2.425 2007.515 2.705 ;
    END
  END COLUMN_OUT[233]

  PIN COLUMN_OUT[234]
    DIRECTION OUTPUT ;
    USE SIGNAL ;
    PORT
      LAYER Metal2 ;
        RECT 2015.815 2.425 2016.095 2.705 ;
    END
  END COLUMN_OUT[234]

  PIN COLUMN_OUT[235]
    DIRECTION OUTPUT ;
    USE SIGNAL ;
    PORT
      LAYER Metal2 ;
        RECT 2024.395 2.425 2024.675 2.705 ;
    END
  END COLUMN_OUT[235]

  PIN COLUMN_OUT[236]
    DIRECTION OUTPUT ;
    USE SIGNAL ;
    PORT
      LAYER Metal2 ;
        RECT 2032.975 2.425 2033.255 2.705 ;
    END
  END COLUMN_OUT[236]

  PIN COLUMN_OUT[237]
    DIRECTION OUTPUT ;
    USE SIGNAL ;
    PORT
      LAYER Metal2 ;
        RECT 2041.555 2.425 2041.835 2.705 ;
    END
  END COLUMN_OUT[237]

  PIN COLUMN_OUT[238]
    DIRECTION OUTPUT ;
    USE SIGNAL ;
    PORT
      LAYER Metal2 ;
        RECT 2050.135 2.425 2050.415 2.705 ;
    END
  END COLUMN_OUT[238]

  PIN COLUMN_OUT[239]
    DIRECTION OUTPUT ;
    USE SIGNAL ;
    PORT
      LAYER Metal2 ;
        RECT 2058.715 2.425 2058.995 2.705 ;
    END
  END COLUMN_OUT[239]

  PIN COLUMN_OUT[240]
    DIRECTION OUTPUT ;
    USE SIGNAL ;
    PORT
      LAYER Metal2 ;
        RECT 2067.295 2.425 2067.575 2.705 ;
    END
  END COLUMN_OUT[240]

  PIN COLUMN_OUT[241]
    DIRECTION OUTPUT ;
    USE SIGNAL ;
    PORT
      LAYER Metal2 ;
        RECT 2075.875 2.425 2076.155 2.705 ;
    END
  END COLUMN_OUT[241]

  PIN COLUMN_OUT[242]
    DIRECTION OUTPUT ;
    USE SIGNAL ;
    PORT
      LAYER Metal2 ;
        RECT 2084.455 2.425 2084.735 2.705 ;
    END
  END COLUMN_OUT[242]

  PIN COLUMN_OUT[243]
    DIRECTION OUTPUT ;
    USE SIGNAL ;
    PORT
      LAYER Metal2 ;
        RECT 2093.035 2.425 2093.315 2.705 ;
    END
  END COLUMN_OUT[243]

  PIN COLUMN_OUT[244]
    DIRECTION OUTPUT ;
    USE SIGNAL ;
    PORT
      LAYER Metal2 ;
        RECT 2101.615 2.425 2101.895 2.705 ;
    END
  END COLUMN_OUT[244]

  PIN COLUMN_OUT[245]
    DIRECTION OUTPUT ;
    USE SIGNAL ;
    PORT
      LAYER Metal2 ;
        RECT 2110.195 2.425 2110.475 2.705 ;
    END
  END COLUMN_OUT[245]

  PIN COLUMN_OUT[246]
    DIRECTION OUTPUT ;
    USE SIGNAL ;
    PORT
      LAYER Metal2 ;
        RECT 2118.775 2.425 2119.055 2.705 ;
    END
  END COLUMN_OUT[246]

  PIN COLUMN_OUT[247]
    DIRECTION OUTPUT ;
    USE SIGNAL ;
    PORT
      LAYER Metal2 ;
        RECT 2127.355 2.425 2127.635 2.705 ;
    END
  END COLUMN_OUT[247]

  PIN COLUMN_OUT[248]
    DIRECTION OUTPUT ;
    USE SIGNAL ;
    PORT
      LAYER Metal2 ;
        RECT 2135.935 2.425 2136.215 2.705 ;
    END
  END COLUMN_OUT[248]

  PIN COLUMN_OUT[249]
    DIRECTION OUTPUT ;
    USE SIGNAL ;
    PORT
      LAYER Metal2 ;
        RECT 2144.515 2.425 2144.795 2.705 ;
    END
  END COLUMN_OUT[249]

  PIN COLUMN_OUT[250]
    DIRECTION OUTPUT ;
    USE SIGNAL ;
    PORT
      LAYER Metal2 ;
        RECT 2153.095 2.425 2153.375 2.705 ;
    END
  END COLUMN_OUT[250]

  PIN COLUMN_OUT[251]
    DIRECTION OUTPUT ;
    USE SIGNAL ;
    PORT
      LAYER Metal2 ;
        RECT 2161.675 2.425 2161.955 2.705 ;
    END
  END COLUMN_OUT[251]

  PIN COLUMN_OUT[252]
    DIRECTION OUTPUT ;
    USE SIGNAL ;
    PORT
      LAYER Metal2 ;
        RECT 2170.255 2.425 2170.535 2.705 ;
    END
  END COLUMN_OUT[252]

  PIN COLUMN_OUT[253]
    DIRECTION OUTPUT ;
    USE SIGNAL ;
    PORT
      LAYER Metal2 ;
        RECT 2178.835 2.425 2179.115 2.705 ;
    END
  END COLUMN_OUT[253]

  PIN COLUMN_OUT[254]
    DIRECTION OUTPUT ;
    USE SIGNAL ;
    PORT
      LAYER Metal2 ;
        RECT 2187.415 2.425 2187.695 2.705 ;
    END
  END COLUMN_OUT[254]

  PIN COLUMN_OUT[255]
    DIRECTION OUTPUT ;
    USE SIGNAL ;
    PORT
      LAYER Metal2 ;
        RECT 2195.995 2.425 2196.275 2.705 ;
    END
  END COLUMN_OUT[255]

  PIN COLUMN_OUT[256]
    DIRECTION OUTPUT ;
    USE SIGNAL ;
    PORT
      LAYER Metal2 ;
        RECT 2204.575 2.425 2204.855 2.705 ;
    END
  END COLUMN_OUT[256]

  PIN COLUMN_OUT[257]
    DIRECTION OUTPUT ;
    USE SIGNAL ;
    PORT
      LAYER Metal2 ;
        RECT 2213.155 2.425 2213.435 2.705 ;
    END
  END COLUMN_OUT[257]

  PIN COLUMN_OUT[258]
    DIRECTION OUTPUT ;
    USE SIGNAL ;
    PORT
      LAYER Metal2 ;
        RECT 2221.735 2.425 2222.015 2.705 ;
    END
  END COLUMN_OUT[258]

  PIN COLUMN_OUT[259]
    DIRECTION OUTPUT ;
    USE SIGNAL ;
    PORT
      LAYER Metal2 ;
        RECT 2230.315 2.425 2230.595 2.705 ;
    END
  END COLUMN_OUT[259]

  PIN COLUMN_OUT[260]
    DIRECTION OUTPUT ;
    USE SIGNAL ;
    PORT
      LAYER Metal2 ;
        RECT 2238.895 2.425 2239.175 2.705 ;
    END
  END COLUMN_OUT[260]

  PIN COLUMN_OUT[261]
    DIRECTION OUTPUT ;
    USE SIGNAL ;
    PORT
      LAYER Metal2 ;
        RECT 2247.475 2.425 2247.755 2.705 ;
    END
  END COLUMN_OUT[261]

  PIN COLUMN_OUT[262]
    DIRECTION OUTPUT ;
    USE SIGNAL ;
    PORT
      LAYER Metal2 ;
        RECT 2256.055 2.425 2256.335 2.705 ;
    END
  END COLUMN_OUT[262]

  PIN COLUMN_OUT[263]
    DIRECTION OUTPUT ;
    USE SIGNAL ;
    PORT
      LAYER Metal2 ;
        RECT 2264.635 2.425 2264.915 2.705 ;
    END
  END COLUMN_OUT[263]

  PIN COLUMN_OUT[264]
    DIRECTION OUTPUT ;
    USE SIGNAL ;
    PORT
      LAYER Metal2 ;
        RECT 2273.215 2.425 2273.495 2.705 ;
    END
  END COLUMN_OUT[264]

  PIN COLUMN_OUT[265]
    DIRECTION OUTPUT ;
    USE SIGNAL ;
    PORT
      LAYER Metal2 ;
        RECT 2281.795 2.425 2282.075 2.705 ;
    END
  END COLUMN_OUT[265]

  PIN COLUMN_OUT[266]
    DIRECTION OUTPUT ;
    USE SIGNAL ;
    PORT
      LAYER Metal2 ;
        RECT 2290.375 2.425 2290.655 2.705 ;
    END
  END COLUMN_OUT[266]

  PIN COLUMN_OUT[267]
    DIRECTION OUTPUT ;
    USE SIGNAL ;
    PORT
      LAYER Metal2 ;
        RECT 2298.955 2.425 2299.235 2.705 ;
    END
  END COLUMN_OUT[267]

  PIN COLUMN_OUT[268]
    DIRECTION OUTPUT ;
    USE SIGNAL ;
    PORT
      LAYER Metal2 ;
        RECT 2307.535 2.425 2307.815 2.705 ;
    END
  END COLUMN_OUT[268]

  PIN COLUMN_OUT[269]
    DIRECTION OUTPUT ;
    USE SIGNAL ;
    PORT
      LAYER Metal2 ;
        RECT 2316.115 2.425 2316.395 2.705 ;
    END
  END COLUMN_OUT[269]

  PIN COLUMN_OUT[270]
    DIRECTION OUTPUT ;
    USE SIGNAL ;
    PORT
      LAYER Metal2 ;
        RECT 2324.695 2.425 2324.975 2.705 ;
    END
  END COLUMN_OUT[270]

  PIN COLUMN_OUT[271]
    DIRECTION OUTPUT ;
    USE SIGNAL ;
    PORT
      LAYER Metal2 ;
        RECT 2333.275 2.425 2333.555 2.705 ;
    END
  END COLUMN_OUT[271]

  PIN COLUMN_OUT[272]
    DIRECTION OUTPUT ;
    USE SIGNAL ;
    PORT
      LAYER Metal2 ;
        RECT 2341.855 2.425 2342.135 2.705 ;
    END
  END COLUMN_OUT[272]

  PIN COLUMN_OUT[273]
    DIRECTION OUTPUT ;
    USE SIGNAL ;
    PORT
      LAYER Metal2 ;
        RECT 2350.435 2.425 2350.715 2.705 ;
    END
  END COLUMN_OUT[273]

  PIN COLUMN_OUT[274]
    DIRECTION OUTPUT ;
    USE SIGNAL ;
    PORT
      LAYER Metal2 ;
        RECT 2359.015 2.425 2359.295 2.705 ;
    END
  END COLUMN_OUT[274]

  PIN COLUMN_OUT[275]
    DIRECTION OUTPUT ;
    USE SIGNAL ;
    PORT
      LAYER Metal2 ;
        RECT 2367.595 2.425 2367.875 2.705 ;
    END
  END COLUMN_OUT[275]

  PIN COLUMN_OUT[276]
    DIRECTION OUTPUT ;
    USE SIGNAL ;
    PORT
      LAYER Metal2 ;
        RECT 2376.175 2.425 2376.455 2.705 ;
    END
  END COLUMN_OUT[276]

  PIN COLUMN_OUT[277]
    DIRECTION OUTPUT ;
    USE SIGNAL ;
    PORT
      LAYER Metal2 ;
        RECT 2384.755 2.425 2385.035 2.705 ;
    END
  END COLUMN_OUT[277]

  PIN COLUMN_OUT[278]
    DIRECTION OUTPUT ;
    USE SIGNAL ;
    PORT
      LAYER Metal2 ;
        RECT 2393.335 2.425 2393.615 2.705 ;
    END
  END COLUMN_OUT[278]

  PIN COLUMN_OUT[279]
    DIRECTION OUTPUT ;
    USE SIGNAL ;
    PORT
      LAYER Metal2 ;
        RECT 2401.915 2.425 2402.195 2.705 ;
    END
  END COLUMN_OUT[279]

  PIN COLUMN_OUT[280]
    DIRECTION OUTPUT ;
    USE SIGNAL ;
    PORT
      LAYER Metal2 ;
        RECT 2410.495 2.425 2410.775 2.705 ;
    END
  END COLUMN_OUT[280]

  PIN COLUMN_OUT[281]
    DIRECTION OUTPUT ;
    USE SIGNAL ;
    PORT
      LAYER Metal2 ;
        RECT 2419.075 2.425 2419.355 2.705 ;
    END
  END COLUMN_OUT[281]

  PIN COLUMN_OUT[282]
    DIRECTION OUTPUT ;
    USE SIGNAL ;
    PORT
      LAYER Metal2 ;
        RECT 2427.655 2.425 2427.935 2.705 ;
    END
  END COLUMN_OUT[282]

  PIN COLUMN_OUT[283]
    DIRECTION OUTPUT ;
    USE SIGNAL ;
    PORT
      LAYER Metal2 ;
        RECT 2436.235 2.425 2436.515 2.705 ;
    END
  END COLUMN_OUT[283]

  PIN COLUMN_OUT[284]
    DIRECTION OUTPUT ;
    USE SIGNAL ;
    PORT
      LAYER Metal2 ;
        RECT 2444.815 2.425 2445.095 2.705 ;
    END
  END COLUMN_OUT[284]

  PIN COLUMN_OUT[285]
    DIRECTION OUTPUT ;
    USE SIGNAL ;
    PORT
      LAYER Metal2 ;
        RECT 2453.395 2.425 2453.675 2.705 ;
    END
  END COLUMN_OUT[285]

  PIN COLUMN_OUT[286]
    DIRECTION OUTPUT ;
    USE SIGNAL ;
    PORT
      LAYER Metal2 ;
        RECT 2461.975 2.425 2462.255 2.705 ;
    END
  END COLUMN_OUT[286]

  PIN COLUMN_OUT[287]
    DIRECTION OUTPUT ;
    USE SIGNAL ;
    PORT
      LAYER Metal2 ;
        RECT 2470.555 2.425 2470.835 2.705 ;
    END
  END COLUMN_OUT[287]

  PIN COLUMN_OUT[288]
    DIRECTION OUTPUT ;
    USE SIGNAL ;
    PORT
      LAYER Metal2 ;
        RECT 2479.135 2.425 2479.415 2.705 ;
    END
  END COLUMN_OUT[288]

  PIN COLUMN_OUT[289]
    DIRECTION OUTPUT ;
    USE SIGNAL ;
    PORT
      LAYER Metal2 ;
        RECT 2487.715 2.425 2487.995 2.705 ;
    END
  END COLUMN_OUT[289]

  PIN COLUMN_OUT[290]
    DIRECTION OUTPUT ;
    USE SIGNAL ;
    PORT
      LAYER Metal2 ;
        RECT 2496.295 2.425 2496.575 2.705 ;
    END
  END COLUMN_OUT[290]

  PIN COLUMN_OUT[291]
    DIRECTION OUTPUT ;
    USE SIGNAL ;
    PORT
      LAYER Metal2 ;
        RECT 2504.875 2.425 2505.155 2.705 ;
    END
  END COLUMN_OUT[291]

  PIN COLUMN_OUT[292]
    DIRECTION OUTPUT ;
    USE SIGNAL ;
    PORT
      LAYER Metal2 ;
        RECT 2513.455 2.425 2513.735 2.705 ;
    END
  END COLUMN_OUT[292]

  PIN COLUMN_OUT[293]
    DIRECTION OUTPUT ;
    USE SIGNAL ;
    PORT
      LAYER Metal2 ;
        RECT 2522.035 2.425 2522.315 2.705 ;
    END
  END COLUMN_OUT[293]

  PIN COLUMN_OUT[294]
    DIRECTION OUTPUT ;
    USE SIGNAL ;
    PORT
      LAYER Metal2 ;
        RECT 2530.615 2.425 2530.895 2.705 ;
    END
  END COLUMN_OUT[294]

  PIN COLUMN_OUT[295]
    DIRECTION OUTPUT ;
    USE SIGNAL ;
    PORT
      LAYER Metal2 ;
        RECT 2539.195 2.425 2539.475 2.705 ;
    END
  END COLUMN_OUT[295]

  PIN COLUMN_OUT[296]
    DIRECTION OUTPUT ;
    USE SIGNAL ;
    PORT
      LAYER Metal2 ;
        RECT 2547.775 2.425 2548.055 2.705 ;
    END
  END COLUMN_OUT[296]

  PIN COLUMN_OUT[297]
    DIRECTION OUTPUT ;
    USE SIGNAL ;
    PORT
      LAYER Metal2 ;
        RECT 2556.355 2.425 2556.635 2.705 ;
    END
  END COLUMN_OUT[297]

  PIN COLUMN_OUT[298]
    DIRECTION OUTPUT ;
    USE SIGNAL ;
    PORT
      LAYER Metal2 ;
        RECT 2564.935 2.425 2565.215 2.705 ;
    END
  END COLUMN_OUT[298]

  PIN COLUMN_OUT[299]
    DIRECTION OUTPUT ;
    USE SIGNAL ;
    PORT
      LAYER Metal2 ;
        RECT 2573.515 2.425 2573.795 2.705 ;
    END
  END COLUMN_OUT[299]

  PIN COLUMN_OUT[300]
    DIRECTION OUTPUT ;
    USE SIGNAL ;
    PORT
      LAYER Metal2 ;
        RECT 2582.095 2.425 2582.375 2.705 ;
    END
  END COLUMN_OUT[300]

  PIN COLUMN_OUT[301]
    DIRECTION OUTPUT ;
    USE SIGNAL ;
    PORT
      LAYER Metal2 ;
        RECT 2590.675 2.425 2590.955 2.705 ;
    END
  END COLUMN_OUT[301]

  PIN COLUMN_OUT[302]
    DIRECTION OUTPUT ;
    USE SIGNAL ;
    PORT
      LAYER Metal2 ;
        RECT 2599.255 2.425 2599.535 2.705 ;
    END
  END COLUMN_OUT[302]

  PIN COLUMN_OUT[303]
    DIRECTION OUTPUT ;
    USE SIGNAL ;
    PORT
      LAYER Metal2 ;
        RECT 2607.835 2.425 2608.115 2.705 ;
    END
  END COLUMN_OUT[303]

  PIN COLUMN_OUT[304]
    DIRECTION OUTPUT ;
    USE SIGNAL ;
    PORT
      LAYER Metal2 ;
        RECT 2616.415 2.425 2616.695 2.705 ;
    END
  END COLUMN_OUT[304]

  PIN COLUMN_OUT[305]
    DIRECTION OUTPUT ;
    USE SIGNAL ;
    PORT
      LAYER Metal2 ;
        RECT 2624.995 2.425 2625.275 2.705 ;
    END
  END COLUMN_OUT[305]

  PIN COLUMN_OUT[306]
    DIRECTION OUTPUT ;
    USE SIGNAL ;
    PORT
      LAYER Metal2 ;
        RECT 2633.575 2.425 2633.855 2.705 ;
    END
  END COLUMN_OUT[306]

  PIN COLUMN_OUT[307]
    DIRECTION OUTPUT ;
    USE SIGNAL ;
    PORT
      LAYER Metal2 ;
        RECT 2642.155 2.425 2642.435 2.705 ;
    END
  END COLUMN_OUT[307]

  PIN COLUMN_OUT[308]
    DIRECTION OUTPUT ;
    USE SIGNAL ;
    PORT
      LAYER Metal2 ;
        RECT 2650.735 2.425 2651.015 2.705 ;
    END
  END COLUMN_OUT[308]

  PIN COLUMN_OUT[309]
    DIRECTION OUTPUT ;
    USE SIGNAL ;
    PORT
      LAYER Metal2 ;
        RECT 2659.315 2.425 2659.595 2.705 ;
    END
  END COLUMN_OUT[309]

  PIN COLUMN_OUT[310]
    DIRECTION OUTPUT ;
    USE SIGNAL ;
    PORT
      LAYER Metal2 ;
        RECT 2667.895 2.425 2668.175 2.705 ;
    END
  END COLUMN_OUT[310]

  PIN COLUMN_OUT[311]
    DIRECTION OUTPUT ;
    USE SIGNAL ;
    PORT
      LAYER Metal2 ;
        RECT 2676.475 2.425 2676.755 2.705 ;
    END
  END COLUMN_OUT[311]

  PIN COLUMN_OUT[312]
    DIRECTION OUTPUT ;
    USE SIGNAL ;
    PORT
      LAYER Metal2 ;
        RECT 2685.055 2.425 2685.335 2.705 ;
    END
  END COLUMN_OUT[312]

  PIN COLUMN_OUT[313]
    DIRECTION OUTPUT ;
    USE SIGNAL ;
    PORT
      LAYER Metal2 ;
        RECT 2693.635 2.425 2693.915 2.705 ;
    END
  END COLUMN_OUT[313]

  PIN COLUMN_OUT[314]
    DIRECTION OUTPUT ;
    USE SIGNAL ;
    PORT
      LAYER Metal2 ;
        RECT 2702.215 2.425 2702.495 2.705 ;
    END
  END COLUMN_OUT[314]

  PIN COLUMN_OUT[315]
    DIRECTION OUTPUT ;
    USE SIGNAL ;
    PORT
      LAYER Metal2 ;
        RECT 2710.795 2.425 2711.075 2.705 ;
    END
  END COLUMN_OUT[315]

  PIN COLUMN_OUT[316]
    DIRECTION OUTPUT ;
    USE SIGNAL ;
    PORT
      LAYER Metal2 ;
        RECT 2719.375 2.425 2719.655 2.705 ;
    END
  END COLUMN_OUT[316]

  PIN COLUMN_OUT[317]
    DIRECTION OUTPUT ;
    USE SIGNAL ;
    PORT
      LAYER Metal2 ;
        RECT 2727.955 2.425 2728.235 2.705 ;
    END
  END COLUMN_OUT[317]

  PIN COLUMN_OUT[318]
    DIRECTION OUTPUT ;
    USE SIGNAL ;
    PORT
      LAYER Metal2 ;
        RECT 2736.535 2.425 2736.815 2.705 ;
    END
  END COLUMN_OUT[318]

  PIN COLUMN_OUT[319]
    DIRECTION OUTPUT ;
    USE SIGNAL ;
    PORT
      LAYER Metal2 ;
        RECT 2745.115 2.425 2745.395 2.705 ;
    END
  END COLUMN_OUT[319]

  PIN COLUMN_OUT[320]
    DIRECTION OUTPUT ;
    USE SIGNAL ;
    PORT
      LAYER Metal2 ;
        RECT 2753.695 2.425 2753.975 2.705 ;
    END
  END COLUMN_OUT[320]

  PIN VDD
    DIRECTION INOUT ;
    USE POWER ;
    PORT
      LAYER Metal1 ;
        RECT 0.250 9.850 0.530 10.100 ;
    END
    PORT
      LAYER Metal1 ;
        RECT 0.250 18.430 0.530 18.680 ;
    END
    PORT
      LAYER Metal1 ;
        RECT 0.250 27.010 0.530 27.260 ;
    END
    PORT
      LAYER Metal1 ;
        RECT 0.250 35.590 0.530 35.840 ;
    END
    PORT
      LAYER Metal1 ;
        RECT 0.250 44.170 0.530 44.420 ;
    END
    PORT
      LAYER Metal1 ;
        RECT 0.250 52.750 0.530 53.000 ;
    END
    PORT
      LAYER Metal1 ;
        RECT 0.250 61.330 0.530 61.580 ;
    END
    PORT
      LAYER Metal1 ;
        RECT 0.250 69.910 0.530 70.160 ;
    END
    PORT
      LAYER Metal1 ;
        RECT 0.250 78.490 0.530 78.740 ;
    END
    PORT
      LAYER Metal1 ;
        RECT 0.250 87.070 0.530 87.320 ;
    END
    PORT
      LAYER Metal1 ;
        RECT 0.250 95.650 0.530 95.900 ;
    END
    PORT
      LAYER Metal1 ;
        RECT 0.250 104.230 0.530 104.480 ;
    END
    PORT
      LAYER Metal1 ;
        RECT 0.250 112.810 0.530 113.060 ;
    END
    PORT
      LAYER Metal1 ;
        RECT 0.250 121.390 0.530 121.640 ;
    END
    PORT
      LAYER Metal1 ;
        RECT 0.250 129.970 0.530 130.220 ;
    END
    PORT
      LAYER Metal1 ;
        RECT 0.250 138.550 0.530 138.800 ;
    END
    PORT
      LAYER Metal1 ;
        RECT 0.250 147.130 0.530 147.380 ;
    END
    PORT
      LAYER Metal1 ;
        RECT 0.250 155.710 0.530 155.960 ;
    END
    PORT
      LAYER Metal1 ;
        RECT 0.250 164.290 0.530 164.540 ;
    END
    PORT
      LAYER Metal1 ;
        RECT 0.250 172.870 0.530 173.120 ;
    END
    PORT
      LAYER Metal1 ;
        RECT 0.250 181.450 0.530 181.700 ;
    END
    PORT
      LAYER Metal1 ;
        RECT 0.250 190.030 0.530 190.280 ;
    END
    PORT
      LAYER Metal1 ;
        RECT 0.250 198.610 0.530 198.860 ;
    END
    PORT
      LAYER Metal1 ;
        RECT 0.250 207.190 0.530 207.440 ;
    END
    PORT
      LAYER Metal1 ;
        RECT 0.250 215.770 0.530 216.020 ;
    END
    PORT
      LAYER Metal1 ;
        RECT 0.250 224.350 0.530 224.600 ;
    END
    PORT
      LAYER Metal1 ;
        RECT 0.250 232.930 0.530 233.180 ;
    END
    PORT
      LAYER Metal1 ;
        RECT 0.250 241.510 0.530 241.760 ;
    END
    PORT
      LAYER Metal1 ;
        RECT 0.250 250.090 0.530 250.340 ;
    END
    PORT
      LAYER Metal1 ;
        RECT 0.250 258.670 0.530 258.920 ;
    END
    PORT
      LAYER Metal1 ;
        RECT 0.250 267.250 0.530 267.500 ;
    END
    PORT
      LAYER Metal1 ;
        RECT 0.250 275.830 0.530 276.080 ;
    END
    PORT
      LAYER Metal1 ;
        RECT 0.250 284.410 0.530 284.660 ;
    END
    PORT
      LAYER Metal1 ;
        RECT 0.250 292.990 0.530 293.240 ;
    END
    PORT
      LAYER Metal1 ;
        RECT 0.250 301.570 0.530 301.820 ;
    END
    PORT
      LAYER Metal1 ;
        RECT 0.250 310.150 0.530 310.400 ;
    END
    PORT
      LAYER Metal1 ;
        RECT 0.250 318.730 0.530 318.980 ;
    END
    PORT
      LAYER Metal1 ;
        RECT 0.250 327.310 0.530 327.560 ;
    END
    PORT
      LAYER Metal1 ;
        RECT 0.250 335.890 0.530 336.140 ;
    END
    PORT
      LAYER Metal1 ;
        RECT 0.250 344.470 0.530 344.720 ;
    END
    PORT
      LAYER Metal1 ;
        RECT 0.250 353.050 0.530 353.300 ;
    END
    PORT
      LAYER Metal1 ;
        RECT 0.250 361.630 0.530 361.880 ;
    END
    PORT
      LAYER Metal1 ;
        RECT 0.250 370.210 0.530 370.460 ;
    END
    PORT
      LAYER Metal1 ;
        RECT 0.250 378.790 0.530 379.040 ;
    END
    PORT
      LAYER Metal1 ;
        RECT 0.250 387.370 0.530 387.620 ;
    END
    PORT
      LAYER Metal1 ;
        RECT 0.250 395.950 0.530 396.200 ;
    END
    PORT
      LAYER Metal1 ;
        RECT 0.250 404.530 0.530 404.780 ;
    END
    PORT
      LAYER Metal1 ;
        RECT 0.250 413.110 0.530 413.360 ;
    END
    PORT
      LAYER Metal1 ;
        RECT 0.250 421.690 0.530 421.940 ;
    END
    PORT
      LAYER Metal1 ;
        RECT 0.250 430.270 0.530 430.520 ;
    END
    PORT
      LAYER Metal1 ;
        RECT 0.250 438.850 0.530 439.100 ;
    END
    PORT
      LAYER Metal1 ;
        RECT 0.250 447.430 0.530 447.680 ;
    END
    PORT
      LAYER Metal1 ;
        RECT 0.250 456.010 0.530 456.260 ;
    END
    PORT
      LAYER Metal1 ;
        RECT 0.250 464.590 0.530 464.840 ;
    END
    PORT
      LAYER Metal1 ;
        RECT 0.250 473.170 0.530 473.420 ;
    END
    PORT
      LAYER Metal1 ;
        RECT 0.250 481.750 0.530 482.000 ;
    END
    PORT
      LAYER Metal1 ;
        RECT 0.250 490.330 0.530 490.580 ;
    END
    PORT
      LAYER Metal1 ;
        RECT 0.250 498.910 0.530 499.160 ;
    END
    PORT
      LAYER Metal1 ;
        RECT 0.250 507.490 0.530 507.740 ;
    END
    PORT
      LAYER Metal1 ;
        RECT 0.250 516.070 0.530 516.320 ;
    END
    PORT
      LAYER Metal1 ;
        RECT 0.250 524.650 0.530 524.900 ;
    END
    PORT
      LAYER Metal1 ;
        RECT 0.250 533.230 0.530 533.480 ;
    END
    PORT
      LAYER Metal1 ;
        RECT 0.250 541.810 0.530 542.060 ;
    END
    PORT
      LAYER Metal1 ;
        RECT 0.250 550.390 0.530 550.640 ;
    END
    PORT
      LAYER Metal1 ;
        RECT 0.250 558.970 0.530 559.220 ;
    END
    PORT
      LAYER Metal1 ;
        RECT 0.250 567.550 0.530 567.800 ;
    END
    PORT
      LAYER Metal1 ;
        RECT 0.250 576.130 0.530 576.380 ;
    END
    PORT
      LAYER Metal1 ;
        RECT 0.250 584.710 0.530 584.960 ;
    END
    PORT
      LAYER Metal1 ;
        RECT 0.250 593.290 0.530 593.540 ;
    END
    PORT
      LAYER Metal1 ;
        RECT 0.250 601.870 0.530 602.120 ;
    END
    PORT
      LAYER Metal1 ;
        RECT 0.250 610.450 0.530 610.700 ;
    END
    PORT
      LAYER Metal1 ;
        RECT 0.250 619.030 0.530 619.280 ;
    END
    PORT
      LAYER Metal1 ;
        RECT 0.250 627.610 0.530 627.860 ;
    END
    PORT
      LAYER Metal1 ;
        RECT 0.250 636.190 0.530 636.440 ;
    END
    PORT
      LAYER Metal1 ;
        RECT 0.250 644.770 0.530 645.020 ;
    END
    PORT
      LAYER Metal1 ;
        RECT 0.250 653.350 0.530 653.600 ;
    END
    PORT
      LAYER Metal1 ;
        RECT 0.250 661.930 0.530 662.180 ;
    END
    PORT
      LAYER Metal1 ;
        RECT 0.250 670.510 0.530 670.760 ;
    END
    PORT
      LAYER Metal1 ;
        RECT 0.250 679.090 0.530 679.340 ;
    END
    PORT
      LAYER Metal1 ;
        RECT 0.250 687.670 0.530 687.920 ;
    END
    PORT
      LAYER Metal1 ;
        RECT 0.250 696.250 0.530 696.500 ;
    END
    PORT
      LAYER Metal1 ;
        RECT 0.250 704.830 0.530 705.080 ;
    END
    PORT
      LAYER Metal1 ;
        RECT 0.250 713.410 0.530 713.660 ;
    END
    PORT
      LAYER Metal1 ;
        RECT 0.250 721.990 0.530 722.240 ;
    END
    PORT
      LAYER Metal1 ;
        RECT 0.250 730.570 0.530 730.820 ;
    END
    PORT
      LAYER Metal1 ;
        RECT 0.250 739.150 0.530 739.400 ;
    END
    PORT
      LAYER Metal1 ;
        RECT 0.250 747.730 0.530 747.980 ;
    END
    PORT
      LAYER Metal1 ;
        RECT 0.250 756.310 0.530 756.560 ;
    END
    PORT
      LAYER Metal1 ;
        RECT 0.250 764.890 0.530 765.140 ;
    END
    PORT
      LAYER Metal1 ;
        RECT 0.250 773.470 0.530 773.720 ;
    END
    PORT
      LAYER Metal1 ;
        RECT 0.250 782.050 0.530 782.300 ;
    END
    PORT
      LAYER Metal1 ;
        RECT 0.250 790.630 0.530 790.880 ;
    END
    PORT
      LAYER Metal1 ;
        RECT 0.250 799.210 0.530 799.460 ;
    END
    PORT
      LAYER Metal1 ;
        RECT 0.250 807.790 0.530 808.040 ;
    END
    PORT
      LAYER Metal1 ;
        RECT 0.250 816.370 0.530 816.620 ;
    END
    PORT
      LAYER Metal1 ;
        RECT 0.250 824.950 0.530 825.200 ;
    END
    PORT
      LAYER Metal1 ;
        RECT 0.250 833.530 0.530 833.780 ;
    END
    PORT
      LAYER Metal1 ;
        RECT 0.250 842.110 0.530 842.360 ;
    END
    PORT
      LAYER Metal1 ;
        RECT 0.250 850.690 0.530 850.940 ;
    END
    PORT
      LAYER Metal1 ;
        RECT 0.250 859.270 0.530 859.520 ;
    END
    PORT
      LAYER Metal1 ;
        RECT 0.250 867.850 0.530 868.100 ;
    END
    PORT
      LAYER Metal1 ;
        RECT 0.250 876.430 0.530 876.680 ;
    END
    PORT
      LAYER Metal1 ;
        RECT 0.250 885.010 0.530 885.260 ;
    END
    PORT
      LAYER Metal1 ;
        RECT 0.250 893.590 0.530 893.840 ;
    END
    PORT
      LAYER Metal1 ;
        RECT 0.250 902.170 0.530 902.420 ;
    END
    PORT
      LAYER Metal1 ;
        RECT 0.250 910.750 0.530 911.000 ;
    END
    PORT
      LAYER Metal1 ;
        RECT 0.250 919.330 0.530 919.580 ;
    END
    PORT
      LAYER Metal1 ;
        RECT 0.250 927.910 0.530 928.160 ;
    END
    PORT
      LAYER Metal1 ;
        RECT 0.250 936.490 0.530 936.740 ;
    END
    PORT
      LAYER Metal1 ;
        RECT 0.250 945.070 0.530 945.320 ;
    END
    PORT
      LAYER Metal1 ;
        RECT 0.250 953.650 0.530 953.900 ;
    END
    PORT
      LAYER Metal1 ;
        RECT 0.250 962.230 0.530 962.480 ;
    END
    PORT
      LAYER Metal1 ;
        RECT 0.250 970.810 0.530 971.060 ;
    END
    PORT
      LAYER Metal1 ;
        RECT 0.250 979.390 0.530 979.640 ;
    END
    PORT
      LAYER Metal1 ;
        RECT 0.250 987.970 0.530 988.220 ;
    END
    PORT
      LAYER Metal1 ;
        RECT 0.250 996.550 0.530 996.800 ;
    END
    PORT
      LAYER Metal1 ;
        RECT 0.250 1005.130 0.530 1005.380 ;
    END
    PORT
      LAYER Metal1 ;
        RECT 0.250 1013.710 0.530 1013.960 ;
    END
    PORT
      LAYER Metal1 ;
        RECT 0.250 1022.290 0.530 1022.540 ;
    END
    PORT
      LAYER Metal1 ;
        RECT 0.250 1030.870 0.530 1031.120 ;
    END
    PORT
      LAYER Metal1 ;
        RECT 0.250 1039.450 0.530 1039.700 ;
    END
    PORT
      LAYER Metal1 ;
        RECT 0.250 1048.030 0.530 1048.280 ;
    END
    PORT
      LAYER Metal1 ;
        RECT 0.250 1056.610 0.530 1056.860 ;
    END
    PORT
      LAYER Metal1 ;
        RECT 0.250 1065.190 0.530 1065.440 ;
    END
    PORT
      LAYER Metal1 ;
        RECT 0.250 1073.770 0.530 1074.020 ;
    END
    PORT
      LAYER Metal1 ;
        RECT 0.250 1082.350 0.530 1082.600 ;
    END
    PORT
      LAYER Metal1 ;
        RECT 0.250 1090.930 0.530 1091.180 ;
    END
    PORT
      LAYER Metal1 ;
        RECT 0.250 1099.510 0.530 1099.760 ;
    END
    PORT
      LAYER Metal1 ;
        RECT 0.250 1108.090 0.530 1108.340 ;
    END
    PORT
      LAYER Metal1 ;
        RECT 0.250 1116.670 0.530 1116.920 ;
    END
    PORT
      LAYER Metal1 ;
        RECT 0.250 1125.250 0.530 1125.500 ;
    END
    PORT
      LAYER Metal1 ;
        RECT 0.250 1133.830 0.530 1134.080 ;
    END
    PORT
      LAYER Metal1 ;
        RECT 0.250 1142.410 0.530 1142.660 ;
    END
    PORT
      LAYER Metal1 ;
        RECT 0.250 1150.990 0.530 1151.240 ;
    END
    PORT
      LAYER Metal1 ;
        RECT 0.250 1159.570 0.530 1159.820 ;
    END
    PORT
      LAYER Metal1 ;
        RECT 0.250 1168.150 0.530 1168.400 ;
    END
    PORT
      LAYER Metal1 ;
        RECT 0.250 1176.730 0.530 1176.980 ;
    END
    PORT
      LAYER Metal1 ;
        RECT 0.250 1185.310 0.530 1185.560 ;
    END
    PORT
      LAYER Metal1 ;
        RECT 0.250 1193.890 0.530 1194.140 ;
    END
    PORT
      LAYER Metal1 ;
        RECT 0.250 1202.470 0.530 1202.720 ;
    END
    PORT
      LAYER Metal1 ;
        RECT 0.250 1211.050 0.530 1211.300 ;
    END
    PORT
      LAYER Metal1 ;
        RECT 0.250 1219.630 0.530 1219.880 ;
    END
    PORT
      LAYER Metal1 ;
        RECT 0.250 1228.210 0.530 1228.460 ;
    END
    PORT
      LAYER Metal1 ;
        RECT 0.250 1236.790 0.530 1237.040 ;
    END
    PORT
      LAYER Metal1 ;
        RECT 0.250 1245.370 0.530 1245.620 ;
    END
    PORT
      LAYER Metal1 ;
        RECT 0.250 1253.950 0.530 1254.200 ;
    END
    PORT
      LAYER Metal1 ;
        RECT 0.250 1262.530 0.530 1262.780 ;
    END
    PORT
      LAYER Metal1 ;
        RECT 0.250 1271.110 0.530 1271.360 ;
    END
    PORT
      LAYER Metal1 ;
        RECT 0.250 1279.690 0.530 1279.940 ;
    END
    PORT
      LAYER Metal1 ;
        RECT 0.250 1288.270 0.530 1288.520 ;
    END
    PORT
      LAYER Metal1 ;
        RECT 0.250 1296.850 0.530 1297.100 ;
    END
    PORT
      LAYER Metal1 ;
        RECT 0.250 1305.430 0.530 1305.680 ;
    END
    PORT
      LAYER Metal1 ;
        RECT 0.250 1314.010 0.530 1314.260 ;
    END
    PORT
      LAYER Metal1 ;
        RECT 0.250 1322.590 0.530 1322.840 ;
    END
    PORT
      LAYER Metal1 ;
        RECT 0.250 1331.170 0.530 1331.420 ;
    END
    PORT
      LAYER Metal1 ;
        RECT 0.250 1339.750 0.530 1340.000 ;
    END
    PORT
      LAYER Metal1 ;
        RECT 0.250 1348.330 0.530 1348.580 ;
    END
    PORT
      LAYER Metal1 ;
        RECT 0.250 1356.910 0.530 1357.160 ;
    END
    PORT
      LAYER Metal1 ;
        RECT 0.250 1365.490 0.530 1365.740 ;
    END
    PORT
      LAYER Metal1 ;
        RECT 0.250 1374.070 0.530 1374.320 ;
    END
    PORT
      LAYER Metal1 ;
        RECT 0.250 1382.650 0.530 1382.900 ;
    END
    PORT
      LAYER Metal1 ;
        RECT 0.250 1391.230 0.530 1391.480 ;
    END
    PORT
      LAYER Metal1 ;
        RECT 0.250 1399.810 0.530 1400.060 ;
    END
    PORT
      LAYER Metal1 ;
        RECT 0.250 1408.390 0.530 1408.640 ;
    END
    PORT
      LAYER Metal1 ;
        RECT 0.250 1416.970 0.530 1417.220 ;
    END
    PORT
      LAYER Metal1 ;
        RECT 0.250 1425.550 0.530 1425.800 ;
    END
    PORT
      LAYER Metal1 ;
        RECT 0.250 1434.130 0.530 1434.380 ;
    END
    PORT
      LAYER Metal1 ;
        RECT 0.250 1442.710 0.530 1442.960 ;
    END
    PORT
      LAYER Metal1 ;
        RECT 0.250 1451.290 0.530 1451.540 ;
    END
    PORT
      LAYER Metal1 ;
        RECT 0.250 1459.870 0.530 1460.120 ;
    END
    PORT
      LAYER Metal1 ;
        RECT 0.250 1468.450 0.530 1468.700 ;
    END
    PORT
      LAYER Metal1 ;
        RECT 0.250 1477.030 0.530 1477.280 ;
    END
    PORT
      LAYER Metal1 ;
        RECT 0.250 1485.610 0.530 1485.860 ;
    END
    PORT
      LAYER Metal1 ;
        RECT 0.250 1494.190 0.530 1494.440 ;
    END
    PORT
      LAYER Metal1 ;
        RECT 0.250 1502.770 0.530 1503.020 ;
    END
    PORT
      LAYER Metal1 ;
        RECT 0.250 1511.350 0.530 1511.600 ;
    END
    PORT
      LAYER Metal1 ;
        RECT 0.250 1519.930 0.530 1520.180 ;
    END
    PORT
      LAYER Metal1 ;
        RECT 0.250 1528.510 0.530 1528.760 ;
    END
    PORT
      LAYER Metal1 ;
        RECT 0.250 1537.090 0.530 1537.340 ;
    END
    PORT
      LAYER Metal1 ;
        RECT 0.250 1545.670 0.530 1545.920 ;
    END
    PORT
      LAYER Metal1 ;
        RECT 0.250 1554.250 0.530 1554.500 ;
    END
    PORT
      LAYER Metal1 ;
        RECT 0.250 1562.830 0.530 1563.080 ;
    END
    PORT
      LAYER Metal1 ;
        RECT 0.250 1571.410 0.530 1571.660 ;
    END
    PORT
      LAYER Metal1 ;
        RECT 0.250 1579.990 0.530 1580.240 ;
    END
    PORT
      LAYER Metal1 ;
        RECT 0.250 1588.570 0.530 1588.820 ;
    END
    PORT
      LAYER Metal1 ;
        RECT 0.250 1597.150 0.530 1597.400 ;
    END
    PORT
      LAYER Metal1 ;
        RECT 0.250 1605.730 0.530 1605.980 ;
    END
    PORT
      LAYER Metal1 ;
        RECT 0.250 1614.310 0.530 1614.560 ;
    END
    PORT
      LAYER Metal1 ;
        RECT 0.250 1622.890 0.530 1623.140 ;
    END
    PORT
      LAYER Metal1 ;
        RECT 0.250 1631.470 0.530 1631.720 ;
    END
    PORT
      LAYER Metal1 ;
        RECT 0.250 1640.050 0.530 1640.300 ;
    END
    PORT
      LAYER Metal1 ;
        RECT 0.250 1648.630 0.530 1648.880 ;
    END
    PORT
      LAYER Metal1 ;
        RECT 0.250 1657.210 0.530 1657.460 ;
    END
    PORT
      LAYER Metal1 ;
        RECT 0.250 1665.790 0.530 1666.040 ;
    END
    PORT
      LAYER Metal1 ;
        RECT 0.250 1674.370 0.530 1674.620 ;
    END
    PORT
      LAYER Metal1 ;
        RECT 0.250 1682.950 0.530 1683.200 ;
    END
    PORT
      LAYER Metal1 ;
        RECT 0.250 1691.530 0.530 1691.780 ;
    END
    PORT
      LAYER Metal1 ;
        RECT 0.250 1700.110 0.530 1700.360 ;
    END
    PORT
      LAYER Metal1 ;
        RECT 0.250 1708.690 0.530 1708.940 ;
    END
    PORT
      LAYER Metal1 ;
        RECT 0.250 1717.270 0.530 1717.520 ;
    END
    PORT
      LAYER Metal1 ;
        RECT 0.250 1725.850 0.530 1726.100 ;
    END
    PORT
      LAYER Metal1 ;
        RECT 0.250 1734.430 0.530 1734.680 ;
    END
    PORT
      LAYER Metal1 ;
        RECT 0.250 1743.010 0.530 1743.260 ;
    END
    PORT
      LAYER Metal1 ;
        RECT 0.250 1751.590 0.530 1751.840 ;
    END
    PORT
      LAYER Metal1 ;
        RECT 0.250 1760.170 0.530 1760.420 ;
    END
    PORT
      LAYER Metal1 ;
        RECT 0.250 1768.750 0.530 1769.000 ;
    END
    PORT
      LAYER Metal1 ;
        RECT 0.250 1777.330 0.530 1777.580 ;
    END
    PORT
      LAYER Metal1 ;
        RECT 0.250 1785.910 0.530 1786.160 ;
    END
    PORT
      LAYER Metal1 ;
        RECT 0.250 1794.490 0.530 1794.740 ;
    END
    PORT
      LAYER Metal1 ;
        RECT 0.250 1803.070 0.530 1803.320 ;
    END
    PORT
      LAYER Metal1 ;
        RECT 0.250 1811.650 0.530 1811.900 ;
    END
    PORT
      LAYER Metal1 ;
        RECT 0.250 1820.230 0.530 1820.480 ;
    END
    PORT
      LAYER Metal1 ;
        RECT 0.250 1828.810 0.530 1829.060 ;
    END
    PORT
      LAYER Metal1 ;
        RECT 0.250 1837.390 0.530 1837.640 ;
    END
    PORT
      LAYER Metal1 ;
        RECT 0.250 1845.970 0.530 1846.220 ;
    END
    PORT
      LAYER Metal1 ;
        RECT 0.250 1854.550 0.530 1854.800 ;
    END
    PORT
      LAYER Metal1 ;
        RECT 0.250 1863.130 0.530 1863.380 ;
    END
    PORT
      LAYER Metal1 ;
        RECT 0.250 1871.710 0.530 1871.960 ;
    END
    PORT
      LAYER Metal1 ;
        RECT 0.250 1880.290 0.530 1880.540 ;
    END
    PORT
      LAYER Metal1 ;
        RECT 0.250 1888.870 0.530 1889.120 ;
    END
    PORT
      LAYER Metal1 ;
        RECT 0.250 1897.450 0.530 1897.700 ;
    END
    PORT
      LAYER Metal1 ;
        RECT 0.250 1906.030 0.530 1906.280 ;
    END
    PORT
      LAYER Metal1 ;
        RECT 0.250 1914.610 0.530 1914.860 ;
    END
    PORT
      LAYER Metal1 ;
        RECT 0.250 1923.190 0.530 1923.440 ;
    END
    PORT
      LAYER Metal1 ;
        RECT 0.250 1931.770 0.530 1932.020 ;
    END
    PORT
      LAYER Metal1 ;
        RECT 0.250 1940.350 0.530 1940.600 ;
    END
    PORT
      LAYER Metal1 ;
        RECT 0.250 1948.930 0.530 1949.180 ;
    END
    PORT
      LAYER Metal1 ;
        RECT 0.250 1957.510 0.530 1957.760 ;
    END
    PORT
      LAYER Metal1 ;
        RECT 0.250 1966.090 0.530 1966.340 ;
    END
    PORT
      LAYER Metal1 ;
        RECT 0.250 1974.670 0.530 1974.920 ;
    END
    PORT
      LAYER Metal1 ;
        RECT 0.250 1983.250 0.530 1983.500 ;
    END
    PORT
      LAYER Metal1 ;
        RECT 0.250 1991.830 0.530 1992.080 ;
    END
    PORT
      LAYER Metal1 ;
        RECT 0.250 2000.410 0.530 2000.660 ;
    END
    PORT
      LAYER Metal1 ;
        RECT 0.250 2008.990 0.530 2009.240 ;
    END
    PORT
      LAYER Metal1 ;
        RECT 0.250 2017.570 0.530 2017.820 ;
    END
    PORT
      LAYER Metal1 ;
        RECT 0.250 2026.150 0.530 2026.400 ;
    END
    PORT
      LAYER Metal1 ;
        RECT 0.250 2034.730 0.530 2034.980 ;
    END
    PORT
      LAYER Metal1 ;
        RECT 0.250 2043.310 0.530 2043.560 ;
    END
    PORT
      LAYER Metal1 ;
        RECT 0.250 2051.890 0.530 2052.140 ;
    END
    PORT
      LAYER Metal1 ;
        RECT 0.250 2060.470 0.530 2060.720 ;
    END
    PORT
      LAYER Metal2 ;
        RECT 6.105 2.425 6.385 2.705 ;
    END
    PORT
      LAYER Metal2 ;
        RECT 14.685 2.425 14.965 2.705 ;
    END
    PORT
      LAYER Metal2 ;
        RECT 23.265 2.425 23.545 2.705 ;
    END
    PORT
      LAYER Metal2 ;
        RECT 31.845 2.425 32.125 2.705 ;
    END
    PORT
      LAYER Metal2 ;
        RECT 40.425 2.425 40.705 2.705 ;
    END
    PORT
      LAYER Metal2 ;
        RECT 49.005 2.425 49.285 2.705 ;
    END
    PORT
      LAYER Metal2 ;
        RECT 57.585 2.425 57.865 2.705 ;
    END
    PORT
      LAYER Metal2 ;
        RECT 66.165 2.425 66.445 2.705 ;
    END
    PORT
      LAYER Metal2 ;
        RECT 74.745 2.425 75.025 2.705 ;
    END
    PORT
      LAYER Metal2 ;
        RECT 83.325 2.425 83.605 2.705 ;
    END
    PORT
      LAYER Metal2 ;
        RECT 91.905 2.425 92.185 2.705 ;
    END
    PORT
      LAYER Metal2 ;
        RECT 100.485 2.425 100.765 2.705 ;
    END
    PORT
      LAYER Metal2 ;
        RECT 109.065 2.425 109.345 2.705 ;
    END
    PORT
      LAYER Metal2 ;
        RECT 117.645 2.425 117.925 2.705 ;
    END
    PORT
      LAYER Metal2 ;
        RECT 126.225 2.425 126.505 2.705 ;
    END
    PORT
      LAYER Metal2 ;
        RECT 134.805 2.425 135.085 2.705 ;
    END
    PORT
      LAYER Metal2 ;
        RECT 143.385 2.425 143.665 2.705 ;
    END
    PORT
      LAYER Metal2 ;
        RECT 151.965 2.425 152.245 2.705 ;
    END
    PORT
      LAYER Metal2 ;
        RECT 160.545 2.425 160.825 2.705 ;
    END
    PORT
      LAYER Metal2 ;
        RECT 169.125 2.425 169.405 2.705 ;
    END
    PORT
      LAYER Metal2 ;
        RECT 177.705 2.425 177.985 2.705 ;
    END
    PORT
      LAYER Metal2 ;
        RECT 186.285 2.425 186.565 2.705 ;
    END
    PORT
      LAYER Metal2 ;
        RECT 194.865 2.425 195.145 2.705 ;
    END
    PORT
      LAYER Metal2 ;
        RECT 203.445 2.425 203.725 2.705 ;
    END
    PORT
      LAYER Metal2 ;
        RECT 212.025 2.425 212.305 2.705 ;
    END
    PORT
      LAYER Metal2 ;
        RECT 220.605 2.425 220.885 2.705 ;
    END
    PORT
      LAYER Metal2 ;
        RECT 229.185 2.425 229.465 2.705 ;
    END
    PORT
      LAYER Metal2 ;
        RECT 237.765 2.425 238.045 2.705 ;
    END
    PORT
      LAYER Metal2 ;
        RECT 246.345 2.425 246.625 2.705 ;
    END
    PORT
      LAYER Metal2 ;
        RECT 254.925 2.425 255.205 2.705 ;
    END
    PORT
      LAYER Metal2 ;
        RECT 263.505 2.425 263.785 2.705 ;
    END
    PORT
      LAYER Metal2 ;
        RECT 272.085 2.425 272.365 2.705 ;
    END
    PORT
      LAYER Metal2 ;
        RECT 280.665 2.425 280.945 2.705 ;
    END
    PORT
      LAYER Metal2 ;
        RECT 289.245 2.425 289.525 2.705 ;
    END
    PORT
      LAYER Metal2 ;
        RECT 297.825 2.425 298.105 2.705 ;
    END
    PORT
      LAYER Metal2 ;
        RECT 306.405 2.425 306.685 2.705 ;
    END
    PORT
      LAYER Metal2 ;
        RECT 314.985 2.425 315.265 2.705 ;
    END
    PORT
      LAYER Metal2 ;
        RECT 323.565 2.425 323.845 2.705 ;
    END
    PORT
      LAYER Metal2 ;
        RECT 332.145 2.425 332.425 2.705 ;
    END
    PORT
      LAYER Metal2 ;
        RECT 340.725 2.425 341.005 2.705 ;
    END
    PORT
      LAYER Metal2 ;
        RECT 349.305 2.425 349.585 2.705 ;
    END
    PORT
      LAYER Metal2 ;
        RECT 357.885 2.425 358.165 2.705 ;
    END
    PORT
      LAYER Metal2 ;
        RECT 366.465 2.425 366.745 2.705 ;
    END
    PORT
      LAYER Metal2 ;
        RECT 375.045 2.425 375.325 2.705 ;
    END
    PORT
      LAYER Metal2 ;
        RECT 383.625 2.425 383.905 2.705 ;
    END
    PORT
      LAYER Metal2 ;
        RECT 392.205 2.425 392.485 2.705 ;
    END
    PORT
      LAYER Metal2 ;
        RECT 400.785 2.425 401.065 2.705 ;
    END
    PORT
      LAYER Metal2 ;
        RECT 409.365 2.425 409.645 2.705 ;
    END
    PORT
      LAYER Metal2 ;
        RECT 417.945 2.425 418.225 2.705 ;
    END
    PORT
      LAYER Metal2 ;
        RECT 426.525 2.425 426.805 2.705 ;
    END
    PORT
      LAYER Metal2 ;
        RECT 435.105 2.425 435.385 2.705 ;
    END
    PORT
      LAYER Metal2 ;
        RECT 443.685 2.425 443.965 2.705 ;
    END
    PORT
      LAYER Metal2 ;
        RECT 452.265 2.425 452.545 2.705 ;
    END
    PORT
      LAYER Metal2 ;
        RECT 460.845 2.425 461.125 2.705 ;
    END
    PORT
      LAYER Metal2 ;
        RECT 469.425 2.425 469.705 2.705 ;
    END
    PORT
      LAYER Metal2 ;
        RECT 478.005 2.425 478.285 2.705 ;
    END
    PORT
      LAYER Metal2 ;
        RECT 486.585 2.425 486.865 2.705 ;
    END
    PORT
      LAYER Metal2 ;
        RECT 495.165 2.425 495.445 2.705 ;
    END
    PORT
      LAYER Metal2 ;
        RECT 503.745 2.425 504.025 2.705 ;
    END
    PORT
      LAYER Metal2 ;
        RECT 512.325 2.425 512.605 2.705 ;
    END
    PORT
      LAYER Metal2 ;
        RECT 520.905 2.425 521.185 2.705 ;
    END
    PORT
      LAYER Metal2 ;
        RECT 529.485 2.425 529.765 2.705 ;
    END
    PORT
      LAYER Metal2 ;
        RECT 538.065 2.425 538.345 2.705 ;
    END
    PORT
      LAYER Metal2 ;
        RECT 546.645 2.425 546.925 2.705 ;
    END
    PORT
      LAYER Metal2 ;
        RECT 555.225 2.425 555.505 2.705 ;
    END
    PORT
      LAYER Metal2 ;
        RECT 563.805 2.425 564.085 2.705 ;
    END
    PORT
      LAYER Metal2 ;
        RECT 572.385 2.425 572.665 2.705 ;
    END
    PORT
      LAYER Metal2 ;
        RECT 580.965 2.425 581.245 2.705 ;
    END
    PORT
      LAYER Metal2 ;
        RECT 589.545 2.425 589.825 2.705 ;
    END
    PORT
      LAYER Metal2 ;
        RECT 598.125 2.425 598.405 2.705 ;
    END
    PORT
      LAYER Metal2 ;
        RECT 606.705 2.425 606.985 2.705 ;
    END
    PORT
      LAYER Metal2 ;
        RECT 615.285 2.425 615.565 2.705 ;
    END
    PORT
      LAYER Metal2 ;
        RECT 623.865 2.425 624.145 2.705 ;
    END
    PORT
      LAYER Metal2 ;
        RECT 632.445 2.425 632.725 2.705 ;
    END
    PORT
      LAYER Metal2 ;
        RECT 641.025 2.425 641.305 2.705 ;
    END
    PORT
      LAYER Metal2 ;
        RECT 649.605 2.425 649.885 2.705 ;
    END
    PORT
      LAYER Metal2 ;
        RECT 658.185 2.425 658.465 2.705 ;
    END
    PORT
      LAYER Metal2 ;
        RECT 666.765 2.425 667.045 2.705 ;
    END
    PORT
      LAYER Metal2 ;
        RECT 675.345 2.425 675.625 2.705 ;
    END
    PORT
      LAYER Metal2 ;
        RECT 683.925 2.425 684.205 2.705 ;
    END
    PORT
      LAYER Metal2 ;
        RECT 692.505 2.425 692.785 2.705 ;
    END
    PORT
      LAYER Metal2 ;
        RECT 701.085 2.425 701.365 2.705 ;
    END
    PORT
      LAYER Metal2 ;
        RECT 709.665 2.425 709.945 2.705 ;
    END
    PORT
      LAYER Metal2 ;
        RECT 718.245 2.425 718.525 2.705 ;
    END
    PORT
      LAYER Metal2 ;
        RECT 726.825 2.425 727.105 2.705 ;
    END
    PORT
      LAYER Metal2 ;
        RECT 735.405 2.425 735.685 2.705 ;
    END
    PORT
      LAYER Metal2 ;
        RECT 743.985 2.425 744.265 2.705 ;
    END
    PORT
      LAYER Metal2 ;
        RECT 752.565 2.425 752.845 2.705 ;
    END
    PORT
      LAYER Metal2 ;
        RECT 761.145 2.425 761.425 2.705 ;
    END
    PORT
      LAYER Metal2 ;
        RECT 769.725 2.425 770.005 2.705 ;
    END
    PORT
      LAYER Metal2 ;
        RECT 778.305 2.425 778.585 2.705 ;
    END
    PORT
      LAYER Metal2 ;
        RECT 786.885 2.425 787.165 2.705 ;
    END
    PORT
      LAYER Metal2 ;
        RECT 795.465 2.425 795.745 2.705 ;
    END
    PORT
      LAYER Metal2 ;
        RECT 804.045 2.425 804.325 2.705 ;
    END
    PORT
      LAYER Metal2 ;
        RECT 812.625 2.425 812.905 2.705 ;
    END
    PORT
      LAYER Metal2 ;
        RECT 821.205 2.425 821.485 2.705 ;
    END
    PORT
      LAYER Metal2 ;
        RECT 829.785 2.425 830.065 2.705 ;
    END
    PORT
      LAYER Metal2 ;
        RECT 838.365 2.425 838.645 2.705 ;
    END
    PORT
      LAYER Metal2 ;
        RECT 846.945 2.425 847.225 2.705 ;
    END
    PORT
      LAYER Metal2 ;
        RECT 855.525 2.425 855.805 2.705 ;
    END
    PORT
      LAYER Metal2 ;
        RECT 864.105 2.425 864.385 2.705 ;
    END
    PORT
      LAYER Metal2 ;
        RECT 872.685 2.425 872.965 2.705 ;
    END
    PORT
      LAYER Metal2 ;
        RECT 881.265 2.425 881.545 2.705 ;
    END
    PORT
      LAYER Metal2 ;
        RECT 889.845 2.425 890.125 2.705 ;
    END
    PORT
      LAYER Metal2 ;
        RECT 898.425 2.425 898.705 2.705 ;
    END
    PORT
      LAYER Metal2 ;
        RECT 907.005 2.425 907.285 2.705 ;
    END
    PORT
      LAYER Metal2 ;
        RECT 915.585 2.425 915.865 2.705 ;
    END
    PORT
      LAYER Metal2 ;
        RECT 924.165 2.425 924.445 2.705 ;
    END
    PORT
      LAYER Metal2 ;
        RECT 932.745 2.425 933.025 2.705 ;
    END
    PORT
      LAYER Metal2 ;
        RECT 941.325 2.425 941.605 2.705 ;
    END
    PORT
      LAYER Metal2 ;
        RECT 949.905 2.425 950.185 2.705 ;
    END
    PORT
      LAYER Metal2 ;
        RECT 958.485 2.425 958.765 2.705 ;
    END
    PORT
      LAYER Metal2 ;
        RECT 967.065 2.425 967.345 2.705 ;
    END
    PORT
      LAYER Metal2 ;
        RECT 975.645 2.425 975.925 2.705 ;
    END
    PORT
      LAYER Metal2 ;
        RECT 984.225 2.425 984.505 2.705 ;
    END
    PORT
      LAYER Metal2 ;
        RECT 992.805 2.425 993.085 2.705 ;
    END
    PORT
      LAYER Metal2 ;
        RECT 1001.385 2.425 1001.665 2.705 ;
    END
    PORT
      LAYER Metal2 ;
        RECT 1009.965 2.425 1010.245 2.705 ;
    END
    PORT
      LAYER Metal2 ;
        RECT 1018.545 2.425 1018.825 2.705 ;
    END
    PORT
      LAYER Metal2 ;
        RECT 1027.125 2.425 1027.405 2.705 ;
    END
    PORT
      LAYER Metal2 ;
        RECT 1035.705 2.425 1035.985 2.705 ;
    END
    PORT
      LAYER Metal2 ;
        RECT 1044.285 2.425 1044.565 2.705 ;
    END
    PORT
      LAYER Metal2 ;
        RECT 1052.865 2.425 1053.145 2.705 ;
    END
    PORT
      LAYER Metal2 ;
        RECT 1061.445 2.425 1061.725 2.705 ;
    END
    PORT
      LAYER Metal2 ;
        RECT 1070.025 2.425 1070.305 2.705 ;
    END
    PORT
      LAYER Metal2 ;
        RECT 1078.605 2.425 1078.885 2.705 ;
    END
    PORT
      LAYER Metal2 ;
        RECT 1087.185 2.425 1087.465 2.705 ;
    END
    PORT
      LAYER Metal2 ;
        RECT 1095.765 2.425 1096.045 2.705 ;
    END
    PORT
      LAYER Metal2 ;
        RECT 1104.345 2.425 1104.625 2.705 ;
    END
    PORT
      LAYER Metal2 ;
        RECT 1112.925 2.425 1113.205 2.705 ;
    END
    PORT
      LAYER Metal2 ;
        RECT 1121.505 2.425 1121.785 2.705 ;
    END
    PORT
      LAYER Metal2 ;
        RECT 1130.085 2.425 1130.365 2.705 ;
    END
    PORT
      LAYER Metal2 ;
        RECT 1138.665 2.425 1138.945 2.705 ;
    END
    PORT
      LAYER Metal2 ;
        RECT 1147.245 2.425 1147.525 2.705 ;
    END
    PORT
      LAYER Metal2 ;
        RECT 1155.825 2.425 1156.105 2.705 ;
    END
    PORT
      LAYER Metal2 ;
        RECT 1164.405 2.425 1164.685 2.705 ;
    END
    PORT
      LAYER Metal2 ;
        RECT 1172.985 2.425 1173.265 2.705 ;
    END
    PORT
      LAYER Metal2 ;
        RECT 1181.565 2.425 1181.845 2.705 ;
    END
    PORT
      LAYER Metal2 ;
        RECT 1190.145 2.425 1190.425 2.705 ;
    END
    PORT
      LAYER Metal2 ;
        RECT 1198.725 2.425 1199.005 2.705 ;
    END
    PORT
      LAYER Metal2 ;
        RECT 1207.305 2.425 1207.585 2.705 ;
    END
    PORT
      LAYER Metal2 ;
        RECT 1215.885 2.425 1216.165 2.705 ;
    END
    PORT
      LAYER Metal2 ;
        RECT 1224.465 2.425 1224.745 2.705 ;
    END
    PORT
      LAYER Metal2 ;
        RECT 1233.045 2.425 1233.325 2.705 ;
    END
    PORT
      LAYER Metal2 ;
        RECT 1241.625 2.425 1241.905 2.705 ;
    END
    PORT
      LAYER Metal2 ;
        RECT 1250.205 2.425 1250.485 2.705 ;
    END
    PORT
      LAYER Metal2 ;
        RECT 1258.785 2.425 1259.065 2.705 ;
    END
    PORT
      LAYER Metal2 ;
        RECT 1267.365 2.425 1267.645 2.705 ;
    END
    PORT
      LAYER Metal2 ;
        RECT 1275.945 2.425 1276.225 2.705 ;
    END
    PORT
      LAYER Metal2 ;
        RECT 1284.525 2.425 1284.805 2.705 ;
    END
    PORT
      LAYER Metal2 ;
        RECT 1293.105 2.425 1293.385 2.705 ;
    END
    PORT
      LAYER Metal2 ;
        RECT 1301.685 2.425 1301.965 2.705 ;
    END
    PORT
      LAYER Metal2 ;
        RECT 1310.265 2.425 1310.545 2.705 ;
    END
    PORT
      LAYER Metal2 ;
        RECT 1318.845 2.425 1319.125 2.705 ;
    END
    PORT
      LAYER Metal2 ;
        RECT 1327.425 2.425 1327.705 2.705 ;
    END
    PORT
      LAYER Metal2 ;
        RECT 1336.005 2.425 1336.285 2.705 ;
    END
    PORT
      LAYER Metal2 ;
        RECT 1344.585 2.425 1344.865 2.705 ;
    END
    PORT
      LAYER Metal2 ;
        RECT 1353.165 2.425 1353.445 2.705 ;
    END
    PORT
      LAYER Metal2 ;
        RECT 1361.745 2.425 1362.025 2.705 ;
    END
    PORT
      LAYER Metal2 ;
        RECT 1370.325 2.425 1370.605 2.705 ;
    END
    PORT
      LAYER Metal2 ;
        RECT 1378.905 2.425 1379.185 2.705 ;
    END
    PORT
      LAYER Metal2 ;
        RECT 1387.485 2.425 1387.765 2.705 ;
    END
    PORT
      LAYER Metal2 ;
        RECT 1396.065 2.425 1396.345 2.705 ;
    END
    PORT
      LAYER Metal2 ;
        RECT 1404.645 2.425 1404.925 2.705 ;
    END
    PORT
      LAYER Metal2 ;
        RECT 1413.225 2.425 1413.505 2.705 ;
    END
    PORT
      LAYER Metal2 ;
        RECT 1421.805 2.425 1422.085 2.705 ;
    END
    PORT
      LAYER Metal2 ;
        RECT 1430.385 2.425 1430.665 2.705 ;
    END
    PORT
      LAYER Metal2 ;
        RECT 1438.965 2.425 1439.245 2.705 ;
    END
    PORT
      LAYER Metal2 ;
        RECT 1447.545 2.425 1447.825 2.705 ;
    END
    PORT
      LAYER Metal2 ;
        RECT 1456.125 2.425 1456.405 2.705 ;
    END
    PORT
      LAYER Metal2 ;
        RECT 1464.705 2.425 1464.985 2.705 ;
    END
    PORT
      LAYER Metal2 ;
        RECT 1473.285 2.425 1473.565 2.705 ;
    END
    PORT
      LAYER Metal2 ;
        RECT 1481.865 2.425 1482.145 2.705 ;
    END
    PORT
      LAYER Metal2 ;
        RECT 1490.445 2.425 1490.725 2.705 ;
    END
    PORT
      LAYER Metal2 ;
        RECT 1499.025 2.425 1499.305 2.705 ;
    END
    PORT
      LAYER Metal2 ;
        RECT 1507.605 2.425 1507.885 2.705 ;
    END
    PORT
      LAYER Metal2 ;
        RECT 1516.185 2.425 1516.465 2.705 ;
    END
    PORT
      LAYER Metal2 ;
        RECT 1524.765 2.425 1525.045 2.705 ;
    END
    PORT
      LAYER Metal2 ;
        RECT 1533.345 2.425 1533.625 2.705 ;
    END
    PORT
      LAYER Metal2 ;
        RECT 1541.925 2.425 1542.205 2.705 ;
    END
    PORT
      LAYER Metal2 ;
        RECT 1550.505 2.425 1550.785 2.705 ;
    END
    PORT
      LAYER Metal2 ;
        RECT 1559.085 2.425 1559.365 2.705 ;
    END
    PORT
      LAYER Metal2 ;
        RECT 1567.665 2.425 1567.945 2.705 ;
    END
    PORT
      LAYER Metal2 ;
        RECT 1576.245 2.425 1576.525 2.705 ;
    END
    PORT
      LAYER Metal2 ;
        RECT 1584.825 2.425 1585.105 2.705 ;
    END
    PORT
      LAYER Metal2 ;
        RECT 1593.405 2.425 1593.685 2.705 ;
    END
    PORT
      LAYER Metal2 ;
        RECT 1601.985 2.425 1602.265 2.705 ;
    END
    PORT
      LAYER Metal2 ;
        RECT 1610.565 2.425 1610.845 2.705 ;
    END
    PORT
      LAYER Metal2 ;
        RECT 1619.145 2.425 1619.425 2.705 ;
    END
    PORT
      LAYER Metal2 ;
        RECT 1627.725 2.425 1628.005 2.705 ;
    END
    PORT
      LAYER Metal2 ;
        RECT 1636.305 2.425 1636.585 2.705 ;
    END
    PORT
      LAYER Metal2 ;
        RECT 1644.885 2.425 1645.165 2.705 ;
    END
    PORT
      LAYER Metal2 ;
        RECT 1653.465 2.425 1653.745 2.705 ;
    END
    PORT
      LAYER Metal2 ;
        RECT 1662.045 2.425 1662.325 2.705 ;
    END
    PORT
      LAYER Metal2 ;
        RECT 1670.625 2.425 1670.905 2.705 ;
    END
    PORT
      LAYER Metal2 ;
        RECT 1679.205 2.425 1679.485 2.705 ;
    END
    PORT
      LAYER Metal2 ;
        RECT 1687.785 2.425 1688.065 2.705 ;
    END
    PORT
      LAYER Metal2 ;
        RECT 1696.365 2.425 1696.645 2.705 ;
    END
    PORT
      LAYER Metal2 ;
        RECT 1704.945 2.425 1705.225 2.705 ;
    END
    PORT
      LAYER Metal2 ;
        RECT 1713.525 2.425 1713.805 2.705 ;
    END
    PORT
      LAYER Metal2 ;
        RECT 1722.105 2.425 1722.385 2.705 ;
    END
    PORT
      LAYER Metal2 ;
        RECT 1730.685 2.425 1730.965 2.705 ;
    END
    PORT
      LAYER Metal2 ;
        RECT 1739.265 2.425 1739.545 2.705 ;
    END
    PORT
      LAYER Metal2 ;
        RECT 1747.845 2.425 1748.125 2.705 ;
    END
    PORT
      LAYER Metal2 ;
        RECT 1756.425 2.425 1756.705 2.705 ;
    END
    PORT
      LAYER Metal2 ;
        RECT 1765.005 2.425 1765.285 2.705 ;
    END
    PORT
      LAYER Metal2 ;
        RECT 1773.585 2.425 1773.865 2.705 ;
    END
    PORT
      LAYER Metal2 ;
        RECT 1782.165 2.425 1782.445 2.705 ;
    END
    PORT
      LAYER Metal2 ;
        RECT 1790.745 2.425 1791.025 2.705 ;
    END
    PORT
      LAYER Metal2 ;
        RECT 1799.325 2.425 1799.605 2.705 ;
    END
    PORT
      LAYER Metal2 ;
        RECT 1807.905 2.425 1808.185 2.705 ;
    END
    PORT
      LAYER Metal2 ;
        RECT 1816.485 2.425 1816.765 2.705 ;
    END
    PORT
      LAYER Metal2 ;
        RECT 1825.065 2.425 1825.345 2.705 ;
    END
    PORT
      LAYER Metal2 ;
        RECT 1833.645 2.425 1833.925 2.705 ;
    END
    PORT
      LAYER Metal2 ;
        RECT 1842.225 2.425 1842.505 2.705 ;
    END
    PORT
      LAYER Metal2 ;
        RECT 1850.805 2.425 1851.085 2.705 ;
    END
    PORT
      LAYER Metal2 ;
        RECT 1859.385 2.425 1859.665 2.705 ;
    END
    PORT
      LAYER Metal2 ;
        RECT 1867.965 2.425 1868.245 2.705 ;
    END
    PORT
      LAYER Metal2 ;
        RECT 1876.545 2.425 1876.825 2.705 ;
    END
    PORT
      LAYER Metal2 ;
        RECT 1885.125 2.425 1885.405 2.705 ;
    END
    PORT
      LAYER Metal2 ;
        RECT 1893.705 2.425 1893.985 2.705 ;
    END
    PORT
      LAYER Metal2 ;
        RECT 1902.285 2.425 1902.565 2.705 ;
    END
    PORT
      LAYER Metal2 ;
        RECT 1910.865 2.425 1911.145 2.705 ;
    END
    PORT
      LAYER Metal2 ;
        RECT 1919.445 2.425 1919.725 2.705 ;
    END
    PORT
      LAYER Metal2 ;
        RECT 1928.025 2.425 1928.305 2.705 ;
    END
    PORT
      LAYER Metal2 ;
        RECT 1936.605 2.425 1936.885 2.705 ;
    END
    PORT
      LAYER Metal2 ;
        RECT 1945.185 2.425 1945.465 2.705 ;
    END
    PORT
      LAYER Metal2 ;
        RECT 1953.765 2.425 1954.045 2.705 ;
    END
    PORT
      LAYER Metal2 ;
        RECT 1962.345 2.425 1962.625 2.705 ;
    END
    PORT
      LAYER Metal2 ;
        RECT 1970.925 2.425 1971.205 2.705 ;
    END
    PORT
      LAYER Metal2 ;
        RECT 1979.505 2.425 1979.785 2.705 ;
    END
    PORT
      LAYER Metal2 ;
        RECT 1988.085 2.425 1988.365 2.705 ;
    END
    PORT
      LAYER Metal2 ;
        RECT 1996.665 2.425 1996.945 2.705 ;
    END
    PORT
      LAYER Metal2 ;
        RECT 2005.245 2.425 2005.525 2.705 ;
    END
    PORT
      LAYER Metal2 ;
        RECT 2013.825 2.425 2014.105 2.705 ;
    END
    PORT
      LAYER Metal2 ;
        RECT 2022.405 2.425 2022.685 2.705 ;
    END
    PORT
      LAYER Metal2 ;
        RECT 2030.985 2.425 2031.265 2.705 ;
    END
    PORT
      LAYER Metal2 ;
        RECT 2039.565 2.425 2039.845 2.705 ;
    END
    PORT
      LAYER Metal2 ;
        RECT 2048.145 2.425 2048.425 2.705 ;
    END
    PORT
      LAYER Metal2 ;
        RECT 2056.725 2.425 2057.005 2.705 ;
    END
    PORT
      LAYER Metal2 ;
        RECT 2065.305 2.425 2065.585 2.705 ;
    END
    PORT
      LAYER Metal2 ;
        RECT 2073.885 2.425 2074.165 2.705 ;
    END
    PORT
      LAYER Metal2 ;
        RECT 2082.465 2.425 2082.745 2.705 ;
    END
    PORT
      LAYER Metal2 ;
        RECT 2091.045 2.425 2091.325 2.705 ;
    END
    PORT
      LAYER Metal2 ;
        RECT 2099.625 2.425 2099.905 2.705 ;
    END
    PORT
      LAYER Metal2 ;
        RECT 2108.205 2.425 2108.485 2.705 ;
    END
    PORT
      LAYER Metal2 ;
        RECT 2116.785 2.425 2117.065 2.705 ;
    END
    PORT
      LAYER Metal2 ;
        RECT 2125.365 2.425 2125.645 2.705 ;
    END
    PORT
      LAYER Metal2 ;
        RECT 2133.945 2.425 2134.225 2.705 ;
    END
    PORT
      LAYER Metal2 ;
        RECT 2142.525 2.425 2142.805 2.705 ;
    END
    PORT
      LAYER Metal2 ;
        RECT 2151.105 2.425 2151.385 2.705 ;
    END
    PORT
      LAYER Metal2 ;
        RECT 2159.685 2.425 2159.965 2.705 ;
    END
    PORT
      LAYER Metal2 ;
        RECT 2168.265 2.425 2168.545 2.705 ;
    END
    PORT
      LAYER Metal2 ;
        RECT 2176.845 2.425 2177.125 2.705 ;
    END
    PORT
      LAYER Metal2 ;
        RECT 2185.425 2.425 2185.705 2.705 ;
    END
    PORT
      LAYER Metal2 ;
        RECT 2194.005 2.425 2194.285 2.705 ;
    END
    PORT
      LAYER Metal2 ;
        RECT 2202.585 2.425 2202.865 2.705 ;
    END
    PORT
      LAYER Metal2 ;
        RECT 2211.165 2.425 2211.445 2.705 ;
    END
    PORT
      LAYER Metal2 ;
        RECT 2219.745 2.425 2220.025 2.705 ;
    END
    PORT
      LAYER Metal2 ;
        RECT 2228.325 2.425 2228.605 2.705 ;
    END
    PORT
      LAYER Metal2 ;
        RECT 2236.905 2.425 2237.185 2.705 ;
    END
    PORT
      LAYER Metal2 ;
        RECT 2245.485 2.425 2245.765 2.705 ;
    END
    PORT
      LAYER Metal2 ;
        RECT 2254.065 2.425 2254.345 2.705 ;
    END
    PORT
      LAYER Metal2 ;
        RECT 2262.645 2.425 2262.925 2.705 ;
    END
    PORT
      LAYER Metal2 ;
        RECT 2271.225 2.425 2271.505 2.705 ;
    END
    PORT
      LAYER Metal2 ;
        RECT 2279.805 2.425 2280.085 2.705 ;
    END
    PORT
      LAYER Metal2 ;
        RECT 2288.385 2.425 2288.665 2.705 ;
    END
    PORT
      LAYER Metal2 ;
        RECT 2296.965 2.425 2297.245 2.705 ;
    END
    PORT
      LAYER Metal2 ;
        RECT 2305.545 2.425 2305.825 2.705 ;
    END
    PORT
      LAYER Metal2 ;
        RECT 2314.125 2.425 2314.405 2.705 ;
    END
    PORT
      LAYER Metal2 ;
        RECT 2322.705 2.425 2322.985 2.705 ;
    END
    PORT
      LAYER Metal2 ;
        RECT 2331.285 2.425 2331.565 2.705 ;
    END
    PORT
      LAYER Metal2 ;
        RECT 2339.865 2.425 2340.145 2.705 ;
    END
    PORT
      LAYER Metal2 ;
        RECT 2348.445 2.425 2348.725 2.705 ;
    END
    PORT
      LAYER Metal2 ;
        RECT 2357.025 2.425 2357.305 2.705 ;
    END
    PORT
      LAYER Metal2 ;
        RECT 2365.605 2.425 2365.885 2.705 ;
    END
    PORT
      LAYER Metal2 ;
        RECT 2374.185 2.425 2374.465 2.705 ;
    END
    PORT
      LAYER Metal2 ;
        RECT 2382.765 2.425 2383.045 2.705 ;
    END
    PORT
      LAYER Metal2 ;
        RECT 2391.345 2.425 2391.625 2.705 ;
    END
    PORT
      LAYER Metal2 ;
        RECT 2399.925 2.425 2400.205 2.705 ;
    END
    PORT
      LAYER Metal2 ;
        RECT 2408.505 2.425 2408.785 2.705 ;
    END
    PORT
      LAYER Metal2 ;
        RECT 2417.085 2.425 2417.365 2.705 ;
    END
    PORT
      LAYER Metal2 ;
        RECT 2425.665 2.425 2425.945 2.705 ;
    END
    PORT
      LAYER Metal2 ;
        RECT 2434.245 2.425 2434.525 2.705 ;
    END
    PORT
      LAYER Metal2 ;
        RECT 2442.825 2.425 2443.105 2.705 ;
    END
    PORT
      LAYER Metal2 ;
        RECT 2451.405 2.425 2451.685 2.705 ;
    END
    PORT
      LAYER Metal2 ;
        RECT 2459.985 2.425 2460.265 2.705 ;
    END
    PORT
      LAYER Metal2 ;
        RECT 2468.565 2.425 2468.845 2.705 ;
    END
    PORT
      LAYER Metal2 ;
        RECT 2477.145 2.425 2477.425 2.705 ;
    END
    PORT
      LAYER Metal2 ;
        RECT 2485.725 2.425 2486.005 2.705 ;
    END
    PORT
      LAYER Metal2 ;
        RECT 2494.305 2.425 2494.585 2.705 ;
    END
    PORT
      LAYER Metal2 ;
        RECT 2502.885 2.425 2503.165 2.705 ;
    END
    PORT
      LAYER Metal2 ;
        RECT 2511.465 2.425 2511.745 2.705 ;
    END
    PORT
      LAYER Metal2 ;
        RECT 2520.045 2.425 2520.325 2.705 ;
    END
    PORT
      LAYER Metal2 ;
        RECT 2528.625 2.425 2528.905 2.705 ;
    END
    PORT
      LAYER Metal2 ;
        RECT 2537.205 2.425 2537.485 2.705 ;
    END
    PORT
      LAYER Metal2 ;
        RECT 2545.785 2.425 2546.065 2.705 ;
    END
    PORT
      LAYER Metal2 ;
        RECT 2554.365 2.425 2554.645 2.705 ;
    END
    PORT
      LAYER Metal2 ;
        RECT 2562.945 2.425 2563.225 2.705 ;
    END
    PORT
      LAYER Metal2 ;
        RECT 2571.525 2.425 2571.805 2.705 ;
    END
    PORT
      LAYER Metal2 ;
        RECT 2580.105 2.425 2580.385 2.705 ;
    END
    PORT
      LAYER Metal2 ;
        RECT 2588.685 2.425 2588.965 2.705 ;
    END
    PORT
      LAYER Metal2 ;
        RECT 2597.265 2.425 2597.545 2.705 ;
    END
    PORT
      LAYER Metal2 ;
        RECT 2605.845 2.425 2606.125 2.705 ;
    END
    PORT
      LAYER Metal2 ;
        RECT 2614.425 2.425 2614.705 2.705 ;
    END
    PORT
      LAYER Metal2 ;
        RECT 2623.005 2.425 2623.285 2.705 ;
    END
    PORT
      LAYER Metal2 ;
        RECT 2631.585 2.425 2631.865 2.705 ;
    END
    PORT
      LAYER Metal2 ;
        RECT 2640.165 2.425 2640.445 2.705 ;
    END
    PORT
      LAYER Metal2 ;
        RECT 2648.745 2.425 2649.025 2.705 ;
    END
    PORT
      LAYER Metal2 ;
        RECT 2657.325 2.425 2657.605 2.705 ;
    END
    PORT
      LAYER Metal2 ;
        RECT 2665.905 2.425 2666.185 2.705 ;
    END
    PORT
      LAYER Metal2 ;
        RECT 2674.485 2.425 2674.765 2.705 ;
    END
    PORT
      LAYER Metal2 ;
        RECT 2683.065 2.425 2683.345 2.705 ;
    END
    PORT
      LAYER Metal2 ;
        RECT 2691.645 2.425 2691.925 2.705 ;
    END
    PORT
      LAYER Metal2 ;
        RECT 2700.225 2.425 2700.505 2.705 ;
    END
    PORT
      LAYER Metal2 ;
        RECT 2708.805 2.425 2709.085 2.705 ;
    END
    PORT
      LAYER Metal2 ;
        RECT 2717.385 2.425 2717.665 2.705 ;
    END
    PORT
      LAYER Metal2 ;
        RECT 2725.965 2.425 2726.245 2.705 ;
    END
    PORT
      LAYER Metal2 ;
        RECT 2734.545 2.425 2734.825 2.705 ;
    END
    PORT
      LAYER Metal2 ;
        RECT 2743.125 2.425 2743.405 2.705 ;
    END
    PORT
      LAYER Metal2 ;
        RECT 2751.705 2.425 2751.985 2.705 ;
    END
  END VDD

  PIN GND
    DIRECTION INOUT ;
    USE GROUND ;
    PORT
      LAYER Metal3 ;
        RECT 0.530 9.845 0.810 11.005 ;
    END
    PORT
      LAYER Metal3 ;
        RECT 0.530 18.425 0.810 19.585 ;
    END
    PORT
      LAYER Metal3 ;
        RECT 0.530 27.005 0.810 28.165 ;
    END
    PORT
      LAYER Metal3 ;
        RECT 0.530 35.585 0.810 36.745 ;
    END
    PORT
      LAYER Metal3 ;
        RECT 0.530 44.165 0.810 45.325 ;
    END
    PORT
      LAYER Metal3 ;
        RECT 0.530 52.745 0.810 53.905 ;
    END
    PORT
      LAYER Metal3 ;
        RECT 0.530 61.325 0.810 62.485 ;
    END
    PORT
      LAYER Metal3 ;
        RECT 0.530 69.905 0.810 71.065 ;
    END
    PORT
      LAYER Metal3 ;
        RECT 0.530 78.485 0.810 79.645 ;
    END
    PORT
      LAYER Metal3 ;
        RECT 0.530 87.065 0.810 88.225 ;
    END
    PORT
      LAYER Metal3 ;
        RECT 0.530 95.645 0.810 96.805 ;
    END
    PORT
      LAYER Metal3 ;
        RECT 0.530 104.225 0.810 105.385 ;
    END
    PORT
      LAYER Metal3 ;
        RECT 0.530 112.805 0.810 113.965 ;
    END
    PORT
      LAYER Metal3 ;
        RECT 0.530 121.385 0.810 122.545 ;
    END
    PORT
      LAYER Metal3 ;
        RECT 0.530 129.965 0.810 131.125 ;
    END
    PORT
      LAYER Metal3 ;
        RECT 0.530 138.545 0.810 139.705 ;
    END
    PORT
      LAYER Metal3 ;
        RECT 0.530 147.125 0.810 148.285 ;
    END
    PORT
      LAYER Metal3 ;
        RECT 0.530 155.705 0.810 156.865 ;
    END
    PORT
      LAYER Metal3 ;
        RECT 0.530 164.285 0.810 165.445 ;
    END
    PORT
      LAYER Metal3 ;
        RECT 0.530 172.865 0.810 174.025 ;
    END
    PORT
      LAYER Metal3 ;
        RECT 0.530 181.445 0.810 182.605 ;
    END
    PORT
      LAYER Metal3 ;
        RECT 0.530 190.025 0.810 191.185 ;
    END
    PORT
      LAYER Metal3 ;
        RECT 0.530 198.605 0.810 199.765 ;
    END
    PORT
      LAYER Metal3 ;
        RECT 0.530 207.185 0.810 208.345 ;
    END
    PORT
      LAYER Metal3 ;
        RECT 0.530 215.765 0.810 216.925 ;
    END
    PORT
      LAYER Metal3 ;
        RECT 0.530 224.345 0.810 225.505 ;
    END
    PORT
      LAYER Metal3 ;
        RECT 0.530 232.925 0.810 234.085 ;
    END
    PORT
      LAYER Metal3 ;
        RECT 0.530 241.505 0.810 242.665 ;
    END
    PORT
      LAYER Metal3 ;
        RECT 0.530 250.085 0.810 251.245 ;
    END
    PORT
      LAYER Metal3 ;
        RECT 0.530 258.665 0.810 259.825 ;
    END
    PORT
      LAYER Metal3 ;
        RECT 0.530 267.245 0.810 268.405 ;
    END
    PORT
      LAYER Metal3 ;
        RECT 0.530 275.825 0.810 276.985 ;
    END
    PORT
      LAYER Metal3 ;
        RECT 0.530 284.405 0.810 285.565 ;
    END
    PORT
      LAYER Metal3 ;
        RECT 0.530 292.985 0.810 294.145 ;
    END
    PORT
      LAYER Metal3 ;
        RECT 0.530 301.565 0.810 302.725 ;
    END
    PORT
      LAYER Metal3 ;
        RECT 0.530 310.145 0.810 311.305 ;
    END
    PORT
      LAYER Metal3 ;
        RECT 0.530 318.725 0.810 319.885 ;
    END
    PORT
      LAYER Metal3 ;
        RECT 0.530 327.305 0.810 328.465 ;
    END
    PORT
      LAYER Metal3 ;
        RECT 0.530 335.885 0.810 337.045 ;
    END
    PORT
      LAYER Metal3 ;
        RECT 0.530 344.465 0.810 345.625 ;
    END
    PORT
      LAYER Metal3 ;
        RECT 0.530 353.045 0.810 354.205 ;
    END
    PORT
      LAYER Metal3 ;
        RECT 0.530 361.625 0.810 362.785 ;
    END
    PORT
      LAYER Metal3 ;
        RECT 0.530 370.205 0.810 371.365 ;
    END
    PORT
      LAYER Metal3 ;
        RECT 0.530 378.785 0.810 379.945 ;
    END
    PORT
      LAYER Metal3 ;
        RECT 0.530 387.365 0.810 388.525 ;
    END
    PORT
      LAYER Metal3 ;
        RECT 0.530 395.945 0.810 397.105 ;
    END
    PORT
      LAYER Metal3 ;
        RECT 0.530 404.525 0.810 405.685 ;
    END
    PORT
      LAYER Metal3 ;
        RECT 0.530 413.105 0.810 414.265 ;
    END
    PORT
      LAYER Metal3 ;
        RECT 0.530 421.685 0.810 422.845 ;
    END
    PORT
      LAYER Metal3 ;
        RECT 0.530 430.265 0.810 431.425 ;
    END
    PORT
      LAYER Metal3 ;
        RECT 0.530 438.845 0.810 440.005 ;
    END
    PORT
      LAYER Metal3 ;
        RECT 0.530 447.425 0.810 448.585 ;
    END
    PORT
      LAYER Metal3 ;
        RECT 0.530 456.005 0.810 457.165 ;
    END
    PORT
      LAYER Metal3 ;
        RECT 0.530 464.585 0.810 465.745 ;
    END
    PORT
      LAYER Metal3 ;
        RECT 0.530 473.165 0.810 474.325 ;
    END
    PORT
      LAYER Metal3 ;
        RECT 0.530 481.745 0.810 482.905 ;
    END
    PORT
      LAYER Metal3 ;
        RECT 0.530 490.325 0.810 491.485 ;
    END
    PORT
      LAYER Metal3 ;
        RECT 0.530 498.905 0.810 500.065 ;
    END
    PORT
      LAYER Metal3 ;
        RECT 0.530 507.485 0.810 508.645 ;
    END
    PORT
      LAYER Metal3 ;
        RECT 0.530 516.065 0.810 517.225 ;
    END
    PORT
      LAYER Metal3 ;
        RECT 0.530 524.645 0.810 525.805 ;
    END
    PORT
      LAYER Metal3 ;
        RECT 0.530 533.225 0.810 534.385 ;
    END
    PORT
      LAYER Metal3 ;
        RECT 0.530 541.805 0.810 542.965 ;
    END
    PORT
      LAYER Metal3 ;
        RECT 0.530 550.385 0.810 551.545 ;
    END
    PORT
      LAYER Metal3 ;
        RECT 0.530 558.965 0.810 560.125 ;
    END
    PORT
      LAYER Metal3 ;
        RECT 0.530 567.545 0.810 568.705 ;
    END
    PORT
      LAYER Metal3 ;
        RECT 0.530 576.125 0.810 577.285 ;
    END
    PORT
      LAYER Metal3 ;
        RECT 0.530 584.705 0.810 585.865 ;
    END
    PORT
      LAYER Metal3 ;
        RECT 0.530 593.285 0.810 594.445 ;
    END
    PORT
      LAYER Metal3 ;
        RECT 0.530 601.865 0.810 603.025 ;
    END
    PORT
      LAYER Metal3 ;
        RECT 0.530 610.445 0.810 611.605 ;
    END
    PORT
      LAYER Metal3 ;
        RECT 0.530 619.025 0.810 620.185 ;
    END
    PORT
      LAYER Metal3 ;
        RECT 0.530 627.605 0.810 628.765 ;
    END
    PORT
      LAYER Metal3 ;
        RECT 0.530 636.185 0.810 637.345 ;
    END
    PORT
      LAYER Metal3 ;
        RECT 0.530 644.765 0.810 645.925 ;
    END
    PORT
      LAYER Metal3 ;
        RECT 0.530 653.345 0.810 654.505 ;
    END
    PORT
      LAYER Metal3 ;
        RECT 0.530 661.925 0.810 663.085 ;
    END
    PORT
      LAYER Metal3 ;
        RECT 0.530 670.505 0.810 671.665 ;
    END
    PORT
      LAYER Metal3 ;
        RECT 0.530 679.085 0.810 680.245 ;
    END
    PORT
      LAYER Metal3 ;
        RECT 0.530 687.665 0.810 688.825 ;
    END
    PORT
      LAYER Metal3 ;
        RECT 0.530 696.245 0.810 697.405 ;
    END
    PORT
      LAYER Metal3 ;
        RECT 0.530 704.825 0.810 705.985 ;
    END
    PORT
      LAYER Metal3 ;
        RECT 0.530 713.405 0.810 714.565 ;
    END
    PORT
      LAYER Metal3 ;
        RECT 0.530 721.985 0.810 723.145 ;
    END
    PORT
      LAYER Metal3 ;
        RECT 0.530 730.565 0.810 731.725 ;
    END
    PORT
      LAYER Metal3 ;
        RECT 0.530 739.145 0.810 740.305 ;
    END
    PORT
      LAYER Metal3 ;
        RECT 0.530 747.725 0.810 748.885 ;
    END
    PORT
      LAYER Metal3 ;
        RECT 0.530 756.305 0.810 757.465 ;
    END
    PORT
      LAYER Metal3 ;
        RECT 0.530 764.885 0.810 766.045 ;
    END
    PORT
      LAYER Metal3 ;
        RECT 0.530 773.465 0.810 774.625 ;
    END
    PORT
      LAYER Metal3 ;
        RECT 0.530 782.045 0.810 783.205 ;
    END
    PORT
      LAYER Metal3 ;
        RECT 0.530 790.625 0.810 791.785 ;
    END
    PORT
      LAYER Metal3 ;
        RECT 0.530 799.205 0.810 800.365 ;
    END
    PORT
      LAYER Metal3 ;
        RECT 0.530 807.785 0.810 808.945 ;
    END
    PORT
      LAYER Metal3 ;
        RECT 0.530 816.365 0.810 817.525 ;
    END
    PORT
      LAYER Metal3 ;
        RECT 0.530 824.945 0.810 826.105 ;
    END
    PORT
      LAYER Metal3 ;
        RECT 0.530 833.525 0.810 834.685 ;
    END
    PORT
      LAYER Metal3 ;
        RECT 0.530 842.105 0.810 843.265 ;
    END
    PORT
      LAYER Metal3 ;
        RECT 0.530 850.685 0.810 851.845 ;
    END
    PORT
      LAYER Metal3 ;
        RECT 0.530 859.265 0.810 860.425 ;
    END
    PORT
      LAYER Metal3 ;
        RECT 0.530 867.845 0.810 869.005 ;
    END
    PORT
      LAYER Metal3 ;
        RECT 0.530 876.425 0.810 877.585 ;
    END
    PORT
      LAYER Metal3 ;
        RECT 0.530 885.005 0.810 886.165 ;
    END
    PORT
      LAYER Metal3 ;
        RECT 0.530 893.585 0.810 894.745 ;
    END
    PORT
      LAYER Metal3 ;
        RECT 0.530 902.165 0.810 903.325 ;
    END
    PORT
      LAYER Metal3 ;
        RECT 0.530 910.745 0.810 911.905 ;
    END
    PORT
      LAYER Metal3 ;
        RECT 0.530 919.325 0.810 920.485 ;
    END
    PORT
      LAYER Metal3 ;
        RECT 0.530 927.905 0.810 929.065 ;
    END
    PORT
      LAYER Metal3 ;
        RECT 0.530 936.485 0.810 937.645 ;
    END
    PORT
      LAYER Metal3 ;
        RECT 0.530 945.065 0.810 946.225 ;
    END
    PORT
      LAYER Metal3 ;
        RECT 0.530 953.645 0.810 954.805 ;
    END
    PORT
      LAYER Metal3 ;
        RECT 0.530 962.225 0.810 963.385 ;
    END
    PORT
      LAYER Metal3 ;
        RECT 0.530 970.805 0.810 971.965 ;
    END
    PORT
      LAYER Metal3 ;
        RECT 0.530 979.385 0.810 980.545 ;
    END
    PORT
      LAYER Metal3 ;
        RECT 0.530 987.965 0.810 989.125 ;
    END
    PORT
      LAYER Metal3 ;
        RECT 0.530 996.545 0.810 997.705 ;
    END
    PORT
      LAYER Metal3 ;
        RECT 0.530 1005.125 0.810 1006.285 ;
    END
    PORT
      LAYER Metal3 ;
        RECT 0.530 1013.705 0.810 1014.865 ;
    END
    PORT
      LAYER Metal3 ;
        RECT 0.530 1022.285 0.810 1023.445 ;
    END
    PORT
      LAYER Metal3 ;
        RECT 0.530 1030.865 0.810 1032.025 ;
    END
    PORT
      LAYER Metal3 ;
        RECT 0.530 1039.445 0.810 1040.605 ;
    END
    PORT
      LAYER Metal3 ;
        RECT 0.530 1048.025 0.810 1049.185 ;
    END
    PORT
      LAYER Metal3 ;
        RECT 0.530 1056.605 0.810 1057.765 ;
    END
    PORT
      LAYER Metal3 ;
        RECT 0.530 1065.185 0.810 1066.345 ;
    END
    PORT
      LAYER Metal3 ;
        RECT 0.530 1073.765 0.810 1074.925 ;
    END
    PORT
      LAYER Metal3 ;
        RECT 0.530 1082.345 0.810 1083.505 ;
    END
    PORT
      LAYER Metal3 ;
        RECT 0.530 1090.925 0.810 1092.085 ;
    END
    PORT
      LAYER Metal3 ;
        RECT 0.530 1099.505 0.810 1100.665 ;
    END
    PORT
      LAYER Metal3 ;
        RECT 0.530 1108.085 0.810 1109.245 ;
    END
    PORT
      LAYER Metal3 ;
        RECT 0.530 1116.665 0.810 1117.825 ;
    END
    PORT
      LAYER Metal3 ;
        RECT 0.530 1125.245 0.810 1126.405 ;
    END
    PORT
      LAYER Metal3 ;
        RECT 0.530 1133.825 0.810 1134.985 ;
    END
    PORT
      LAYER Metal3 ;
        RECT 0.530 1142.405 0.810 1143.565 ;
    END
    PORT
      LAYER Metal3 ;
        RECT 0.530 1150.985 0.810 1152.145 ;
    END
    PORT
      LAYER Metal3 ;
        RECT 0.530 1159.565 0.810 1160.725 ;
    END
    PORT
      LAYER Metal3 ;
        RECT 0.530 1168.145 0.810 1169.305 ;
    END
    PORT
      LAYER Metal3 ;
        RECT 0.530 1176.725 0.810 1177.885 ;
    END
    PORT
      LAYER Metal3 ;
        RECT 0.530 1185.305 0.810 1186.465 ;
    END
    PORT
      LAYER Metal3 ;
        RECT 0.530 1193.885 0.810 1195.045 ;
    END
    PORT
      LAYER Metal3 ;
        RECT 0.530 1202.465 0.810 1203.625 ;
    END
    PORT
      LAYER Metal3 ;
        RECT 0.530 1211.045 0.810 1212.205 ;
    END
    PORT
      LAYER Metal3 ;
        RECT 0.530 1219.625 0.810 1220.785 ;
    END
    PORT
      LAYER Metal3 ;
        RECT 0.530 1228.205 0.810 1229.365 ;
    END
    PORT
      LAYER Metal3 ;
        RECT 0.530 1236.785 0.810 1237.945 ;
    END
    PORT
      LAYER Metal3 ;
        RECT 0.530 1245.365 0.810 1246.525 ;
    END
    PORT
      LAYER Metal3 ;
        RECT 0.530 1253.945 0.810 1255.105 ;
    END
    PORT
      LAYER Metal3 ;
        RECT 0.530 1262.525 0.810 1263.685 ;
    END
    PORT
      LAYER Metal3 ;
        RECT 0.530 1271.105 0.810 1272.265 ;
    END
    PORT
      LAYER Metal3 ;
        RECT 0.530 1279.685 0.810 1280.845 ;
    END
    PORT
      LAYER Metal3 ;
        RECT 0.530 1288.265 0.810 1289.425 ;
    END
    PORT
      LAYER Metal3 ;
        RECT 0.530 1296.845 0.810 1298.005 ;
    END
    PORT
      LAYER Metal3 ;
        RECT 0.530 1305.425 0.810 1306.585 ;
    END
    PORT
      LAYER Metal3 ;
        RECT 0.530 1314.005 0.810 1315.165 ;
    END
    PORT
      LAYER Metal3 ;
        RECT 0.530 1322.585 0.810 1323.745 ;
    END
    PORT
      LAYER Metal3 ;
        RECT 0.530 1331.165 0.810 1332.325 ;
    END
    PORT
      LAYER Metal3 ;
        RECT 0.530 1339.745 0.810 1340.905 ;
    END
    PORT
      LAYER Metal3 ;
        RECT 0.530 1348.325 0.810 1349.485 ;
    END
    PORT
      LAYER Metal3 ;
        RECT 0.530 1356.905 0.810 1358.065 ;
    END
    PORT
      LAYER Metal3 ;
        RECT 0.530 1365.485 0.810 1366.645 ;
    END
    PORT
      LAYER Metal3 ;
        RECT 0.530 1374.065 0.810 1375.225 ;
    END
    PORT
      LAYER Metal3 ;
        RECT 0.530 1382.645 0.810 1383.805 ;
    END
    PORT
      LAYER Metal3 ;
        RECT 0.530 1391.225 0.810 1392.385 ;
    END
    PORT
      LAYER Metal3 ;
        RECT 0.530 1399.805 0.810 1400.965 ;
    END
    PORT
      LAYER Metal3 ;
        RECT 0.530 1408.385 0.810 1409.545 ;
    END
    PORT
      LAYER Metal3 ;
        RECT 0.530 1416.965 0.810 1418.125 ;
    END
    PORT
      LAYER Metal3 ;
        RECT 0.530 1425.545 0.810 1426.705 ;
    END
    PORT
      LAYER Metal3 ;
        RECT 0.530 1434.125 0.810 1435.285 ;
    END
    PORT
      LAYER Metal3 ;
        RECT 0.530 1442.705 0.810 1443.865 ;
    END
    PORT
      LAYER Metal3 ;
        RECT 0.530 1451.285 0.810 1452.445 ;
    END
    PORT
      LAYER Metal3 ;
        RECT 0.530 1459.865 0.810 1461.025 ;
    END
    PORT
      LAYER Metal3 ;
        RECT 0.530 1468.445 0.810 1469.605 ;
    END
    PORT
      LAYER Metal3 ;
        RECT 0.530 1477.025 0.810 1478.185 ;
    END
    PORT
      LAYER Metal3 ;
        RECT 0.530 1485.605 0.810 1486.765 ;
    END
    PORT
      LAYER Metal3 ;
        RECT 0.530 1494.185 0.810 1495.345 ;
    END
    PORT
      LAYER Metal3 ;
        RECT 0.530 1502.765 0.810 1503.925 ;
    END
    PORT
      LAYER Metal3 ;
        RECT 0.530 1511.345 0.810 1512.505 ;
    END
    PORT
      LAYER Metal3 ;
        RECT 0.530 1519.925 0.810 1521.085 ;
    END
    PORT
      LAYER Metal3 ;
        RECT 0.530 1528.505 0.810 1529.665 ;
    END
    PORT
      LAYER Metal3 ;
        RECT 0.530 1537.085 0.810 1538.245 ;
    END
    PORT
      LAYER Metal3 ;
        RECT 0.530 1545.665 0.810 1546.825 ;
    END
    PORT
      LAYER Metal3 ;
        RECT 0.530 1554.245 0.810 1555.405 ;
    END
    PORT
      LAYER Metal3 ;
        RECT 0.530 1562.825 0.810 1563.985 ;
    END
    PORT
      LAYER Metal3 ;
        RECT 0.530 1571.405 0.810 1572.565 ;
    END
    PORT
      LAYER Metal3 ;
        RECT 0.530 1579.985 0.810 1581.145 ;
    END
    PORT
      LAYER Metal3 ;
        RECT 0.530 1588.565 0.810 1589.725 ;
    END
    PORT
      LAYER Metal3 ;
        RECT 0.530 1597.145 0.810 1598.305 ;
    END
    PORT
      LAYER Metal3 ;
        RECT 0.530 1605.725 0.810 1606.885 ;
    END
    PORT
      LAYER Metal3 ;
        RECT 0.530 1614.305 0.810 1615.465 ;
    END
    PORT
      LAYER Metal3 ;
        RECT 0.530 1622.885 0.810 1624.045 ;
    END
    PORT
      LAYER Metal3 ;
        RECT 0.530 1631.465 0.810 1632.625 ;
    END
    PORT
      LAYER Metal3 ;
        RECT 0.530 1640.045 0.810 1641.205 ;
    END
    PORT
      LAYER Metal3 ;
        RECT 0.530 1648.625 0.810 1649.785 ;
    END
    PORT
      LAYER Metal3 ;
        RECT 0.530 1657.205 0.810 1658.365 ;
    END
    PORT
      LAYER Metal3 ;
        RECT 0.530 1665.785 0.810 1666.945 ;
    END
    PORT
      LAYER Metal3 ;
        RECT 0.530 1674.365 0.810 1675.525 ;
    END
    PORT
      LAYER Metal3 ;
        RECT 0.530 1682.945 0.810 1684.105 ;
    END
    PORT
      LAYER Metal3 ;
        RECT 0.530 1691.525 0.810 1692.685 ;
    END
    PORT
      LAYER Metal3 ;
        RECT 0.530 1700.105 0.810 1701.265 ;
    END
    PORT
      LAYER Metal3 ;
        RECT 0.530 1708.685 0.810 1709.845 ;
    END
    PORT
      LAYER Metal3 ;
        RECT 0.530 1717.265 0.810 1718.425 ;
    END
    PORT
      LAYER Metal3 ;
        RECT 0.530 1725.845 0.810 1727.005 ;
    END
    PORT
      LAYER Metal3 ;
        RECT 0.530 1734.425 0.810 1735.585 ;
    END
    PORT
      LAYER Metal3 ;
        RECT 0.530 1743.005 0.810 1744.165 ;
    END
    PORT
      LAYER Metal3 ;
        RECT 0.530 1751.585 0.810 1752.745 ;
    END
    PORT
      LAYER Metal3 ;
        RECT 0.530 1760.165 0.810 1761.325 ;
    END
    PORT
      LAYER Metal3 ;
        RECT 0.530 1768.745 0.810 1769.905 ;
    END
    PORT
      LAYER Metal3 ;
        RECT 0.530 1777.325 0.810 1778.485 ;
    END
    PORT
      LAYER Metal3 ;
        RECT 0.530 1785.905 0.810 1787.065 ;
    END
    PORT
      LAYER Metal3 ;
        RECT 0.530 1794.485 0.810 1795.645 ;
    END
    PORT
      LAYER Metal3 ;
        RECT 0.530 1803.065 0.810 1804.225 ;
    END
    PORT
      LAYER Metal3 ;
        RECT 0.530 1811.645 0.810 1812.805 ;
    END
    PORT
      LAYER Metal3 ;
        RECT 0.530 1820.225 0.810 1821.385 ;
    END
    PORT
      LAYER Metal3 ;
        RECT 0.530 1828.805 0.810 1829.965 ;
    END
    PORT
      LAYER Metal3 ;
        RECT 0.530 1837.385 0.810 1838.545 ;
    END
    PORT
      LAYER Metal3 ;
        RECT 0.530 1845.965 0.810 1847.125 ;
    END
    PORT
      LAYER Metal3 ;
        RECT 0.530 1854.545 0.810 1855.705 ;
    END
    PORT
      LAYER Metal3 ;
        RECT 0.530 1863.125 0.810 1864.285 ;
    END
    PORT
      LAYER Metal3 ;
        RECT 0.530 1871.705 0.810 1872.865 ;
    END
    PORT
      LAYER Metal3 ;
        RECT 0.530 1880.285 0.810 1881.445 ;
    END
    PORT
      LAYER Metal3 ;
        RECT 0.530 1888.865 0.810 1890.025 ;
    END
    PORT
      LAYER Metal3 ;
        RECT 0.530 1897.445 0.810 1898.605 ;
    END
    PORT
      LAYER Metal3 ;
        RECT 0.530 1906.025 0.810 1907.185 ;
    END
    PORT
      LAYER Metal3 ;
        RECT 0.530 1914.605 0.810 1915.765 ;
    END
    PORT
      LAYER Metal3 ;
        RECT 0.530 1923.185 0.810 1924.345 ;
    END
    PORT
      LAYER Metal3 ;
        RECT 0.530 1931.765 0.810 1932.925 ;
    END
    PORT
      LAYER Metal3 ;
        RECT 0.530 1940.345 0.810 1941.505 ;
    END
    PORT
      LAYER Metal3 ;
        RECT 0.530 1948.925 0.810 1950.085 ;
    END
    PORT
      LAYER Metal3 ;
        RECT 0.530 1957.505 0.810 1958.665 ;
    END
    PORT
      LAYER Metal3 ;
        RECT 0.530 1966.085 0.810 1967.245 ;
    END
    PORT
      LAYER Metal3 ;
        RECT 0.530 1974.665 0.810 1975.825 ;
    END
    PORT
      LAYER Metal3 ;
        RECT 0.530 1983.245 0.810 1984.405 ;
    END
    PORT
      LAYER Metal3 ;
        RECT 0.530 1991.825 0.810 1992.985 ;
    END
    PORT
      LAYER Metal3 ;
        RECT 0.530 2000.405 0.810 2001.565 ;
    END
    PORT
      LAYER Metal3 ;
        RECT 0.530 2008.985 0.810 2010.145 ;
    END
    PORT
      LAYER Metal3 ;
        RECT 0.530 2017.565 0.810 2018.725 ;
    END
    PORT
      LAYER Metal3 ;
        RECT 0.530 2026.145 0.810 2027.305 ;
    END
    PORT
      LAYER Metal3 ;
        RECT 0.530 2034.725 0.810 2035.885 ;
    END
    PORT
      LAYER Metal3 ;
        RECT 0.530 2043.305 0.810 2044.465 ;
    END
    PORT
      LAYER Metal3 ;
        RECT 0.530 2051.885 0.810 2053.045 ;
    END
    PORT
      LAYER Metal3 ;
        RECT 0.530 2060.465 0.810 2061.625 ;
    END
  END GND

  OBS
    LAYER Metal1 ;
      RECT 5 5 2749.430 2056.625 ;
    LAYER Metal2 ;
      RECT 5 5 2749.430 2056.625 ;
    LAYER Metal3 ;
      RECT 5 5 2749.430 2056.625 ;
    LAYER Metal4 ;
      RECT 5 5 2749.430 2056.625 ;
    LAYER Metal5 ;
      RECT 5 5 2749.430 2056.625 ;
  END

END photodiode_layout
